VERSION 5.8 ;
BUSBITCHARS "[]" ;
DIVIDERCHAR "/" ;
UNITS
    DATABASE MICRONS 1000 ;
END UNITS

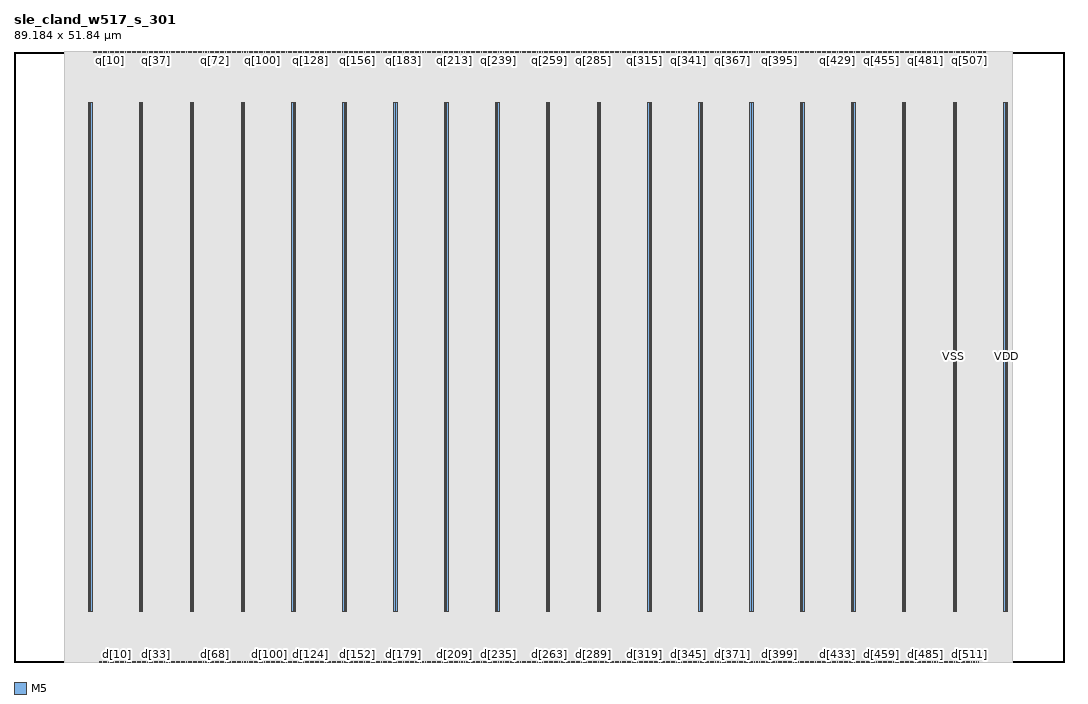
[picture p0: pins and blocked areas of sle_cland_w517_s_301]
MACRO sle_cland_w517_s_301
  FOREIGN sle_cland_w517_s_301 0 0 ;
  CLASS BLOCK ;
  SIZE 89.184 BY 51.84 ;
  PIN clk
    DIRECTION INPUT ;
    USE SIGNAL ;
    PORT
      LAYER M5 ;
        RECT  43.872 51.756 43.896 51.84 ;
    END
  END clk
  PIN d[0]
    DIRECTION INPUT ;
    USE SIGNAL ;
    PORT
      LAYER M5 ;
        RECT  7.296 0 7.32 0.084 ;
    END
  END d[0]
  PIN d[100]
    DIRECTION INPUT ;
    USE SIGNAL ;
    PORT
      LAYER M5 ;
        RECT  21.696 0 21.72 0.084 ;
    END
  END d[100]
  PIN d[101]
    DIRECTION INPUT ;
    USE SIGNAL ;
    PORT
      LAYER M5 ;
        RECT  21.84 0 21.864 0.084 ;
    END
  END d[101]
  PIN d[102]
    DIRECTION INPUT ;
    USE SIGNAL ;
    PORT
      LAYER M5 ;
        RECT  21.984 0 22.008 0.084 ;
    END
  END d[102]
  PIN d[103]
    DIRECTION INPUT ;
    USE SIGNAL ;
    PORT
      LAYER M5 ;
        RECT  22.128 0 22.152 0.084 ;
    END
  END d[103]
  PIN d[104]
    DIRECTION INPUT ;
    USE SIGNAL ;
    PORT
      LAYER M5 ;
        RECT  22.272 0 22.296 0.084 ;
    END
  END d[104]
  PIN d[105]
    DIRECTION INPUT ;
    USE SIGNAL ;
    PORT
      LAYER M5 ;
        RECT  22.416 0 22.44 0.084 ;
    END
  END d[105]
  PIN d[106]
    DIRECTION INPUT ;
    USE SIGNAL ;
    PORT
      LAYER M5 ;
        RECT  22.56 0 22.584 0.084 ;
    END
  END d[106]
  PIN d[107]
    DIRECTION INPUT ;
    USE SIGNAL ;
    PORT
      LAYER M5 ;
        RECT  22.704 0 22.728 0.084 ;
    END
  END d[107]
  PIN d[108]
    DIRECTION INPUT ;
    USE SIGNAL ;
    PORT
      LAYER M5 ;
        RECT  22.848 0 22.872 0.084 ;
    END
  END d[108]
  PIN d[109]
    DIRECTION INPUT ;
    USE SIGNAL ;
    PORT
      LAYER M5 ;
        RECT  22.992 0 23.016 0.084 ;
    END
  END d[109]
  PIN d[10]
    DIRECTION INPUT ;
    USE SIGNAL ;
    PORT
      LAYER M5 ;
        RECT  8.736 0 8.76 0.084 ;
    END
  END d[10]
  PIN d[110]
    DIRECTION INPUT ;
    USE SIGNAL ;
    PORT
      LAYER M5 ;
        RECT  23.136 0 23.16 0.084 ;
    END
  END d[110]
  PIN d[111]
    DIRECTION INPUT ;
    USE SIGNAL ;
    PORT
      LAYER M5 ;
        RECT  23.28 0 23.304 0.084 ;
    END
  END d[111]
  PIN d[112]
    DIRECTION INPUT ;
    USE SIGNAL ;
    PORT
      LAYER M5 ;
        RECT  23.424 0 23.448 0.084 ;
    END
  END d[112]
  PIN d[113]
    DIRECTION INPUT ;
    USE SIGNAL ;
    PORT
      LAYER M5 ;
        RECT  23.568 0 23.592 0.084 ;
    END
  END d[113]
  PIN d[114]
    DIRECTION INPUT ;
    USE SIGNAL ;
    PORT
      LAYER M5 ;
        RECT  23.712 0 23.736 0.084 ;
    END
  END d[114]
  PIN d[115]
    DIRECTION INPUT ;
    USE SIGNAL ;
    PORT
      LAYER M5 ;
        RECT  23.856 0 23.88 0.084 ;
    END
  END d[115]
  PIN d[116]
    DIRECTION INPUT ;
    USE SIGNAL ;
    PORT
      LAYER M5 ;
        RECT  24 0 24.024 0.084 ;
    END
  END d[116]
  PIN d[117]
    DIRECTION INPUT ;
    USE SIGNAL ;
    PORT
      LAYER M5 ;
        RECT  24.144 0 24.168 0.084 ;
    END
  END d[117]
  PIN d[118]
    DIRECTION INPUT ;
    USE SIGNAL ;
    PORT
      LAYER M5 ;
        RECT  24.288 0 24.312 0.084 ;
    END
  END d[118]
  PIN d[119]
    DIRECTION INPUT ;
    USE SIGNAL ;
    PORT
      LAYER M5 ;
        RECT  24.432 0 24.456 0.084 ;
    END
  END d[119]
  PIN d[11]
    DIRECTION INPUT ;
    USE SIGNAL ;
    PORT
      LAYER M5 ;
        RECT  8.88 0 8.904 0.084 ;
    END
  END d[11]
  PIN d[120]
    DIRECTION INPUT ;
    USE SIGNAL ;
    PORT
      LAYER M5 ;
        RECT  24.576 0 24.6 0.084 ;
    END
  END d[120]
  PIN d[121]
    DIRECTION INPUT ;
    USE SIGNAL ;
    PORT
      LAYER M5 ;
        RECT  24.72 0 24.744 0.084 ;
    END
  END d[121]
  PIN d[122]
    DIRECTION INPUT ;
    USE SIGNAL ;
    PORT
      LAYER M5 ;
        RECT  24.864 0 24.888 0.084 ;
    END
  END d[122]
  PIN d[123]
    DIRECTION INPUT ;
    USE SIGNAL ;
    PORT
      LAYER M5 ;
        RECT  25.008 0 25.032 0.084 ;
    END
  END d[123]
  PIN d[124]
    DIRECTION INPUT ;
    USE SIGNAL ;
    PORT
      LAYER M5 ;
        RECT  25.152 0 25.176 0.084 ;
    END
  END d[124]
  PIN d[125]
    DIRECTION INPUT ;
    USE SIGNAL ;
    PORT
      LAYER M5 ;
        RECT  25.296 0 25.32 0.084 ;
    END
  END d[125]
  PIN d[126]
    DIRECTION INPUT ;
    USE SIGNAL ;
    PORT
      LAYER M5 ;
        RECT  25.44 0 25.464 0.084 ;
    END
  END d[126]
  PIN d[127]
    DIRECTION INPUT ;
    USE SIGNAL ;
    PORT
      LAYER M5 ;
        RECT  25.584 0 25.608 0.084 ;
    END
  END d[127]
  PIN d[128]
    DIRECTION INPUT ;
    USE SIGNAL ;
    PORT
      LAYER M5 ;
        RECT  25.728 0 25.752 0.084 ;
    END
  END d[128]
  PIN d[129]
    DIRECTION INPUT ;
    USE SIGNAL ;
    PORT
      LAYER M5 ;
        RECT  25.872 0 25.896 0.084 ;
    END
  END d[129]
  PIN d[12]
    DIRECTION INPUT ;
    USE SIGNAL ;
    PORT
      LAYER M5 ;
        RECT  9.024 0 9.048 0.084 ;
    END
  END d[12]
  PIN d[130]
    DIRECTION INPUT ;
    USE SIGNAL ;
    PORT
      LAYER M5 ;
        RECT  26.016 0 26.04 0.084 ;
    END
  END d[130]
  PIN d[131]
    DIRECTION INPUT ;
    USE SIGNAL ;
    PORT
      LAYER M5 ;
        RECT  26.16 0 26.184 0.084 ;
    END
  END d[131]
  PIN d[132]
    DIRECTION INPUT ;
    USE SIGNAL ;
    PORT
      LAYER M5 ;
        RECT  26.304 0 26.328 0.084 ;
    END
  END d[132]
  PIN d[133]
    DIRECTION INPUT ;
    USE SIGNAL ;
    PORT
      LAYER M5 ;
        RECT  26.448 0 26.472 0.084 ;
    END
  END d[133]
  PIN d[134]
    DIRECTION INPUT ;
    USE SIGNAL ;
    PORT
      LAYER M5 ;
        RECT  26.592 0 26.616 0.084 ;
    END
  END d[134]
  PIN d[135]
    DIRECTION INPUT ;
    USE SIGNAL ;
    PORT
      LAYER M5 ;
        RECT  26.736 0 26.76 0.084 ;
    END
  END d[135]
  PIN d[136]
    DIRECTION INPUT ;
    USE SIGNAL ;
    PORT
      LAYER M5 ;
        RECT  26.88 0 26.904 0.084 ;
    END
  END d[136]
  PIN d[137]
    DIRECTION INPUT ;
    USE SIGNAL ;
    PORT
      LAYER M5 ;
        RECT  27.024 0 27.048 0.084 ;
    END
  END d[137]
  PIN d[138]
    DIRECTION INPUT ;
    USE SIGNAL ;
    PORT
      LAYER M5 ;
        RECT  27.168 0 27.192 0.084 ;
    END
  END d[138]
  PIN d[139]
    DIRECTION INPUT ;
    USE SIGNAL ;
    PORT
      LAYER M5 ;
        RECT  27.312 0 27.336 0.084 ;
    END
  END d[139]
  PIN d[13]
    DIRECTION INPUT ;
    USE SIGNAL ;
    PORT
      LAYER M5 ;
        RECT  9.168 0 9.192 0.084 ;
    END
  END d[13]
  PIN d[140]
    DIRECTION INPUT ;
    USE SIGNAL ;
    PORT
      LAYER M5 ;
        RECT  27.456 0 27.48 0.084 ;
    END
  END d[140]
  PIN d[141]
    DIRECTION INPUT ;
    USE SIGNAL ;
    PORT
      LAYER M5 ;
        RECT  27.6 0 27.624 0.084 ;
    END
  END d[141]
  PIN d[142]
    DIRECTION INPUT ;
    USE SIGNAL ;
    PORT
      LAYER M5 ;
        RECT  27.744 0 27.768 0.084 ;
    END
  END d[142]
  PIN d[143]
    DIRECTION INPUT ;
    USE SIGNAL ;
    PORT
      LAYER M5 ;
        RECT  27.888 0 27.912 0.084 ;
    END
  END d[143]
  PIN d[144]
    DIRECTION INPUT ;
    USE SIGNAL ;
    PORT
      LAYER M5 ;
        RECT  28.032 0 28.056 0.084 ;
    END
  END d[144]
  PIN d[145]
    DIRECTION INPUT ;
    USE SIGNAL ;
    PORT
      LAYER M5 ;
        RECT  28.176 0 28.2 0.084 ;
    END
  END d[145]
  PIN d[146]
    DIRECTION INPUT ;
    USE SIGNAL ;
    PORT
      LAYER M5 ;
        RECT  28.32 0 28.344 0.084 ;
    END
  END d[146]
  PIN d[147]
    DIRECTION INPUT ;
    USE SIGNAL ;
    PORT
      LAYER M5 ;
        RECT  28.464 0 28.488 0.084 ;
    END
  END d[147]
  PIN d[148]
    DIRECTION INPUT ;
    USE SIGNAL ;
    PORT
      LAYER M5 ;
        RECT  28.608 0 28.632 0.084 ;
    END
  END d[148]
  PIN d[149]
    DIRECTION INPUT ;
    USE SIGNAL ;
    PORT
      LAYER M5 ;
        RECT  28.752 0 28.776 0.084 ;
    END
  END d[149]
  PIN d[14]
    DIRECTION INPUT ;
    USE SIGNAL ;
    PORT
      LAYER M5 ;
        RECT  9.312 0 9.336 0.084 ;
    END
  END d[14]
  PIN d[150]
    DIRECTION INPUT ;
    USE SIGNAL ;
    PORT
      LAYER M5 ;
        RECT  28.896 0 28.92 0.084 ;
    END
  END d[150]
  PIN d[151]
    DIRECTION INPUT ;
    USE SIGNAL ;
    PORT
      LAYER M5 ;
        RECT  29.04 0 29.064 0.084 ;
    END
  END d[151]
  PIN d[152]
    DIRECTION INPUT ;
    USE SIGNAL ;
    PORT
      LAYER M5 ;
        RECT  29.184 0 29.208 0.084 ;
    END
  END d[152]
  PIN d[153]
    DIRECTION INPUT ;
    USE SIGNAL ;
    PORT
      LAYER M5 ;
        RECT  29.328 0 29.352 0.084 ;
    END
  END d[153]
  PIN d[154]
    DIRECTION INPUT ;
    USE SIGNAL ;
    PORT
      LAYER M5 ;
        RECT  29.472 0 29.496 0.084 ;
    END
  END d[154]
  PIN d[155]
    DIRECTION INPUT ;
    USE SIGNAL ;
    PORT
      LAYER M5 ;
        RECT  29.616 0 29.64 0.084 ;
    END
  END d[155]
  PIN d[156]
    DIRECTION INPUT ;
    USE SIGNAL ;
    PORT
      LAYER M5 ;
        RECT  29.76 0 29.784 0.084 ;
    END
  END d[156]
  PIN d[157]
    DIRECTION INPUT ;
    USE SIGNAL ;
    PORT
      LAYER M5 ;
        RECT  29.904 0 29.928 0.084 ;
    END
  END d[157]
  PIN d[158]
    DIRECTION INPUT ;
    USE SIGNAL ;
    PORT
      LAYER M5 ;
        RECT  30.048 0 30.072 0.084 ;
    END
  END d[158]
  PIN d[159]
    DIRECTION INPUT ;
    USE SIGNAL ;
    PORT
      LAYER M5 ;
        RECT  30.192 0 30.216 0.084 ;
    END
  END d[159]
  PIN d[15]
    DIRECTION INPUT ;
    USE SIGNAL ;
    PORT
      LAYER M5 ;
        RECT  9.456 0 9.48 0.084 ;
    END
  END d[15]
  PIN d[160]
    DIRECTION INPUT ;
    USE SIGNAL ;
    PORT
      LAYER M5 ;
        RECT  30.336 0 30.36 0.084 ;
    END
  END d[160]
  PIN d[161]
    DIRECTION INPUT ;
    USE SIGNAL ;
    PORT
      LAYER M5 ;
        RECT  30.48 0 30.504 0.084 ;
    END
  END d[161]
  PIN d[162]
    DIRECTION INPUT ;
    USE SIGNAL ;
    PORT
      LAYER M5 ;
        RECT  30.624 0 30.648 0.084 ;
    END
  END d[162]
  PIN d[163]
    DIRECTION INPUT ;
    USE SIGNAL ;
    PORT
      LAYER M5 ;
        RECT  30.768 0 30.792 0.084 ;
    END
  END d[163]
  PIN d[164]
    DIRECTION INPUT ;
    USE SIGNAL ;
    PORT
      LAYER M5 ;
        RECT  30.912 0 30.936 0.084 ;
    END
  END d[164]
  PIN d[165]
    DIRECTION INPUT ;
    USE SIGNAL ;
    PORT
      LAYER M5 ;
        RECT  31.056 0 31.08 0.084 ;
    END
  END d[165]
  PIN d[166]
    DIRECTION INPUT ;
    USE SIGNAL ;
    PORT
      LAYER M5 ;
        RECT  31.2 0 31.224 0.084 ;
    END
  END d[166]
  PIN d[167]
    DIRECTION INPUT ;
    USE SIGNAL ;
    PORT
      LAYER M5 ;
        RECT  31.344 0 31.368 0.084 ;
    END
  END d[167]
  PIN d[168]
    DIRECTION INPUT ;
    USE SIGNAL ;
    PORT
      LAYER M5 ;
        RECT  31.488 0 31.512 0.084 ;
    END
  END d[168]
  PIN d[169]
    DIRECTION INPUT ;
    USE SIGNAL ;
    PORT
      LAYER M5 ;
        RECT  31.632 0 31.656 0.084 ;
    END
  END d[169]
  PIN d[16]
    DIRECTION INPUT ;
    USE SIGNAL ;
    PORT
      LAYER M5 ;
        RECT  9.6 0 9.624 0.084 ;
    END
  END d[16]
  PIN d[170]
    DIRECTION INPUT ;
    USE SIGNAL ;
    PORT
      LAYER M5 ;
        RECT  31.776 0 31.8 0.084 ;
    END
  END d[170]
  PIN d[171]
    DIRECTION INPUT ;
    USE SIGNAL ;
    PORT
      LAYER M5 ;
        RECT  31.92 0 31.944 0.084 ;
    END
  END d[171]
  PIN d[172]
    DIRECTION INPUT ;
    USE SIGNAL ;
    PORT
      LAYER M5 ;
        RECT  32.064 0 32.088 0.084 ;
    END
  END d[172]
  PIN d[173]
    DIRECTION INPUT ;
    USE SIGNAL ;
    PORT
      LAYER M5 ;
        RECT  32.208 0 32.232 0.084 ;
    END
  END d[173]
  PIN d[174]
    DIRECTION INPUT ;
    USE SIGNAL ;
    PORT
      LAYER M5 ;
        RECT  32.352 0 32.376 0.084 ;
    END
  END d[174]
  PIN d[175]
    DIRECTION INPUT ;
    USE SIGNAL ;
    PORT
      LAYER M5 ;
        RECT  32.496 0 32.52 0.084 ;
    END
  END d[175]
  PIN d[176]
    DIRECTION INPUT ;
    USE SIGNAL ;
    PORT
      LAYER M5 ;
        RECT  32.64 0 32.664 0.084 ;
    END
  END d[176]
  PIN d[177]
    DIRECTION INPUT ;
    USE SIGNAL ;
    PORT
      LAYER M5 ;
        RECT  32.784 0 32.808 0.084 ;
    END
  END d[177]
  PIN d[178]
    DIRECTION INPUT ;
    USE SIGNAL ;
    PORT
      LAYER M5 ;
        RECT  32.928 0 32.952 0.084 ;
    END
  END d[178]
  PIN d[179]
    DIRECTION INPUT ;
    USE SIGNAL ;
    PORT
      LAYER M5 ;
        RECT  33.072 0 33.096 0.084 ;
    END
  END d[179]
  PIN d[17]
    DIRECTION INPUT ;
    USE SIGNAL ;
    PORT
      LAYER M5 ;
        RECT  9.744 0 9.768 0.084 ;
    END
  END d[17]
  PIN d[180]
    DIRECTION INPUT ;
    USE SIGNAL ;
    PORT
      LAYER M5 ;
        RECT  33.216 0 33.24 0.084 ;
    END
  END d[180]
  PIN d[181]
    DIRECTION INPUT ;
    USE SIGNAL ;
    PORT
      LAYER M5 ;
        RECT  33.36 0 33.384 0.084 ;
    END
  END d[181]
  PIN d[182]
    DIRECTION INPUT ;
    USE SIGNAL ;
    PORT
      LAYER M5 ;
        RECT  33.504 0 33.528 0.084 ;
    END
  END d[182]
  PIN d[183]
    DIRECTION INPUT ;
    USE SIGNAL ;
    PORT
      LAYER M5 ;
        RECT  33.648 0 33.672 0.084 ;
    END
  END d[183]
  PIN d[184]
    DIRECTION INPUT ;
    USE SIGNAL ;
    PORT
      LAYER M5 ;
        RECT  33.792 0 33.816 0.084 ;
    END
  END d[184]
  PIN d[185]
    DIRECTION INPUT ;
    USE SIGNAL ;
    PORT
      LAYER M5 ;
        RECT  33.936 0 33.96 0.084 ;
    END
  END d[185]
  PIN d[186]
    DIRECTION INPUT ;
    USE SIGNAL ;
    PORT
      LAYER M5 ;
        RECT  34.08 0 34.104 0.084 ;
    END
  END d[186]
  PIN d[187]
    DIRECTION INPUT ;
    USE SIGNAL ;
    PORT
      LAYER M5 ;
        RECT  34.224 0 34.248 0.084 ;
    END
  END d[187]
  PIN d[188]
    DIRECTION INPUT ;
    USE SIGNAL ;
    PORT
      LAYER M5 ;
        RECT  34.368 0 34.392 0.084 ;
    END
  END d[188]
  PIN d[189]
    DIRECTION INPUT ;
    USE SIGNAL ;
    PORT
      LAYER M5 ;
        RECT  34.512 0 34.536 0.084 ;
    END
  END d[189]
  PIN d[18]
    DIRECTION INPUT ;
    USE SIGNAL ;
    PORT
      LAYER M5 ;
        RECT  9.888 0 9.912 0.084 ;
    END
  END d[18]
  PIN d[190]
    DIRECTION INPUT ;
    USE SIGNAL ;
    PORT
      LAYER M5 ;
        RECT  34.656 0 34.68 0.084 ;
    END
  END d[190]
  PIN d[191]
    DIRECTION INPUT ;
    USE SIGNAL ;
    PORT
      LAYER M5 ;
        RECT  34.8 0 34.824 0.084 ;
    END
  END d[191]
  PIN d[192]
    DIRECTION INPUT ;
    USE SIGNAL ;
    PORT
      LAYER M5 ;
        RECT  34.944 0 34.968 0.084 ;
    END
  END d[192]
  PIN d[193]
    DIRECTION INPUT ;
    USE SIGNAL ;
    PORT
      LAYER M5 ;
        RECT  35.088 0 35.112 0.084 ;
    END
  END d[193]
  PIN d[194]
    DIRECTION INPUT ;
    USE SIGNAL ;
    PORT
      LAYER M5 ;
        RECT  35.232 0 35.256 0.084 ;
    END
  END d[194]
  PIN d[195]
    DIRECTION INPUT ;
    USE SIGNAL ;
    PORT
      LAYER M5 ;
        RECT  35.376 0 35.4 0.084 ;
    END
  END d[195]
  PIN d[196]
    DIRECTION INPUT ;
    USE SIGNAL ;
    PORT
      LAYER M5 ;
        RECT  35.52 0 35.544 0.084 ;
    END
  END d[196]
  PIN d[197]
    DIRECTION INPUT ;
    USE SIGNAL ;
    PORT
      LAYER M5 ;
        RECT  35.664 0 35.688 0.084 ;
    END
  END d[197]
  PIN d[198]
    DIRECTION INPUT ;
    USE SIGNAL ;
    PORT
      LAYER M5 ;
        RECT  35.808 0 35.832 0.084 ;
    END
  END d[198]
  PIN d[199]
    DIRECTION INPUT ;
    USE SIGNAL ;
    PORT
      LAYER M5 ;
        RECT  35.952 0 35.976 0.084 ;
    END
  END d[199]
  PIN d[19]
    DIRECTION INPUT ;
    USE SIGNAL ;
    PORT
      LAYER M5 ;
        RECT  10.032 0 10.056 0.084 ;
    END
  END d[19]
  PIN d[1]
    DIRECTION INPUT ;
    USE SIGNAL ;
    PORT
      LAYER M5 ;
        RECT  7.44 0 7.464 0.084 ;
    END
  END d[1]
  PIN d[200]
    DIRECTION INPUT ;
    USE SIGNAL ;
    PORT
      LAYER M5 ;
        RECT  36.096 0 36.12 0.084 ;
    END
  END d[200]
  PIN d[201]
    DIRECTION INPUT ;
    USE SIGNAL ;
    PORT
      LAYER M5 ;
        RECT  36.24 0 36.264 0.084 ;
    END
  END d[201]
  PIN d[202]
    DIRECTION INPUT ;
    USE SIGNAL ;
    PORT
      LAYER M5 ;
        RECT  36.384 0 36.408 0.084 ;
    END
  END d[202]
  PIN d[203]
    DIRECTION INPUT ;
    USE SIGNAL ;
    PORT
      LAYER M5 ;
        RECT  36.528 0 36.552 0.084 ;
    END
  END d[203]
  PIN d[204]
    DIRECTION INPUT ;
    USE SIGNAL ;
    PORT
      LAYER M5 ;
        RECT  36.672 0 36.696 0.084 ;
    END
  END d[204]
  PIN d[205]
    DIRECTION INPUT ;
    USE SIGNAL ;
    PORT
      LAYER M5 ;
        RECT  36.816 0 36.84 0.084 ;
    END
  END d[205]
  PIN d[206]
    DIRECTION INPUT ;
    USE SIGNAL ;
    PORT
      LAYER M5 ;
        RECT  36.96 0 36.984 0.084 ;
    END
  END d[206]
  PIN d[207]
    DIRECTION INPUT ;
    USE SIGNAL ;
    PORT
      LAYER M5 ;
        RECT  37.104 0 37.128 0.084 ;
    END
  END d[207]
  PIN d[208]
    DIRECTION INPUT ;
    USE SIGNAL ;
    PORT
      LAYER M5 ;
        RECT  37.248 0 37.272 0.084 ;
    END
  END d[208]
  PIN d[209]
    DIRECTION INPUT ;
    USE SIGNAL ;
    PORT
      LAYER M5 ;
        RECT  37.392 0 37.416 0.084 ;
    END
  END d[209]
  PIN d[20]
    DIRECTION INPUT ;
    USE SIGNAL ;
    PORT
      LAYER M5 ;
        RECT  10.176 0 10.2 0.084 ;
    END
  END d[20]
  PIN d[210]
    DIRECTION INPUT ;
    USE SIGNAL ;
    PORT
      LAYER M5 ;
        RECT  37.536 0 37.56 0.084 ;
    END
  END d[210]
  PIN d[211]
    DIRECTION INPUT ;
    USE SIGNAL ;
    PORT
      LAYER M5 ;
        RECT  37.68 0 37.704 0.084 ;
    END
  END d[211]
  PIN d[212]
    DIRECTION INPUT ;
    USE SIGNAL ;
    PORT
      LAYER M5 ;
        RECT  37.824 0 37.848 0.084 ;
    END
  END d[212]
  PIN d[213]
    DIRECTION INPUT ;
    USE SIGNAL ;
    PORT
      LAYER M5 ;
        RECT  37.968 0 37.992 0.084 ;
    END
  END d[213]
  PIN d[214]
    DIRECTION INPUT ;
    USE SIGNAL ;
    PORT
      LAYER M5 ;
        RECT  38.112 0 38.136 0.084 ;
    END
  END d[214]
  PIN d[215]
    DIRECTION INPUT ;
    USE SIGNAL ;
    PORT
      LAYER M5 ;
        RECT  38.256 0 38.28 0.084 ;
    END
  END d[215]
  PIN d[216]
    DIRECTION INPUT ;
    USE SIGNAL ;
    PORT
      LAYER M5 ;
        RECT  38.4 0 38.424 0.084 ;
    END
  END d[216]
  PIN d[217]
    DIRECTION INPUT ;
    USE SIGNAL ;
    PORT
      LAYER M5 ;
        RECT  38.544 0 38.568 0.084 ;
    END
  END d[217]
  PIN d[218]
    DIRECTION INPUT ;
    USE SIGNAL ;
    PORT
      LAYER M5 ;
        RECT  38.688 0 38.712 0.084 ;
    END
  END d[218]
  PIN d[219]
    DIRECTION INPUT ;
    USE SIGNAL ;
    PORT
      LAYER M5 ;
        RECT  38.832 0 38.856 0.084 ;
    END
  END d[219]
  PIN d[21]
    DIRECTION INPUT ;
    USE SIGNAL ;
    PORT
      LAYER M5 ;
        RECT  10.32 0 10.344 0.084 ;
    END
  END d[21]
  PIN d[220]
    DIRECTION INPUT ;
    USE SIGNAL ;
    PORT
      LAYER M5 ;
        RECT  38.976 0 39 0.084 ;
    END
  END d[220]
  PIN d[221]
    DIRECTION INPUT ;
    USE SIGNAL ;
    PORT
      LAYER M5 ;
        RECT  39.12 0 39.144 0.084 ;
    END
  END d[221]
  PIN d[222]
    DIRECTION INPUT ;
    USE SIGNAL ;
    PORT
      LAYER M5 ;
        RECT  39.264 0 39.288 0.084 ;
    END
  END d[222]
  PIN d[223]
    DIRECTION INPUT ;
    USE SIGNAL ;
    PORT
      LAYER M5 ;
        RECT  39.408 0 39.432 0.084 ;
    END
  END d[223]
  PIN d[224]
    DIRECTION INPUT ;
    USE SIGNAL ;
    PORT
      LAYER M5 ;
        RECT  39.552 0 39.576 0.084 ;
    END
  END d[224]
  PIN d[225]
    DIRECTION INPUT ;
    USE SIGNAL ;
    PORT
      LAYER M5 ;
        RECT  39.696 0 39.72 0.084 ;
    END
  END d[225]
  PIN d[226]
    DIRECTION INPUT ;
    USE SIGNAL ;
    PORT
      LAYER M5 ;
        RECT  39.84 0 39.864 0.084 ;
    END
  END d[226]
  PIN d[227]
    DIRECTION INPUT ;
    USE SIGNAL ;
    PORT
      LAYER M5 ;
        RECT  39.984 0 40.008 0.084 ;
    END
  END d[227]
  PIN d[228]
    DIRECTION INPUT ;
    USE SIGNAL ;
    PORT
      LAYER M5 ;
        RECT  40.128 0 40.152 0.084 ;
    END
  END d[228]
  PIN d[229]
    DIRECTION INPUT ;
    USE SIGNAL ;
    PORT
      LAYER M5 ;
        RECT  40.272 0 40.296 0.084 ;
    END
  END d[229]
  PIN d[22]
    DIRECTION INPUT ;
    USE SIGNAL ;
    PORT
      LAYER M5 ;
        RECT  10.464 0 10.488 0.084 ;
    END
  END d[22]
  PIN d[230]
    DIRECTION INPUT ;
    USE SIGNAL ;
    PORT
      LAYER M5 ;
        RECT  40.416 0 40.44 0.084 ;
    END
  END d[230]
  PIN d[231]
    DIRECTION INPUT ;
    USE SIGNAL ;
    PORT
      LAYER M5 ;
        RECT  40.56 0 40.584 0.084 ;
    END
  END d[231]
  PIN d[232]
    DIRECTION INPUT ;
    USE SIGNAL ;
    PORT
      LAYER M5 ;
        RECT  40.704 0 40.728 0.084 ;
    END
  END d[232]
  PIN d[233]
    DIRECTION INPUT ;
    USE SIGNAL ;
    PORT
      LAYER M5 ;
        RECT  40.848 0 40.872 0.084 ;
    END
  END d[233]
  PIN d[234]
    DIRECTION INPUT ;
    USE SIGNAL ;
    PORT
      LAYER M5 ;
        RECT  40.992 0 41.016 0.084 ;
    END
  END d[234]
  PIN d[235]
    DIRECTION INPUT ;
    USE SIGNAL ;
    PORT
      LAYER M5 ;
        RECT  41.136 0 41.16 0.084 ;
    END
  END d[235]
  PIN d[236]
    DIRECTION INPUT ;
    USE SIGNAL ;
    PORT
      LAYER M5 ;
        RECT  41.28 0 41.304 0.084 ;
    END
  END d[236]
  PIN d[237]
    DIRECTION INPUT ;
    USE SIGNAL ;
    PORT
      LAYER M5 ;
        RECT  41.424 0 41.448 0.084 ;
    END
  END d[237]
  PIN d[238]
    DIRECTION INPUT ;
    USE SIGNAL ;
    PORT
      LAYER M5 ;
        RECT  41.568 0 41.592 0.084 ;
    END
  END d[238]
  PIN d[239]
    DIRECTION INPUT ;
    USE SIGNAL ;
    PORT
      LAYER M5 ;
        RECT  41.712 0 41.736 0.084 ;
    END
  END d[239]
  PIN d[23]
    DIRECTION INPUT ;
    USE SIGNAL ;
    PORT
      LAYER M5 ;
        RECT  10.608 0 10.632 0.084 ;
    END
  END d[23]
  PIN d[240]
    DIRECTION INPUT ;
    USE SIGNAL ;
    PORT
      LAYER M5 ;
        RECT  41.856 0 41.88 0.084 ;
    END
  END d[240]
  PIN d[241]
    DIRECTION INPUT ;
    USE SIGNAL ;
    PORT
      LAYER M5 ;
        RECT  42 0 42.024 0.084 ;
    END
  END d[241]
  PIN d[242]
    DIRECTION INPUT ;
    USE SIGNAL ;
    PORT
      LAYER M5 ;
        RECT  42.144 0 42.168 0.084 ;
    END
  END d[242]
  PIN d[243]
    DIRECTION INPUT ;
    USE SIGNAL ;
    PORT
      LAYER M5 ;
        RECT  42.288 0 42.312 0.084 ;
    END
  END d[243]
  PIN d[244]
    DIRECTION INPUT ;
    USE SIGNAL ;
    PORT
      LAYER M5 ;
        RECT  42.432 0 42.456 0.084 ;
    END
  END d[244]
  PIN d[245]
    DIRECTION INPUT ;
    USE SIGNAL ;
    PORT
      LAYER M5 ;
        RECT  42.576 0 42.6 0.084 ;
    END
  END d[245]
  PIN d[246]
    DIRECTION INPUT ;
    USE SIGNAL ;
    PORT
      LAYER M5 ;
        RECT  42.72 0 42.744 0.084 ;
    END
  END d[246]
  PIN d[247]
    DIRECTION INPUT ;
    USE SIGNAL ;
    PORT
      LAYER M5 ;
        RECT  42.864 0 42.888 0.084 ;
    END
  END d[247]
  PIN d[248]
    DIRECTION INPUT ;
    USE SIGNAL ;
    PORT
      LAYER M5 ;
        RECT  43.008 0 43.032 0.084 ;
    END
  END d[248]
  PIN d[249]
    DIRECTION INPUT ;
    USE SIGNAL ;
    PORT
      LAYER M5 ;
        RECT  43.152 0 43.176 0.084 ;
    END
  END d[249]
  PIN d[24]
    DIRECTION INPUT ;
    USE SIGNAL ;
    PORT
      LAYER M5 ;
        RECT  10.752 0 10.776 0.084 ;
    END
  END d[24]
  PIN d[250]
    DIRECTION INPUT ;
    USE SIGNAL ;
    PORT
      LAYER M5 ;
        RECT  43.296 0 43.32 0.084 ;
    END
  END d[250]
  PIN d[251]
    DIRECTION INPUT ;
    USE SIGNAL ;
    PORT
      LAYER M5 ;
        RECT  43.44 0 43.464 0.084 ;
    END
  END d[251]
  PIN d[252]
    DIRECTION INPUT ;
    USE SIGNAL ;
    PORT
      LAYER M5 ;
        RECT  43.584 0 43.608 0.084 ;
    END
  END d[252]
  PIN d[253]
    DIRECTION INPUT ;
    USE SIGNAL ;
    PORT
      LAYER M5 ;
        RECT  43.728 0 43.752 0.084 ;
    END
  END d[253]
  PIN d[254]
    DIRECTION INPUT ;
    USE SIGNAL ;
    PORT
      LAYER M5 ;
        RECT  43.872 0 43.896 0.084 ;
    END
  END d[254]
  PIN d[255]
    DIRECTION INPUT ;
    USE SIGNAL ;
    PORT
      LAYER M5 ;
        RECT  44.016 0 44.04 0.084 ;
    END
  END d[255]
  PIN d[256]
    DIRECTION INPUT ;
    USE SIGNAL ;
    PORT
      LAYER M5 ;
        RECT  44.16 0 44.184 0.084 ;
    END
  END d[256]
  PIN d[257]
    DIRECTION INPUT ;
    USE SIGNAL ;
    PORT
      LAYER M5 ;
        RECT  44.304 0 44.328 0.084 ;
    END
  END d[257]
  PIN d[258]
    DIRECTION INPUT ;
    USE SIGNAL ;
    PORT
      LAYER M5 ;
        RECT  44.736 0 44.76 0.084 ;
    END
  END d[258]
  PIN d[259]
    DIRECTION INPUT ;
    USE SIGNAL ;
    PORT
      LAYER M5 ;
        RECT  44.88 0 44.904 0.084 ;
    END
  END d[259]
  PIN d[25]
    DIRECTION INPUT ;
    USE SIGNAL ;
    PORT
      LAYER M5 ;
        RECT  10.896 0 10.92 0.084 ;
    END
  END d[25]
  PIN d[260]
    DIRECTION INPUT ;
    USE SIGNAL ;
    PORT
      LAYER M5 ;
        RECT  45.024 0 45.048 0.084 ;
    END
  END d[260]
  PIN d[261]
    DIRECTION INPUT ;
    USE SIGNAL ;
    PORT
      LAYER M5 ;
        RECT  45.168 0 45.192 0.084 ;
    END
  END d[261]
  PIN d[262]
    DIRECTION INPUT ;
    USE SIGNAL ;
    PORT
      LAYER M5 ;
        RECT  45.312 0 45.336 0.084 ;
    END
  END d[262]
  PIN d[263]
    DIRECTION INPUT ;
    USE SIGNAL ;
    PORT
      LAYER M5 ;
        RECT  45.456 0 45.48 0.084 ;
    END
  END d[263]
  PIN d[264]
    DIRECTION INPUT ;
    USE SIGNAL ;
    PORT
      LAYER M5 ;
        RECT  45.6 0 45.624 0.084 ;
    END
  END d[264]
  PIN d[265]
    DIRECTION INPUT ;
    USE SIGNAL ;
    PORT
      LAYER M5 ;
        RECT  45.744 0 45.768 0.084 ;
    END
  END d[265]
  PIN d[266]
    DIRECTION INPUT ;
    USE SIGNAL ;
    PORT
      LAYER M5 ;
        RECT  45.888 0 45.912 0.084 ;
    END
  END d[266]
  PIN d[267]
    DIRECTION INPUT ;
    USE SIGNAL ;
    PORT
      LAYER M5 ;
        RECT  46.032 0 46.056 0.084 ;
    END
  END d[267]
  PIN d[268]
    DIRECTION INPUT ;
    USE SIGNAL ;
    PORT
      LAYER M5 ;
        RECT  46.176 0 46.2 0.084 ;
    END
  END d[268]
  PIN d[269]
    DIRECTION INPUT ;
    USE SIGNAL ;
    PORT
      LAYER M5 ;
        RECT  46.32 0 46.344 0.084 ;
    END
  END d[269]
  PIN d[26]
    DIRECTION INPUT ;
    USE SIGNAL ;
    PORT
      LAYER M5 ;
        RECT  11.04 0 11.064 0.084 ;
    END
  END d[26]
  PIN d[270]
    DIRECTION INPUT ;
    USE SIGNAL ;
    PORT
      LAYER M5 ;
        RECT  46.464 0 46.488 0.084 ;
    END
  END d[270]
  PIN d[271]
    DIRECTION INPUT ;
    USE SIGNAL ;
    PORT
      LAYER M5 ;
        RECT  46.608 0 46.632 0.084 ;
    END
  END d[271]
  PIN d[272]
    DIRECTION INPUT ;
    USE SIGNAL ;
    PORT
      LAYER M5 ;
        RECT  46.752 0 46.776 0.084 ;
    END
  END d[272]
  PIN d[273]
    DIRECTION INPUT ;
    USE SIGNAL ;
    PORT
      LAYER M5 ;
        RECT  46.896 0 46.92 0.084 ;
    END
  END d[273]
  PIN d[274]
    DIRECTION INPUT ;
    USE SIGNAL ;
    PORT
      LAYER M5 ;
        RECT  47.04 0 47.064 0.084 ;
    END
  END d[274]
  PIN d[275]
    DIRECTION INPUT ;
    USE SIGNAL ;
    PORT
      LAYER M5 ;
        RECT  47.184 0 47.208 0.084 ;
    END
  END d[275]
  PIN d[276]
    DIRECTION INPUT ;
    USE SIGNAL ;
    PORT
      LAYER M5 ;
        RECT  47.328 0 47.352 0.084 ;
    END
  END d[276]
  PIN d[277]
    DIRECTION INPUT ;
    USE SIGNAL ;
    PORT
      LAYER M5 ;
        RECT  47.472 0 47.496 0.084 ;
    END
  END d[277]
  PIN d[278]
    DIRECTION INPUT ;
    USE SIGNAL ;
    PORT
      LAYER M5 ;
        RECT  47.616 0 47.64 0.084 ;
    END
  END d[278]
  PIN d[279]
    DIRECTION INPUT ;
    USE SIGNAL ;
    PORT
      LAYER M5 ;
        RECT  47.76 0 47.784 0.084 ;
    END
  END d[279]
  PIN d[27]
    DIRECTION INPUT ;
    USE SIGNAL ;
    PORT
      LAYER M5 ;
        RECT  11.184 0 11.208 0.084 ;
    END
  END d[27]
  PIN d[280]
    DIRECTION INPUT ;
    USE SIGNAL ;
    PORT
      LAYER M5 ;
        RECT  47.904 0 47.928 0.084 ;
    END
  END d[280]
  PIN d[281]
    DIRECTION INPUT ;
    USE SIGNAL ;
    PORT
      LAYER M5 ;
        RECT  48.048 0 48.072 0.084 ;
    END
  END d[281]
  PIN d[282]
    DIRECTION INPUT ;
    USE SIGNAL ;
    PORT
      LAYER M5 ;
        RECT  48.192 0 48.216 0.084 ;
    END
  END d[282]
  PIN d[283]
    DIRECTION INPUT ;
    USE SIGNAL ;
    PORT
      LAYER M5 ;
        RECT  48.336 0 48.36 0.084 ;
    END
  END d[283]
  PIN d[284]
    DIRECTION INPUT ;
    USE SIGNAL ;
    PORT
      LAYER M5 ;
        RECT  48.48 0 48.504 0.084 ;
    END
  END d[284]
  PIN d[285]
    DIRECTION INPUT ;
    USE SIGNAL ;
    PORT
      LAYER M5 ;
        RECT  48.624 0 48.648 0.084 ;
    END
  END d[285]
  PIN d[286]
    DIRECTION INPUT ;
    USE SIGNAL ;
    PORT
      LAYER M5 ;
        RECT  48.768 0 48.792 0.084 ;
    END
  END d[286]
  PIN d[287]
    DIRECTION INPUT ;
    USE SIGNAL ;
    PORT
      LAYER M5 ;
        RECT  48.912 0 48.936 0.084 ;
    END
  END d[287]
  PIN d[288]
    DIRECTION INPUT ;
    USE SIGNAL ;
    PORT
      LAYER M5 ;
        RECT  49.056 0 49.08 0.084 ;
    END
  END d[288]
  PIN d[289]
    DIRECTION INPUT ;
    USE SIGNAL ;
    PORT
      LAYER M5 ;
        RECT  49.2 0 49.224 0.084 ;
    END
  END d[289]
  PIN d[28]
    DIRECTION INPUT ;
    USE SIGNAL ;
    PORT
      LAYER M5 ;
        RECT  11.328 0 11.352 0.084 ;
    END
  END d[28]
  PIN d[290]
    DIRECTION INPUT ;
    USE SIGNAL ;
    PORT
      LAYER M5 ;
        RECT  49.344 0 49.368 0.084 ;
    END
  END d[290]
  PIN d[291]
    DIRECTION INPUT ;
    USE SIGNAL ;
    PORT
      LAYER M5 ;
        RECT  49.488 0 49.512 0.084 ;
    END
  END d[291]
  PIN d[292]
    DIRECTION INPUT ;
    USE SIGNAL ;
    PORT
      LAYER M5 ;
        RECT  49.632 0 49.656 0.084 ;
    END
  END d[292]
  PIN d[293]
    DIRECTION INPUT ;
    USE SIGNAL ;
    PORT
      LAYER M5 ;
        RECT  49.776 0 49.8 0.084 ;
    END
  END d[293]
  PIN d[294]
    DIRECTION INPUT ;
    USE SIGNAL ;
    PORT
      LAYER M5 ;
        RECT  49.92 0 49.944 0.084 ;
    END
  END d[294]
  PIN d[295]
    DIRECTION INPUT ;
    USE SIGNAL ;
    PORT
      LAYER M5 ;
        RECT  50.064 0 50.088 0.084 ;
    END
  END d[295]
  PIN d[296]
    DIRECTION INPUT ;
    USE SIGNAL ;
    PORT
      LAYER M5 ;
        RECT  50.208 0 50.232 0.084 ;
    END
  END d[296]
  PIN d[297]
    DIRECTION INPUT ;
    USE SIGNAL ;
    PORT
      LAYER M5 ;
        RECT  50.352 0 50.376 0.084 ;
    END
  END d[297]
  PIN d[298]
    DIRECTION INPUT ;
    USE SIGNAL ;
    PORT
      LAYER M5 ;
        RECT  50.496 0 50.52 0.084 ;
    END
  END d[298]
  PIN d[299]
    DIRECTION INPUT ;
    USE SIGNAL ;
    PORT
      LAYER M5 ;
        RECT  50.64 0 50.664 0.084 ;
    END
  END d[299]
  PIN d[29]
    DIRECTION INPUT ;
    USE SIGNAL ;
    PORT
      LAYER M5 ;
        RECT  11.472 0 11.496 0.084 ;
    END
  END d[29]
  PIN d[2]
    DIRECTION INPUT ;
    USE SIGNAL ;
    PORT
      LAYER M5 ;
        RECT  7.584 0 7.608 0.084 ;
    END
  END d[2]
  PIN d[300]
    DIRECTION INPUT ;
    USE SIGNAL ;
    PORT
      LAYER M5 ;
        RECT  50.784 0 50.808 0.084 ;
    END
  END d[300]
  PIN d[301]
    DIRECTION INPUT ;
    USE SIGNAL ;
    PORT
      LAYER M5 ;
        RECT  50.928 0 50.952 0.084 ;
    END
  END d[301]
  PIN d[302]
    DIRECTION INPUT ;
    USE SIGNAL ;
    PORT
      LAYER M5 ;
        RECT  51.072 0 51.096 0.084 ;
    END
  END d[302]
  PIN d[303]
    DIRECTION INPUT ;
    USE SIGNAL ;
    PORT
      LAYER M5 ;
        RECT  51.216 0 51.24 0.084 ;
    END
  END d[303]
  PIN d[304]
    DIRECTION INPUT ;
    USE SIGNAL ;
    PORT
      LAYER M5 ;
        RECT  51.36 0 51.384 0.084 ;
    END
  END d[304]
  PIN d[305]
    DIRECTION INPUT ;
    USE SIGNAL ;
    PORT
      LAYER M5 ;
        RECT  51.504 0 51.528 0.084 ;
    END
  END d[305]
  PIN d[306]
    DIRECTION INPUT ;
    USE SIGNAL ;
    PORT
      LAYER M5 ;
        RECT  51.648 0 51.672 0.084 ;
    END
  END d[306]
  PIN d[307]
    DIRECTION INPUT ;
    USE SIGNAL ;
    PORT
      LAYER M5 ;
        RECT  51.792 0 51.816 0.084 ;
    END
  END d[307]
  PIN d[308]
    DIRECTION INPUT ;
    USE SIGNAL ;
    PORT
      LAYER M5 ;
        RECT  51.936 0 51.96 0.084 ;
    END
  END d[308]
  PIN d[309]
    DIRECTION INPUT ;
    USE SIGNAL ;
    PORT
      LAYER M5 ;
        RECT  52.08 0 52.104 0.084 ;
    END
  END d[309]
  PIN d[30]
    DIRECTION INPUT ;
    USE SIGNAL ;
    PORT
      LAYER M5 ;
        RECT  11.616 0 11.64 0.084 ;
    END
  END d[30]
  PIN d[310]
    DIRECTION INPUT ;
    USE SIGNAL ;
    PORT
      LAYER M5 ;
        RECT  52.224 0 52.248 0.084 ;
    END
  END d[310]
  PIN d[311]
    DIRECTION INPUT ;
    USE SIGNAL ;
    PORT
      LAYER M5 ;
        RECT  52.368 0 52.392 0.084 ;
    END
  END d[311]
  PIN d[312]
    DIRECTION INPUT ;
    USE SIGNAL ;
    PORT
      LAYER M5 ;
        RECT  52.512 0 52.536 0.084 ;
    END
  END d[312]
  PIN d[313]
    DIRECTION INPUT ;
    USE SIGNAL ;
    PORT
      LAYER M5 ;
        RECT  52.656 0 52.68 0.084 ;
    END
  END d[313]
  PIN d[314]
    DIRECTION INPUT ;
    USE SIGNAL ;
    PORT
      LAYER M5 ;
        RECT  52.8 0 52.824 0.084 ;
    END
  END d[314]
  PIN d[315]
    DIRECTION INPUT ;
    USE SIGNAL ;
    PORT
      LAYER M5 ;
        RECT  52.944 0 52.968 0.084 ;
    END
  END d[315]
  PIN d[316]
    DIRECTION INPUT ;
    USE SIGNAL ;
    PORT
      LAYER M5 ;
        RECT  53.088 0 53.112 0.084 ;
    END
  END d[316]
  PIN d[317]
    DIRECTION INPUT ;
    USE SIGNAL ;
    PORT
      LAYER M5 ;
        RECT  53.232 0 53.256 0.084 ;
    END
  END d[317]
  PIN d[318]
    DIRECTION INPUT ;
    USE SIGNAL ;
    PORT
      LAYER M5 ;
        RECT  53.376 0 53.4 0.084 ;
    END
  END d[318]
  PIN d[319]
    DIRECTION INPUT ;
    USE SIGNAL ;
    PORT
      LAYER M5 ;
        RECT  53.52 0 53.544 0.084 ;
    END
  END d[319]
  PIN d[31]
    DIRECTION INPUT ;
    USE SIGNAL ;
    PORT
      LAYER M5 ;
        RECT  11.76 0 11.784 0.084 ;
    END
  END d[31]
  PIN d[320]
    DIRECTION INPUT ;
    USE SIGNAL ;
    PORT
      LAYER M5 ;
        RECT  53.664 0 53.688 0.084 ;
    END
  END d[320]
  PIN d[321]
    DIRECTION INPUT ;
    USE SIGNAL ;
    PORT
      LAYER M5 ;
        RECT  53.808 0 53.832 0.084 ;
    END
  END d[321]
  PIN d[322]
    DIRECTION INPUT ;
    USE SIGNAL ;
    PORT
      LAYER M5 ;
        RECT  53.952 0 53.976 0.084 ;
    END
  END d[322]
  PIN d[323]
    DIRECTION INPUT ;
    USE SIGNAL ;
    PORT
      LAYER M5 ;
        RECT  54.096 0 54.12 0.084 ;
    END
  END d[323]
  PIN d[324]
    DIRECTION INPUT ;
    USE SIGNAL ;
    PORT
      LAYER M5 ;
        RECT  54.24 0 54.264 0.084 ;
    END
  END d[324]
  PIN d[325]
    DIRECTION INPUT ;
    USE SIGNAL ;
    PORT
      LAYER M5 ;
        RECT  54.384 0 54.408 0.084 ;
    END
  END d[325]
  PIN d[326]
    DIRECTION INPUT ;
    USE SIGNAL ;
    PORT
      LAYER M5 ;
        RECT  54.528 0 54.552 0.084 ;
    END
  END d[326]
  PIN d[327]
    DIRECTION INPUT ;
    USE SIGNAL ;
    PORT
      LAYER M5 ;
        RECT  54.672 0 54.696 0.084 ;
    END
  END d[327]
  PIN d[328]
    DIRECTION INPUT ;
    USE SIGNAL ;
    PORT
      LAYER M5 ;
        RECT  54.816 0 54.84 0.084 ;
    END
  END d[328]
  PIN d[329]
    DIRECTION INPUT ;
    USE SIGNAL ;
    PORT
      LAYER M5 ;
        RECT  54.96 0 54.984 0.084 ;
    END
  END d[329]
  PIN d[32]
    DIRECTION INPUT ;
    USE SIGNAL ;
    PORT
      LAYER M5 ;
        RECT  11.904 0 11.928 0.084 ;
    END
  END d[32]
  PIN d[330]
    DIRECTION INPUT ;
    USE SIGNAL ;
    PORT
      LAYER M5 ;
        RECT  55.104 0 55.128 0.084 ;
    END
  END d[330]
  PIN d[331]
    DIRECTION INPUT ;
    USE SIGNAL ;
    PORT
      LAYER M5 ;
        RECT  55.248 0 55.272 0.084 ;
    END
  END d[331]
  PIN d[332]
    DIRECTION INPUT ;
    USE SIGNAL ;
    PORT
      LAYER M5 ;
        RECT  55.392 0 55.416 0.084 ;
    END
  END d[332]
  PIN d[333]
    DIRECTION INPUT ;
    USE SIGNAL ;
    PORT
      LAYER M5 ;
        RECT  55.536 0 55.56 0.084 ;
    END
  END d[333]
  PIN d[334]
    DIRECTION INPUT ;
    USE SIGNAL ;
    PORT
      LAYER M5 ;
        RECT  55.68 0 55.704 0.084 ;
    END
  END d[334]
  PIN d[335]
    DIRECTION INPUT ;
    USE SIGNAL ;
    PORT
      LAYER M5 ;
        RECT  55.824 0 55.848 0.084 ;
    END
  END d[335]
  PIN d[336]
    DIRECTION INPUT ;
    USE SIGNAL ;
    PORT
      LAYER M5 ;
        RECT  55.968 0 55.992 0.084 ;
    END
  END d[336]
  PIN d[337]
    DIRECTION INPUT ;
    USE SIGNAL ;
    PORT
      LAYER M5 ;
        RECT  56.112 0 56.136 0.084 ;
    END
  END d[337]
  PIN d[338]
    DIRECTION INPUT ;
    USE SIGNAL ;
    PORT
      LAYER M5 ;
        RECT  56.256 0 56.28 0.084 ;
    END
  END d[338]
  PIN d[339]
    DIRECTION INPUT ;
    USE SIGNAL ;
    PORT
      LAYER M5 ;
        RECT  56.4 0 56.424 0.084 ;
    END
  END d[339]
  PIN d[33]
    DIRECTION INPUT ;
    USE SIGNAL ;
    PORT
      LAYER M5 ;
        RECT  12.048 0 12.072 0.084 ;
    END
  END d[33]
  PIN d[340]
    DIRECTION INPUT ;
    USE SIGNAL ;
    PORT
      LAYER M5 ;
        RECT  56.544 0 56.568 0.084 ;
    END
  END d[340]
  PIN d[341]
    DIRECTION INPUT ;
    USE SIGNAL ;
    PORT
      LAYER M5 ;
        RECT  56.688 0 56.712 0.084 ;
    END
  END d[341]
  PIN d[342]
    DIRECTION INPUT ;
    USE SIGNAL ;
    PORT
      LAYER M5 ;
        RECT  56.832 0 56.856 0.084 ;
    END
  END d[342]
  PIN d[343]
    DIRECTION INPUT ;
    USE SIGNAL ;
    PORT
      LAYER M5 ;
        RECT  56.976 0 57 0.084 ;
    END
  END d[343]
  PIN d[344]
    DIRECTION INPUT ;
    USE SIGNAL ;
    PORT
      LAYER M5 ;
        RECT  57.12 0 57.144 0.084 ;
    END
  END d[344]
  PIN d[345]
    DIRECTION INPUT ;
    USE SIGNAL ;
    PORT
      LAYER M5 ;
        RECT  57.264 0 57.288 0.084 ;
    END
  END d[345]
  PIN d[346]
    DIRECTION INPUT ;
    USE SIGNAL ;
    PORT
      LAYER M5 ;
        RECT  57.408 0 57.432 0.084 ;
    END
  END d[346]
  PIN d[347]
    DIRECTION INPUT ;
    USE SIGNAL ;
    PORT
      LAYER M5 ;
        RECT  57.552 0 57.576 0.084 ;
    END
  END d[347]
  PIN d[348]
    DIRECTION INPUT ;
    USE SIGNAL ;
    PORT
      LAYER M5 ;
        RECT  57.696 0 57.72 0.084 ;
    END
  END d[348]
  PIN d[349]
    DIRECTION INPUT ;
    USE SIGNAL ;
    PORT
      LAYER M5 ;
        RECT  57.84 0 57.864 0.084 ;
    END
  END d[349]
  PIN d[34]
    DIRECTION INPUT ;
    USE SIGNAL ;
    PORT
      LAYER M5 ;
        RECT  12.192 0 12.216 0.084 ;
    END
  END d[34]
  PIN d[350]
    DIRECTION INPUT ;
    USE SIGNAL ;
    PORT
      LAYER M5 ;
        RECT  57.984 0 58.008 0.084 ;
    END
  END d[350]
  PIN d[351]
    DIRECTION INPUT ;
    USE SIGNAL ;
    PORT
      LAYER M5 ;
        RECT  58.128 0 58.152 0.084 ;
    END
  END d[351]
  PIN d[352]
    DIRECTION INPUT ;
    USE SIGNAL ;
    PORT
      LAYER M5 ;
        RECT  58.272 0 58.296 0.084 ;
    END
  END d[352]
  PIN d[353]
    DIRECTION INPUT ;
    USE SIGNAL ;
    PORT
      LAYER M5 ;
        RECT  58.416 0 58.44 0.084 ;
    END
  END d[353]
  PIN d[354]
    DIRECTION INPUT ;
    USE SIGNAL ;
    PORT
      LAYER M5 ;
        RECT  58.56 0 58.584 0.084 ;
    END
  END d[354]
  PIN d[355]
    DIRECTION INPUT ;
    USE SIGNAL ;
    PORT
      LAYER M5 ;
        RECT  58.704 0 58.728 0.084 ;
    END
  END d[355]
  PIN d[356]
    DIRECTION INPUT ;
    USE SIGNAL ;
    PORT
      LAYER M5 ;
        RECT  58.848 0 58.872 0.084 ;
    END
  END d[356]
  PIN d[357]
    DIRECTION INPUT ;
    USE SIGNAL ;
    PORT
      LAYER M5 ;
        RECT  58.992 0 59.016 0.084 ;
    END
  END d[357]
  PIN d[358]
    DIRECTION INPUT ;
    USE SIGNAL ;
    PORT
      LAYER M5 ;
        RECT  59.136 0 59.16 0.084 ;
    END
  END d[358]
  PIN d[359]
    DIRECTION INPUT ;
    USE SIGNAL ;
    PORT
      LAYER M5 ;
        RECT  59.28 0 59.304 0.084 ;
    END
  END d[359]
  PIN d[35]
    DIRECTION INPUT ;
    USE SIGNAL ;
    PORT
      LAYER M5 ;
        RECT  12.336 0 12.36 0.084 ;
    END
  END d[35]
  PIN d[360]
    DIRECTION INPUT ;
    USE SIGNAL ;
    PORT
      LAYER M5 ;
        RECT  59.424 0 59.448 0.084 ;
    END
  END d[360]
  PIN d[361]
    DIRECTION INPUT ;
    USE SIGNAL ;
    PORT
      LAYER M5 ;
        RECT  59.568 0 59.592 0.084 ;
    END
  END d[361]
  PIN d[362]
    DIRECTION INPUT ;
    USE SIGNAL ;
    PORT
      LAYER M5 ;
        RECT  59.712 0 59.736 0.084 ;
    END
  END d[362]
  PIN d[363]
    DIRECTION INPUT ;
    USE SIGNAL ;
    PORT
      LAYER M5 ;
        RECT  59.856 0 59.88 0.084 ;
    END
  END d[363]
  PIN d[364]
    DIRECTION INPUT ;
    USE SIGNAL ;
    PORT
      LAYER M5 ;
        RECT  60 0 60.024 0.084 ;
    END
  END d[364]
  PIN d[365]
    DIRECTION INPUT ;
    USE SIGNAL ;
    PORT
      LAYER M5 ;
        RECT  60.144 0 60.168 0.084 ;
    END
  END d[365]
  PIN d[366]
    DIRECTION INPUT ;
    USE SIGNAL ;
    PORT
      LAYER M5 ;
        RECT  60.288 0 60.312 0.084 ;
    END
  END d[366]
  PIN d[367]
    DIRECTION INPUT ;
    USE SIGNAL ;
    PORT
      LAYER M5 ;
        RECT  60.432 0 60.456 0.084 ;
    END
  END d[367]
  PIN d[368]
    DIRECTION INPUT ;
    USE SIGNAL ;
    PORT
      LAYER M5 ;
        RECT  60.576 0 60.6 0.084 ;
    END
  END d[368]
  PIN d[369]
    DIRECTION INPUT ;
    USE SIGNAL ;
    PORT
      LAYER M5 ;
        RECT  60.72 0 60.744 0.084 ;
    END
  END d[369]
  PIN d[36]
    DIRECTION INPUT ;
    USE SIGNAL ;
    PORT
      LAYER M5 ;
        RECT  12.48 0 12.504 0.084 ;
    END
  END d[36]
  PIN d[370]
    DIRECTION INPUT ;
    USE SIGNAL ;
    PORT
      LAYER M5 ;
        RECT  60.864 0 60.888 0.084 ;
    END
  END d[370]
  PIN d[371]
    DIRECTION INPUT ;
    USE SIGNAL ;
    PORT
      LAYER M5 ;
        RECT  61.008 0 61.032 0.084 ;
    END
  END d[371]
  PIN d[372]
    DIRECTION INPUT ;
    USE SIGNAL ;
    PORT
      LAYER M5 ;
        RECT  61.152 0 61.176 0.084 ;
    END
  END d[372]
  PIN d[373]
    DIRECTION INPUT ;
    USE SIGNAL ;
    PORT
      LAYER M5 ;
        RECT  61.296 0 61.32 0.084 ;
    END
  END d[373]
  PIN d[374]
    DIRECTION INPUT ;
    USE SIGNAL ;
    PORT
      LAYER M5 ;
        RECT  61.44 0 61.464 0.084 ;
    END
  END d[374]
  PIN d[375]
    DIRECTION INPUT ;
    USE SIGNAL ;
    PORT
      LAYER M5 ;
        RECT  61.584 0 61.608 0.084 ;
    END
  END d[375]
  PIN d[376]
    DIRECTION INPUT ;
    USE SIGNAL ;
    PORT
      LAYER M5 ;
        RECT  61.728 0 61.752 0.084 ;
    END
  END d[376]
  PIN d[377]
    DIRECTION INPUT ;
    USE SIGNAL ;
    PORT
      LAYER M5 ;
        RECT  61.872 0 61.896 0.084 ;
    END
  END d[377]
  PIN d[378]
    DIRECTION INPUT ;
    USE SIGNAL ;
    PORT
      LAYER M5 ;
        RECT  62.016 0 62.04 0.084 ;
    END
  END d[378]
  PIN d[379]
    DIRECTION INPUT ;
    USE SIGNAL ;
    PORT
      LAYER M5 ;
        RECT  62.16 0 62.184 0.084 ;
    END
  END d[379]
  PIN d[37]
    DIRECTION INPUT ;
    USE SIGNAL ;
    PORT
      LAYER M5 ;
        RECT  12.624 0 12.648 0.084 ;
    END
  END d[37]
  PIN d[380]
    DIRECTION INPUT ;
    USE SIGNAL ;
    PORT
      LAYER M5 ;
        RECT  62.304 0 62.328 0.084 ;
    END
  END d[380]
  PIN d[381]
    DIRECTION INPUT ;
    USE SIGNAL ;
    PORT
      LAYER M5 ;
        RECT  62.448 0 62.472 0.084 ;
    END
  END d[381]
  PIN d[382]
    DIRECTION INPUT ;
    USE SIGNAL ;
    PORT
      LAYER M5 ;
        RECT  62.592 0 62.616 0.084 ;
    END
  END d[382]
  PIN d[383]
    DIRECTION INPUT ;
    USE SIGNAL ;
    PORT
      LAYER M5 ;
        RECT  62.736 0 62.76 0.084 ;
    END
  END d[383]
  PIN d[384]
    DIRECTION INPUT ;
    USE SIGNAL ;
    PORT
      LAYER M5 ;
        RECT  62.88 0 62.904 0.084 ;
    END
  END d[384]
  PIN d[385]
    DIRECTION INPUT ;
    USE SIGNAL ;
    PORT
      LAYER M5 ;
        RECT  63.024 0 63.048 0.084 ;
    END
  END d[385]
  PIN d[386]
    DIRECTION INPUT ;
    USE SIGNAL ;
    PORT
      LAYER M5 ;
        RECT  63.168 0 63.192 0.084 ;
    END
  END d[386]
  PIN d[387]
    DIRECTION INPUT ;
    USE SIGNAL ;
    PORT
      LAYER M5 ;
        RECT  63.312 0 63.336 0.084 ;
    END
  END d[387]
  PIN d[388]
    DIRECTION INPUT ;
    USE SIGNAL ;
    PORT
      LAYER M5 ;
        RECT  63.456 0 63.48 0.084 ;
    END
  END d[388]
  PIN d[389]
    DIRECTION INPUT ;
    USE SIGNAL ;
    PORT
      LAYER M5 ;
        RECT  63.6 0 63.624 0.084 ;
    END
  END d[389]
  PIN d[38]
    DIRECTION INPUT ;
    USE SIGNAL ;
    PORT
      LAYER M5 ;
        RECT  12.768 0 12.792 0.084 ;
    END
  END d[38]
  PIN d[390]
    DIRECTION INPUT ;
    USE SIGNAL ;
    PORT
      LAYER M5 ;
        RECT  63.744 0 63.768 0.084 ;
    END
  END d[390]
  PIN d[391]
    DIRECTION INPUT ;
    USE SIGNAL ;
    PORT
      LAYER M5 ;
        RECT  63.888 0 63.912 0.084 ;
    END
  END d[391]
  PIN d[392]
    DIRECTION INPUT ;
    USE SIGNAL ;
    PORT
      LAYER M5 ;
        RECT  64.032 0 64.056 0.084 ;
    END
  END d[392]
  PIN d[393]
    DIRECTION INPUT ;
    USE SIGNAL ;
    PORT
      LAYER M5 ;
        RECT  64.176 0 64.2 0.084 ;
    END
  END d[393]
  PIN d[394]
    DIRECTION INPUT ;
    USE SIGNAL ;
    PORT
      LAYER M5 ;
        RECT  64.32 0 64.344 0.084 ;
    END
  END d[394]
  PIN d[395]
    DIRECTION INPUT ;
    USE SIGNAL ;
    PORT
      LAYER M5 ;
        RECT  64.464 0 64.488 0.084 ;
    END
  END d[395]
  PIN d[396]
    DIRECTION INPUT ;
    USE SIGNAL ;
    PORT
      LAYER M5 ;
        RECT  64.608 0 64.632 0.084 ;
    END
  END d[396]
  PIN d[397]
    DIRECTION INPUT ;
    USE SIGNAL ;
    PORT
      LAYER M5 ;
        RECT  64.752 0 64.776 0.084 ;
    END
  END d[397]
  PIN d[398]
    DIRECTION INPUT ;
    USE SIGNAL ;
    PORT
      LAYER M5 ;
        RECT  64.896 0 64.92 0.084 ;
    END
  END d[398]
  PIN d[399]
    DIRECTION INPUT ;
    USE SIGNAL ;
    PORT
      LAYER M5 ;
        RECT  65.04 0 65.064 0.084 ;
    END
  END d[399]
  PIN d[39]
    DIRECTION INPUT ;
    USE SIGNAL ;
    PORT
      LAYER M5 ;
        RECT  12.912 0 12.936 0.084 ;
    END
  END d[39]
  PIN d[3]
    DIRECTION INPUT ;
    USE SIGNAL ;
    PORT
      LAYER M5 ;
        RECT  7.728 0 7.752 0.084 ;
    END
  END d[3]
  PIN d[400]
    DIRECTION INPUT ;
    USE SIGNAL ;
    PORT
      LAYER M5 ;
        RECT  65.184 0 65.208 0.084 ;
    END
  END d[400]
  PIN d[401]
    DIRECTION INPUT ;
    USE SIGNAL ;
    PORT
      LAYER M5 ;
        RECT  65.328 0 65.352 0.084 ;
    END
  END d[401]
  PIN d[402]
    DIRECTION INPUT ;
    USE SIGNAL ;
    PORT
      LAYER M5 ;
        RECT  65.472 0 65.496 0.084 ;
    END
  END d[402]
  PIN d[403]
    DIRECTION INPUT ;
    USE SIGNAL ;
    PORT
      LAYER M5 ;
        RECT  65.616 0 65.64 0.084 ;
    END
  END d[403]
  PIN d[404]
    DIRECTION INPUT ;
    USE SIGNAL ;
    PORT
      LAYER M5 ;
        RECT  65.76 0 65.784 0.084 ;
    END
  END d[404]
  PIN d[405]
    DIRECTION INPUT ;
    USE SIGNAL ;
    PORT
      LAYER M5 ;
        RECT  65.904 0 65.928 0.084 ;
    END
  END d[405]
  PIN d[406]
    DIRECTION INPUT ;
    USE SIGNAL ;
    PORT
      LAYER M5 ;
        RECT  66.048 0 66.072 0.084 ;
    END
  END d[406]
  PIN d[407]
    DIRECTION INPUT ;
    USE SIGNAL ;
    PORT
      LAYER M5 ;
        RECT  66.192 0 66.216 0.084 ;
    END
  END d[407]
  PIN d[408]
    DIRECTION INPUT ;
    USE SIGNAL ;
    PORT
      LAYER M5 ;
        RECT  66.336 0 66.36 0.084 ;
    END
  END d[408]
  PIN d[409]
    DIRECTION INPUT ;
    USE SIGNAL ;
    PORT
      LAYER M5 ;
        RECT  66.48 0 66.504 0.084 ;
    END
  END d[409]
  PIN d[40]
    DIRECTION INPUT ;
    USE SIGNAL ;
    PORT
      LAYER M5 ;
        RECT  13.056 0 13.08 0.084 ;
    END
  END d[40]
  PIN d[410]
    DIRECTION INPUT ;
    USE SIGNAL ;
    PORT
      LAYER M5 ;
        RECT  66.624 0 66.648 0.084 ;
    END
  END d[410]
  PIN d[411]
    DIRECTION INPUT ;
    USE SIGNAL ;
    PORT
      LAYER M5 ;
        RECT  66.768 0 66.792 0.084 ;
    END
  END d[411]
  PIN d[412]
    DIRECTION INPUT ;
    USE SIGNAL ;
    PORT
      LAYER M5 ;
        RECT  66.912 0 66.936 0.084 ;
    END
  END d[412]
  PIN d[413]
    DIRECTION INPUT ;
    USE SIGNAL ;
    PORT
      LAYER M5 ;
        RECT  67.056 0 67.08 0.084 ;
    END
  END d[413]
  PIN d[414]
    DIRECTION INPUT ;
    USE SIGNAL ;
    PORT
      LAYER M5 ;
        RECT  67.2 0 67.224 0.084 ;
    END
  END d[414]
  PIN d[415]
    DIRECTION INPUT ;
    USE SIGNAL ;
    PORT
      LAYER M5 ;
        RECT  67.344 0 67.368 0.084 ;
    END
  END d[415]
  PIN d[416]
    DIRECTION INPUT ;
    USE SIGNAL ;
    PORT
      LAYER M5 ;
        RECT  67.488 0 67.512 0.084 ;
    END
  END d[416]
  PIN d[417]
    DIRECTION INPUT ;
    USE SIGNAL ;
    PORT
      LAYER M5 ;
        RECT  67.632 0 67.656 0.084 ;
    END
  END d[417]
  PIN d[418]
    DIRECTION INPUT ;
    USE SIGNAL ;
    PORT
      LAYER M5 ;
        RECT  67.776 0 67.8 0.084 ;
    END
  END d[418]
  PIN d[419]
    DIRECTION INPUT ;
    USE SIGNAL ;
    PORT
      LAYER M5 ;
        RECT  67.92 0 67.944 0.084 ;
    END
  END d[419]
  PIN d[41]
    DIRECTION INPUT ;
    USE SIGNAL ;
    PORT
      LAYER M5 ;
        RECT  13.2 0 13.224 0.084 ;
    END
  END d[41]
  PIN d[420]
    DIRECTION INPUT ;
    USE SIGNAL ;
    PORT
      LAYER M5 ;
        RECT  68.064 0 68.088 0.084 ;
    END
  END d[420]
  PIN d[421]
    DIRECTION INPUT ;
    USE SIGNAL ;
    PORT
      LAYER M5 ;
        RECT  68.208 0 68.232 0.084 ;
    END
  END d[421]
  PIN d[422]
    DIRECTION INPUT ;
    USE SIGNAL ;
    PORT
      LAYER M5 ;
        RECT  68.352 0 68.376 0.084 ;
    END
  END d[422]
  PIN d[423]
    DIRECTION INPUT ;
    USE SIGNAL ;
    PORT
      LAYER M5 ;
        RECT  68.496 0 68.52 0.084 ;
    END
  END d[423]
  PIN d[424]
    DIRECTION INPUT ;
    USE SIGNAL ;
    PORT
      LAYER M5 ;
        RECT  68.64 0 68.664 0.084 ;
    END
  END d[424]
  PIN d[425]
    DIRECTION INPUT ;
    USE SIGNAL ;
    PORT
      LAYER M5 ;
        RECT  68.784 0 68.808 0.084 ;
    END
  END d[425]
  PIN d[426]
    DIRECTION INPUT ;
    USE SIGNAL ;
    PORT
      LAYER M5 ;
        RECT  68.928 0 68.952 0.084 ;
    END
  END d[426]
  PIN d[427]
    DIRECTION INPUT ;
    USE SIGNAL ;
    PORT
      LAYER M5 ;
        RECT  69.072 0 69.096 0.084 ;
    END
  END d[427]
  PIN d[428]
    DIRECTION INPUT ;
    USE SIGNAL ;
    PORT
      LAYER M5 ;
        RECT  69.216 0 69.24 0.084 ;
    END
  END d[428]
  PIN d[429]
    DIRECTION INPUT ;
    USE SIGNAL ;
    PORT
      LAYER M5 ;
        RECT  69.36 0 69.384 0.084 ;
    END
  END d[429]
  PIN d[42]
    DIRECTION INPUT ;
    USE SIGNAL ;
    PORT
      LAYER M5 ;
        RECT  13.344 0 13.368 0.084 ;
    END
  END d[42]
  PIN d[430]
    DIRECTION INPUT ;
    USE SIGNAL ;
    PORT
      LAYER M5 ;
        RECT  69.504 0 69.528 0.084 ;
    END
  END d[430]
  PIN d[431]
    DIRECTION INPUT ;
    USE SIGNAL ;
    PORT
      LAYER M5 ;
        RECT  69.648 0 69.672 0.084 ;
    END
  END d[431]
  PIN d[432]
    DIRECTION INPUT ;
    USE SIGNAL ;
    PORT
      LAYER M5 ;
        RECT  69.792 0 69.816 0.084 ;
    END
  END d[432]
  PIN d[433]
    DIRECTION INPUT ;
    USE SIGNAL ;
    PORT
      LAYER M5 ;
        RECT  69.936 0 69.96 0.084 ;
    END
  END d[433]
  PIN d[434]
    DIRECTION INPUT ;
    USE SIGNAL ;
    PORT
      LAYER M5 ;
        RECT  70.08 0 70.104 0.084 ;
    END
  END d[434]
  PIN d[435]
    DIRECTION INPUT ;
    USE SIGNAL ;
    PORT
      LAYER M5 ;
        RECT  70.224 0 70.248 0.084 ;
    END
  END d[435]
  PIN d[436]
    DIRECTION INPUT ;
    USE SIGNAL ;
    PORT
      LAYER M5 ;
        RECT  70.368 0 70.392 0.084 ;
    END
  END d[436]
  PIN d[437]
    DIRECTION INPUT ;
    USE SIGNAL ;
    PORT
      LAYER M5 ;
        RECT  70.512 0 70.536 0.084 ;
    END
  END d[437]
  PIN d[438]
    DIRECTION INPUT ;
    USE SIGNAL ;
    PORT
      LAYER M5 ;
        RECT  70.656 0 70.68 0.084 ;
    END
  END d[438]
  PIN d[439]
    DIRECTION INPUT ;
    USE SIGNAL ;
    PORT
      LAYER M5 ;
        RECT  70.8 0 70.824 0.084 ;
    END
  END d[439]
  PIN d[43]
    DIRECTION INPUT ;
    USE SIGNAL ;
    PORT
      LAYER M5 ;
        RECT  13.488 0 13.512 0.084 ;
    END
  END d[43]
  PIN d[440]
    DIRECTION INPUT ;
    USE SIGNAL ;
    PORT
      LAYER M5 ;
        RECT  70.944 0 70.968 0.084 ;
    END
  END d[440]
  PIN d[441]
    DIRECTION INPUT ;
    USE SIGNAL ;
    PORT
      LAYER M5 ;
        RECT  71.088 0 71.112 0.084 ;
    END
  END d[441]
  PIN d[442]
    DIRECTION INPUT ;
    USE SIGNAL ;
    PORT
      LAYER M5 ;
        RECT  71.232 0 71.256 0.084 ;
    END
  END d[442]
  PIN d[443]
    DIRECTION INPUT ;
    USE SIGNAL ;
    PORT
      LAYER M5 ;
        RECT  71.376 0 71.4 0.084 ;
    END
  END d[443]
  PIN d[444]
    DIRECTION INPUT ;
    USE SIGNAL ;
    PORT
      LAYER M5 ;
        RECT  71.52 0 71.544 0.084 ;
    END
  END d[444]
  PIN d[445]
    DIRECTION INPUT ;
    USE SIGNAL ;
    PORT
      LAYER M5 ;
        RECT  71.664 0 71.688 0.084 ;
    END
  END d[445]
  PIN d[446]
    DIRECTION INPUT ;
    USE SIGNAL ;
    PORT
      LAYER M5 ;
        RECT  71.808 0 71.832 0.084 ;
    END
  END d[446]
  PIN d[447]
    DIRECTION INPUT ;
    USE SIGNAL ;
    PORT
      LAYER M5 ;
        RECT  71.952 0 71.976 0.084 ;
    END
  END d[447]
  PIN d[448]
    DIRECTION INPUT ;
    USE SIGNAL ;
    PORT
      LAYER M5 ;
        RECT  72.096 0 72.12 0.084 ;
    END
  END d[448]
  PIN d[449]
    DIRECTION INPUT ;
    USE SIGNAL ;
    PORT
      LAYER M5 ;
        RECT  72.24 0 72.264 0.084 ;
    END
  END d[449]
  PIN d[44]
    DIRECTION INPUT ;
    USE SIGNAL ;
    PORT
      LAYER M5 ;
        RECT  13.632 0 13.656 0.084 ;
    END
  END d[44]
  PIN d[450]
    DIRECTION INPUT ;
    USE SIGNAL ;
    PORT
      LAYER M5 ;
        RECT  72.384 0 72.408 0.084 ;
    END
  END d[450]
  PIN d[451]
    DIRECTION INPUT ;
    USE SIGNAL ;
    PORT
      LAYER M5 ;
        RECT  72.528 0 72.552 0.084 ;
    END
  END d[451]
  PIN d[452]
    DIRECTION INPUT ;
    USE SIGNAL ;
    PORT
      LAYER M5 ;
        RECT  72.672 0 72.696 0.084 ;
    END
  END d[452]
  PIN d[453]
    DIRECTION INPUT ;
    USE SIGNAL ;
    PORT
      LAYER M5 ;
        RECT  72.816 0 72.84 0.084 ;
    END
  END d[453]
  PIN d[454]
    DIRECTION INPUT ;
    USE SIGNAL ;
    PORT
      LAYER M5 ;
        RECT  72.96 0 72.984 0.084 ;
    END
  END d[454]
  PIN d[455]
    DIRECTION INPUT ;
    USE SIGNAL ;
    PORT
      LAYER M5 ;
        RECT  73.104 0 73.128 0.084 ;
    END
  END d[455]
  PIN d[456]
    DIRECTION INPUT ;
    USE SIGNAL ;
    PORT
      LAYER M5 ;
        RECT  73.248 0 73.272 0.084 ;
    END
  END d[456]
  PIN d[457]
    DIRECTION INPUT ;
    USE SIGNAL ;
    PORT
      LAYER M5 ;
        RECT  73.392 0 73.416 0.084 ;
    END
  END d[457]
  PIN d[458]
    DIRECTION INPUT ;
    USE SIGNAL ;
    PORT
      LAYER M5 ;
        RECT  73.536 0 73.56 0.084 ;
    END
  END d[458]
  PIN d[459]
    DIRECTION INPUT ;
    USE SIGNAL ;
    PORT
      LAYER M5 ;
        RECT  73.68 0 73.704 0.084 ;
    END
  END d[459]
  PIN d[45]
    DIRECTION INPUT ;
    USE SIGNAL ;
    PORT
      LAYER M5 ;
        RECT  13.776 0 13.8 0.084 ;
    END
  END d[45]
  PIN d[460]
    DIRECTION INPUT ;
    USE SIGNAL ;
    PORT
      LAYER M5 ;
        RECT  73.824 0 73.848 0.084 ;
    END
  END d[460]
  PIN d[461]
    DIRECTION INPUT ;
    USE SIGNAL ;
    PORT
      LAYER M5 ;
        RECT  73.968 0 73.992 0.084 ;
    END
  END d[461]
  PIN d[462]
    DIRECTION INPUT ;
    USE SIGNAL ;
    PORT
      LAYER M5 ;
        RECT  74.112 0 74.136 0.084 ;
    END
  END d[462]
  PIN d[463]
    DIRECTION INPUT ;
    USE SIGNAL ;
    PORT
      LAYER M5 ;
        RECT  74.256 0 74.28 0.084 ;
    END
  END d[463]
  PIN d[464]
    DIRECTION INPUT ;
    USE SIGNAL ;
    PORT
      LAYER M5 ;
        RECT  74.4 0 74.424 0.084 ;
    END
  END d[464]
  PIN d[465]
    DIRECTION INPUT ;
    USE SIGNAL ;
    PORT
      LAYER M5 ;
        RECT  74.544 0 74.568 0.084 ;
    END
  END d[465]
  PIN d[466]
    DIRECTION INPUT ;
    USE SIGNAL ;
    PORT
      LAYER M5 ;
        RECT  74.688 0 74.712 0.084 ;
    END
  END d[466]
  PIN d[467]
    DIRECTION INPUT ;
    USE SIGNAL ;
    PORT
      LAYER M5 ;
        RECT  74.832 0 74.856 0.084 ;
    END
  END d[467]
  PIN d[468]
    DIRECTION INPUT ;
    USE SIGNAL ;
    PORT
      LAYER M5 ;
        RECT  74.976 0 75 0.084 ;
    END
  END d[468]
  PIN d[469]
    DIRECTION INPUT ;
    USE SIGNAL ;
    PORT
      LAYER M5 ;
        RECT  75.12 0 75.144 0.084 ;
    END
  END d[469]
  PIN d[46]
    DIRECTION INPUT ;
    USE SIGNAL ;
    PORT
      LAYER M5 ;
        RECT  13.92 0 13.944 0.084 ;
    END
  END d[46]
  PIN d[470]
    DIRECTION INPUT ;
    USE SIGNAL ;
    PORT
      LAYER M5 ;
        RECT  75.264 0 75.288 0.084 ;
    END
  END d[470]
  PIN d[471]
    DIRECTION INPUT ;
    USE SIGNAL ;
    PORT
      LAYER M5 ;
        RECT  75.408 0 75.432 0.084 ;
    END
  END d[471]
  PIN d[472]
    DIRECTION INPUT ;
    USE SIGNAL ;
    PORT
      LAYER M5 ;
        RECT  75.552 0 75.576 0.084 ;
    END
  END d[472]
  PIN d[473]
    DIRECTION INPUT ;
    USE SIGNAL ;
    PORT
      LAYER M5 ;
        RECT  75.696 0 75.72 0.084 ;
    END
  END d[473]
  PIN d[474]
    DIRECTION INPUT ;
    USE SIGNAL ;
    PORT
      LAYER M5 ;
        RECT  75.84 0 75.864 0.084 ;
    END
  END d[474]
  PIN d[475]
    DIRECTION INPUT ;
    USE SIGNAL ;
    PORT
      LAYER M5 ;
        RECT  75.984 0 76.008 0.084 ;
    END
  END d[475]
  PIN d[476]
    DIRECTION INPUT ;
    USE SIGNAL ;
    PORT
      LAYER M5 ;
        RECT  76.128 0 76.152 0.084 ;
    END
  END d[476]
  PIN d[477]
    DIRECTION INPUT ;
    USE SIGNAL ;
    PORT
      LAYER M5 ;
        RECT  76.272 0 76.296 0.084 ;
    END
  END d[477]
  PIN d[478]
    DIRECTION INPUT ;
    USE SIGNAL ;
    PORT
      LAYER M5 ;
        RECT  76.416 0 76.44 0.084 ;
    END
  END d[478]
  PIN d[479]
    DIRECTION INPUT ;
    USE SIGNAL ;
    PORT
      LAYER M5 ;
        RECT  76.56 0 76.584 0.084 ;
    END
  END d[479]
  PIN d[47]
    DIRECTION INPUT ;
    USE SIGNAL ;
    PORT
      LAYER M5 ;
        RECT  14.064 0 14.088 0.084 ;
    END
  END d[47]
  PIN d[480]
    DIRECTION INPUT ;
    USE SIGNAL ;
    PORT
      LAYER M5 ;
        RECT  76.704 0 76.728 0.084 ;
    END
  END d[480]
  PIN d[481]
    DIRECTION INPUT ;
    USE SIGNAL ;
    PORT
      LAYER M5 ;
        RECT  76.848 0 76.872 0.084 ;
    END
  END d[481]
  PIN d[482]
    DIRECTION INPUT ;
    USE SIGNAL ;
    PORT
      LAYER M5 ;
        RECT  76.992 0 77.016 0.084 ;
    END
  END d[482]
  PIN d[483]
    DIRECTION INPUT ;
    USE SIGNAL ;
    PORT
      LAYER M5 ;
        RECT  77.136 0 77.16 0.084 ;
    END
  END d[483]
  PIN d[484]
    DIRECTION INPUT ;
    USE SIGNAL ;
    PORT
      LAYER M5 ;
        RECT  77.28 0 77.304 0.084 ;
    END
  END d[484]
  PIN d[485]
    DIRECTION INPUT ;
    USE SIGNAL ;
    PORT
      LAYER M5 ;
        RECT  77.424 0 77.448 0.084 ;
    END
  END d[485]
  PIN d[486]
    DIRECTION INPUT ;
    USE SIGNAL ;
    PORT
      LAYER M5 ;
        RECT  77.568 0 77.592 0.084 ;
    END
  END d[486]
  PIN d[487]
    DIRECTION INPUT ;
    USE SIGNAL ;
    PORT
      LAYER M5 ;
        RECT  77.712 0 77.736 0.084 ;
    END
  END d[487]
  PIN d[488]
    DIRECTION INPUT ;
    USE SIGNAL ;
    PORT
      LAYER M5 ;
        RECT  77.856 0 77.88 0.084 ;
    END
  END d[488]
  PIN d[489]
    DIRECTION INPUT ;
    USE SIGNAL ;
    PORT
      LAYER M5 ;
        RECT  78 0 78.024 0.084 ;
    END
  END d[489]
  PIN d[48]
    DIRECTION INPUT ;
    USE SIGNAL ;
    PORT
      LAYER M5 ;
        RECT  14.208 0 14.232 0.084 ;
    END
  END d[48]
  PIN d[490]
    DIRECTION INPUT ;
    USE SIGNAL ;
    PORT
      LAYER M5 ;
        RECT  78.144 0 78.168 0.084 ;
    END
  END d[490]
  PIN d[491]
    DIRECTION INPUT ;
    USE SIGNAL ;
    PORT
      LAYER M5 ;
        RECT  78.288 0 78.312 0.084 ;
    END
  END d[491]
  PIN d[492]
    DIRECTION INPUT ;
    USE SIGNAL ;
    PORT
      LAYER M5 ;
        RECT  78.432 0 78.456 0.084 ;
    END
  END d[492]
  PIN d[493]
    DIRECTION INPUT ;
    USE SIGNAL ;
    PORT
      LAYER M5 ;
        RECT  78.576 0 78.6 0.084 ;
    END
  END d[493]
  PIN d[494]
    DIRECTION INPUT ;
    USE SIGNAL ;
    PORT
      LAYER M5 ;
        RECT  78.72 0 78.744 0.084 ;
    END
  END d[494]
  PIN d[495]
    DIRECTION INPUT ;
    USE SIGNAL ;
    PORT
      LAYER M5 ;
        RECT  78.864 0 78.888 0.084 ;
    END
  END d[495]
  PIN d[496]
    DIRECTION INPUT ;
    USE SIGNAL ;
    PORT
      LAYER M5 ;
        RECT  79.008 0 79.032 0.084 ;
    END
  END d[496]
  PIN d[497]
    DIRECTION INPUT ;
    USE SIGNAL ;
    PORT
      LAYER M5 ;
        RECT  79.152 0 79.176 0.084 ;
    END
  END d[497]
  PIN d[498]
    DIRECTION INPUT ;
    USE SIGNAL ;
    PORT
      LAYER M5 ;
        RECT  79.296 0 79.32 0.084 ;
    END
  END d[498]
  PIN d[499]
    DIRECTION INPUT ;
    USE SIGNAL ;
    PORT
      LAYER M5 ;
        RECT  79.44 0 79.464 0.084 ;
    END
  END d[499]
  PIN d[49]
    DIRECTION INPUT ;
    USE SIGNAL ;
    PORT
      LAYER M5 ;
        RECT  14.352 0 14.376 0.084 ;
    END
  END d[49]
  PIN d[4]
    DIRECTION INPUT ;
    USE SIGNAL ;
    PORT
      LAYER M5 ;
        RECT  7.872 0 7.896 0.084 ;
    END
  END d[4]
  PIN d[500]
    DIRECTION INPUT ;
    USE SIGNAL ;
    PORT
      LAYER M5 ;
        RECT  79.584 0 79.608 0.084 ;
    END
  END d[500]
  PIN d[501]
    DIRECTION INPUT ;
    USE SIGNAL ;
    PORT
      LAYER M5 ;
        RECT  79.728 0 79.752 0.084 ;
    END
  END d[501]
  PIN d[502]
    DIRECTION INPUT ;
    USE SIGNAL ;
    PORT
      LAYER M5 ;
        RECT  79.872 0 79.896 0.084 ;
    END
  END d[502]
  PIN d[503]
    DIRECTION INPUT ;
    USE SIGNAL ;
    PORT
      LAYER M5 ;
        RECT  80.016 0 80.04 0.084 ;
    END
  END d[503]
  PIN d[504]
    DIRECTION INPUT ;
    USE SIGNAL ;
    PORT
      LAYER M5 ;
        RECT  80.16 0 80.184 0.084 ;
    END
  END d[504]
  PIN d[505]
    DIRECTION INPUT ;
    USE SIGNAL ;
    PORT
      LAYER M5 ;
        RECT  80.304 0 80.328 0.084 ;
    END
  END d[505]
  PIN d[506]
    DIRECTION INPUT ;
    USE SIGNAL ;
    PORT
      LAYER M5 ;
        RECT  80.448 0 80.472 0.084 ;
    END
  END d[506]
  PIN d[507]
    DIRECTION INPUT ;
    USE SIGNAL ;
    PORT
      LAYER M5 ;
        RECT  80.592 0 80.616 0.084 ;
    END
  END d[507]
  PIN d[508]
    DIRECTION INPUT ;
    USE SIGNAL ;
    PORT
      LAYER M5 ;
        RECT  80.736 0 80.76 0.084 ;
    END
  END d[508]
  PIN d[509]
    DIRECTION INPUT ;
    USE SIGNAL ;
    PORT
      LAYER M5 ;
        RECT  80.88 0 80.904 0.084 ;
    END
  END d[509]
  PIN d[50]
    DIRECTION INPUT ;
    USE SIGNAL ;
    PORT
      LAYER M5 ;
        RECT  14.496 0 14.52 0.084 ;
    END
  END d[50]
  PIN d[510]
    DIRECTION INPUT ;
    USE SIGNAL ;
    PORT
      LAYER M5 ;
        RECT  81.024 0 81.048 0.084 ;
    END
  END d[510]
  PIN d[511]
    DIRECTION INPUT ;
    USE SIGNAL ;
    PORT
      LAYER M5 ;
        RECT  81.168 0 81.192 0.084 ;
    END
  END d[511]
  PIN d[512]
    DIRECTION INPUT ;
    USE SIGNAL ;
    PORT
      LAYER M5 ;
        RECT  81.312 0 81.336 0.084 ;
    END
  END d[512]
  PIN d[513]
    DIRECTION INPUT ;
    USE SIGNAL ;
    PORT
      LAYER M5 ;
        RECT  81.456 0 81.48 0.084 ;
    END
  END d[513]
  PIN d[514]
    DIRECTION INPUT ;
    USE SIGNAL ;
    PORT
      LAYER M5 ;
        RECT  81.6 0 81.624 0.084 ;
    END
  END d[514]
  PIN d[515]
    DIRECTION INPUT ;
    USE SIGNAL ;
    PORT
      LAYER M5 ;
        RECT  81.744 0 81.768 0.084 ;
    END
  END d[515]
  PIN d[516]
    DIRECTION INPUT ;
    USE SIGNAL ;
    PORT
      LAYER M5 ;
        RECT  81.888 0 81.912 0.084 ;
    END
  END d[516]
  PIN d[51]
    DIRECTION INPUT ;
    USE SIGNAL ;
    PORT
      LAYER M5 ;
        RECT  14.64 0 14.664 0.084 ;
    END
  END d[51]
  PIN d[52]
    DIRECTION INPUT ;
    USE SIGNAL ;
    PORT
      LAYER M5 ;
        RECT  14.784 0 14.808 0.084 ;
    END
  END d[52]
  PIN d[53]
    DIRECTION INPUT ;
    USE SIGNAL ;
    PORT
      LAYER M5 ;
        RECT  14.928 0 14.952 0.084 ;
    END
  END d[53]
  PIN d[54]
    DIRECTION INPUT ;
    USE SIGNAL ;
    PORT
      LAYER M5 ;
        RECT  15.072 0 15.096 0.084 ;
    END
  END d[54]
  PIN d[55]
    DIRECTION INPUT ;
    USE SIGNAL ;
    PORT
      LAYER M5 ;
        RECT  15.216 0 15.24 0.084 ;
    END
  END d[55]
  PIN d[56]
    DIRECTION INPUT ;
    USE SIGNAL ;
    PORT
      LAYER M5 ;
        RECT  15.36 0 15.384 0.084 ;
    END
  END d[56]
  PIN d[57]
    DIRECTION INPUT ;
    USE SIGNAL ;
    PORT
      LAYER M5 ;
        RECT  15.504 0 15.528 0.084 ;
    END
  END d[57]
  PIN d[58]
    DIRECTION INPUT ;
    USE SIGNAL ;
    PORT
      LAYER M5 ;
        RECT  15.648 0 15.672 0.084 ;
    END
  END d[58]
  PIN d[59]
    DIRECTION INPUT ;
    USE SIGNAL ;
    PORT
      LAYER M5 ;
        RECT  15.792 0 15.816 0.084 ;
    END
  END d[59]
  PIN d[5]
    DIRECTION INPUT ;
    USE SIGNAL ;
    PORT
      LAYER M5 ;
        RECT  8.016 0 8.04 0.084 ;
    END
  END d[5]
  PIN d[60]
    DIRECTION INPUT ;
    USE SIGNAL ;
    PORT
      LAYER M5 ;
        RECT  15.936 0 15.96 0.084 ;
    END
  END d[60]
  PIN d[61]
    DIRECTION INPUT ;
    USE SIGNAL ;
    PORT
      LAYER M5 ;
        RECT  16.08 0 16.104 0.084 ;
    END
  END d[61]
  PIN d[62]
    DIRECTION INPUT ;
    USE SIGNAL ;
    PORT
      LAYER M5 ;
        RECT  16.224 0 16.248 0.084 ;
    END
  END d[62]
  PIN d[63]
    DIRECTION INPUT ;
    USE SIGNAL ;
    PORT
      LAYER M5 ;
        RECT  16.368 0 16.392 0.084 ;
    END
  END d[63]
  PIN d[64]
    DIRECTION INPUT ;
    USE SIGNAL ;
    PORT
      LAYER M5 ;
        RECT  16.512 0 16.536 0.084 ;
    END
  END d[64]
  PIN d[65]
    DIRECTION INPUT ;
    USE SIGNAL ;
    PORT
      LAYER M5 ;
        RECT  16.656 0 16.68 0.084 ;
    END
  END d[65]
  PIN d[66]
    DIRECTION INPUT ;
    USE SIGNAL ;
    PORT
      LAYER M5 ;
        RECT  16.8 0 16.824 0.084 ;
    END
  END d[66]
  PIN d[67]
    DIRECTION INPUT ;
    USE SIGNAL ;
    PORT
      LAYER M5 ;
        RECT  16.944 0 16.968 0.084 ;
    END
  END d[67]
  PIN d[68]
    DIRECTION INPUT ;
    USE SIGNAL ;
    PORT
      LAYER M5 ;
        RECT  17.088 0 17.112 0.084 ;
    END
  END d[68]
  PIN d[69]
    DIRECTION INPUT ;
    USE SIGNAL ;
    PORT
      LAYER M5 ;
        RECT  17.232 0 17.256 0.084 ;
    END
  END d[69]
  PIN d[6]
    DIRECTION INPUT ;
    USE SIGNAL ;
    PORT
      LAYER M5 ;
        RECT  8.16 0 8.184 0.084 ;
    END
  END d[6]
  PIN d[70]
    DIRECTION INPUT ;
    USE SIGNAL ;
    PORT
      LAYER M5 ;
        RECT  17.376 0 17.4 0.084 ;
    END
  END d[70]
  PIN d[71]
    DIRECTION INPUT ;
    USE SIGNAL ;
    PORT
      LAYER M5 ;
        RECT  17.52 0 17.544 0.084 ;
    END
  END d[71]
  PIN d[72]
    DIRECTION INPUT ;
    USE SIGNAL ;
    PORT
      LAYER M5 ;
        RECT  17.664 0 17.688 0.084 ;
    END
  END d[72]
  PIN d[73]
    DIRECTION INPUT ;
    USE SIGNAL ;
    PORT
      LAYER M5 ;
        RECT  17.808 0 17.832 0.084 ;
    END
  END d[73]
  PIN d[74]
    DIRECTION INPUT ;
    USE SIGNAL ;
    PORT
      LAYER M5 ;
        RECT  17.952 0 17.976 0.084 ;
    END
  END d[74]
  PIN d[75]
    DIRECTION INPUT ;
    USE SIGNAL ;
    PORT
      LAYER M5 ;
        RECT  18.096 0 18.12 0.084 ;
    END
  END d[75]
  PIN d[76]
    DIRECTION INPUT ;
    USE SIGNAL ;
    PORT
      LAYER M5 ;
        RECT  18.24 0 18.264 0.084 ;
    END
  END d[76]
  PIN d[77]
    DIRECTION INPUT ;
    USE SIGNAL ;
    PORT
      LAYER M5 ;
        RECT  18.384 0 18.408 0.084 ;
    END
  END d[77]
  PIN d[78]
    DIRECTION INPUT ;
    USE SIGNAL ;
    PORT
      LAYER M5 ;
        RECT  18.528 0 18.552 0.084 ;
    END
  END d[78]
  PIN d[79]
    DIRECTION INPUT ;
    USE SIGNAL ;
    PORT
      LAYER M5 ;
        RECT  18.672 0 18.696 0.084 ;
    END
  END d[79]
  PIN d[7]
    DIRECTION INPUT ;
    USE SIGNAL ;
    PORT
      LAYER M5 ;
        RECT  8.304 0 8.328 0.084 ;
    END
  END d[7]
  PIN d[80]
    DIRECTION INPUT ;
    USE SIGNAL ;
    PORT
      LAYER M5 ;
        RECT  18.816 0 18.84 0.084 ;
    END
  END d[80]
  PIN d[81]
    DIRECTION INPUT ;
    USE SIGNAL ;
    PORT
      LAYER M5 ;
        RECT  18.96 0 18.984 0.084 ;
    END
  END d[81]
  PIN d[82]
    DIRECTION INPUT ;
    USE SIGNAL ;
    PORT
      LAYER M5 ;
        RECT  19.104 0 19.128 0.084 ;
    END
  END d[82]
  PIN d[83]
    DIRECTION INPUT ;
    USE SIGNAL ;
    PORT
      LAYER M5 ;
        RECT  19.248 0 19.272 0.084 ;
    END
  END d[83]
  PIN d[84]
    DIRECTION INPUT ;
    USE SIGNAL ;
    PORT
      LAYER M5 ;
        RECT  19.392 0 19.416 0.084 ;
    END
  END d[84]
  PIN d[85]
    DIRECTION INPUT ;
    USE SIGNAL ;
    PORT
      LAYER M5 ;
        RECT  19.536 0 19.56 0.084 ;
    END
  END d[85]
  PIN d[86]
    DIRECTION INPUT ;
    USE SIGNAL ;
    PORT
      LAYER M5 ;
        RECT  19.68 0 19.704 0.084 ;
    END
  END d[86]
  PIN d[87]
    DIRECTION INPUT ;
    USE SIGNAL ;
    PORT
      LAYER M5 ;
        RECT  19.824 0 19.848 0.084 ;
    END
  END d[87]
  PIN d[88]
    DIRECTION INPUT ;
    USE SIGNAL ;
    PORT
      LAYER M5 ;
        RECT  19.968 0 19.992 0.084 ;
    END
  END d[88]
  PIN d[89]
    DIRECTION INPUT ;
    USE SIGNAL ;
    PORT
      LAYER M5 ;
        RECT  20.112 0 20.136 0.084 ;
    END
  END d[89]
  PIN d[8]
    DIRECTION INPUT ;
    USE SIGNAL ;
    PORT
      LAYER M5 ;
        RECT  8.448 0 8.472 0.084 ;
    END
  END d[8]
  PIN d[90]
    DIRECTION INPUT ;
    USE SIGNAL ;
    PORT
      LAYER M5 ;
        RECT  20.256 0 20.28 0.084 ;
    END
  END d[90]
  PIN d[91]
    DIRECTION INPUT ;
    USE SIGNAL ;
    PORT
      LAYER M5 ;
        RECT  20.4 0 20.424 0.084 ;
    END
  END d[91]
  PIN d[92]
    DIRECTION INPUT ;
    USE SIGNAL ;
    PORT
      LAYER M5 ;
        RECT  20.544 0 20.568 0.084 ;
    END
  END d[92]
  PIN d[93]
    DIRECTION INPUT ;
    USE SIGNAL ;
    PORT
      LAYER M5 ;
        RECT  20.688 0 20.712 0.084 ;
    END
  END d[93]
  PIN d[94]
    DIRECTION INPUT ;
    USE SIGNAL ;
    PORT
      LAYER M5 ;
        RECT  20.832 0 20.856 0.084 ;
    END
  END d[94]
  PIN d[95]
    DIRECTION INPUT ;
    USE SIGNAL ;
    PORT
      LAYER M5 ;
        RECT  20.976 0 21 0.084 ;
    END
  END d[95]
  PIN d[96]
    DIRECTION INPUT ;
    USE SIGNAL ;
    PORT
      LAYER M5 ;
        RECT  21.12 0 21.144 0.084 ;
    END
  END d[96]
  PIN d[97]
    DIRECTION INPUT ;
    USE SIGNAL ;
    PORT
      LAYER M5 ;
        RECT  21.264 0 21.288 0.084 ;
    END
  END d[97]
  PIN d[98]
    DIRECTION INPUT ;
    USE SIGNAL ;
    PORT
      LAYER M5 ;
        RECT  21.408 0 21.432 0.084 ;
    END
  END d[98]
  PIN d[99]
    DIRECTION INPUT ;
    USE SIGNAL ;
    PORT
      LAYER M5 ;
        RECT  21.552 0 21.576 0.084 ;
    END
  END d[99]
  PIN d[9]
    DIRECTION INPUT ;
    USE SIGNAL ;
    PORT
      LAYER M5 ;
        RECT  8.592 0 8.616 0.084 ;
    END
  END d[9]
  PIN fault
    DIRECTION OUTPUT ;
    USE SIGNAL ;
    PORT
      LAYER M5 ;
        RECT  44.304 51.756 44.328 51.84 ;
    END
  END fault
  PIN fclk
    DIRECTION INPUT ;
    USE SIGNAL ;
    PORT
      LAYER M5 ;
        RECT  44.448 0 44.472 0.084 ;
    END
  END fclk
  PIN q[0]
    DIRECTION OUTPUT ;
    USE SIGNAL ;
    PORT
      LAYER M5 ;
        RECT  6.72 51.756 6.744 51.84 ;
    END
  END q[0]
  PIN q[100]
    DIRECTION OUTPUT ;
    USE SIGNAL ;
    PORT
      LAYER M5 ;
        RECT  21.12 51.756 21.144 51.84 ;
    END
  END q[100]
  PIN q[101]
    DIRECTION OUTPUT ;
    USE SIGNAL ;
    PORT
      LAYER M5 ;
        RECT  21.264 51.756 21.288 51.84 ;
    END
  END q[101]
  PIN q[102]
    DIRECTION OUTPUT ;
    USE SIGNAL ;
    PORT
      LAYER M5 ;
        RECT  21.408 51.756 21.432 51.84 ;
    END
  END q[102]
  PIN q[103]
    DIRECTION OUTPUT ;
    USE SIGNAL ;
    PORT
      LAYER M5 ;
        RECT  21.552 51.756 21.576 51.84 ;
    END
  END q[103]
  PIN q[104]
    DIRECTION OUTPUT ;
    USE SIGNAL ;
    PORT
      LAYER M5 ;
        RECT  21.696 51.756 21.72 51.84 ;
    END
  END q[104]
  PIN q[105]
    DIRECTION OUTPUT ;
    USE SIGNAL ;
    PORT
      LAYER M5 ;
        RECT  21.84 51.756 21.864 51.84 ;
    END
  END q[105]
  PIN q[106]
    DIRECTION OUTPUT ;
    USE SIGNAL ;
    PORT
      LAYER M5 ;
        RECT  21.984 51.756 22.008 51.84 ;
    END
  END q[106]
  PIN q[107]
    DIRECTION OUTPUT ;
    USE SIGNAL ;
    PORT
      LAYER M5 ;
        RECT  22.128 51.756 22.152 51.84 ;
    END
  END q[107]
  PIN q[108]
    DIRECTION OUTPUT ;
    USE SIGNAL ;
    PORT
      LAYER M5 ;
        RECT  22.272 51.756 22.296 51.84 ;
    END
  END q[108]
  PIN q[109]
    DIRECTION OUTPUT ;
    USE SIGNAL ;
    PORT
      LAYER M5 ;
        RECT  22.416 51.756 22.44 51.84 ;
    END
  END q[109]
  PIN q[10]
    DIRECTION OUTPUT ;
    USE SIGNAL ;
    PORT
      LAYER M5 ;
        RECT  8.16 51.756 8.184 51.84 ;
    END
  END q[10]
  PIN q[110]
    DIRECTION OUTPUT ;
    USE SIGNAL ;
    PORT
      LAYER M5 ;
        RECT  22.56 51.756 22.584 51.84 ;
    END
  END q[110]
  PIN q[111]
    DIRECTION OUTPUT ;
    USE SIGNAL ;
    PORT
      LAYER M5 ;
        RECT  22.704 51.756 22.728 51.84 ;
    END
  END q[111]
  PIN q[112]
    DIRECTION OUTPUT ;
    USE SIGNAL ;
    PORT
      LAYER M5 ;
        RECT  22.848 51.756 22.872 51.84 ;
    END
  END q[112]
  PIN q[113]
    DIRECTION OUTPUT ;
    USE SIGNAL ;
    PORT
      LAYER M5 ;
        RECT  22.992 51.756 23.016 51.84 ;
    END
  END q[113]
  PIN q[114]
    DIRECTION OUTPUT ;
    USE SIGNAL ;
    PORT
      LAYER M5 ;
        RECT  23.136 51.756 23.16 51.84 ;
    END
  END q[114]
  PIN q[115]
    DIRECTION OUTPUT ;
    USE SIGNAL ;
    PORT
      LAYER M5 ;
        RECT  23.28 51.756 23.304 51.84 ;
    END
  END q[115]
  PIN q[116]
    DIRECTION OUTPUT ;
    USE SIGNAL ;
    PORT
      LAYER M5 ;
        RECT  23.424 51.756 23.448 51.84 ;
    END
  END q[116]
  PIN q[117]
    DIRECTION OUTPUT ;
    USE SIGNAL ;
    PORT
      LAYER M5 ;
        RECT  23.568 51.756 23.592 51.84 ;
    END
  END q[117]
  PIN q[118]
    DIRECTION OUTPUT ;
    USE SIGNAL ;
    PORT
      LAYER M5 ;
        RECT  23.712 51.756 23.736 51.84 ;
    END
  END q[118]
  PIN q[119]
    DIRECTION OUTPUT ;
    USE SIGNAL ;
    PORT
      LAYER M5 ;
        RECT  23.856 51.756 23.88 51.84 ;
    END
  END q[119]
  PIN q[11]
    DIRECTION OUTPUT ;
    USE SIGNAL ;
    PORT
      LAYER M5 ;
        RECT  8.304 51.756 8.328 51.84 ;
    END
  END q[11]
  PIN q[120]
    DIRECTION OUTPUT ;
    USE SIGNAL ;
    PORT
      LAYER M5 ;
        RECT  24 51.756 24.024 51.84 ;
    END
  END q[120]
  PIN q[121]
    DIRECTION OUTPUT ;
    USE SIGNAL ;
    PORT
      LAYER M5 ;
        RECT  24.144 51.756 24.168 51.84 ;
    END
  END q[121]
  PIN q[122]
    DIRECTION OUTPUT ;
    USE SIGNAL ;
    PORT
      LAYER M5 ;
        RECT  24.288 51.756 24.312 51.84 ;
    END
  END q[122]
  PIN q[123]
    DIRECTION OUTPUT ;
    USE SIGNAL ;
    PORT
      LAYER M5 ;
        RECT  24.432 51.756 24.456 51.84 ;
    END
  END q[123]
  PIN q[124]
    DIRECTION OUTPUT ;
    USE SIGNAL ;
    PORT
      LAYER M5 ;
        RECT  24.576 51.756 24.6 51.84 ;
    END
  END q[124]
  PIN q[125]
    DIRECTION OUTPUT ;
    USE SIGNAL ;
    PORT
      LAYER M5 ;
        RECT  24.72 51.756 24.744 51.84 ;
    END
  END q[125]
  PIN q[126]
    DIRECTION OUTPUT ;
    USE SIGNAL ;
    PORT
      LAYER M5 ;
        RECT  24.864 51.756 24.888 51.84 ;
    END
  END q[126]
  PIN q[127]
    DIRECTION OUTPUT ;
    USE SIGNAL ;
    PORT
      LAYER M5 ;
        RECT  25.008 51.756 25.032 51.84 ;
    END
  END q[127]
  PIN q[128]
    DIRECTION OUTPUT ;
    USE SIGNAL ;
    PORT
      LAYER M5 ;
        RECT  25.152 51.756 25.176 51.84 ;
    END
  END q[128]
  PIN q[129]
    DIRECTION OUTPUT ;
    USE SIGNAL ;
    PORT
      LAYER M5 ;
        RECT  25.296 51.756 25.32 51.84 ;
    END
  END q[129]
  PIN q[12]
    DIRECTION OUTPUT ;
    USE SIGNAL ;
    PORT
      LAYER M5 ;
        RECT  8.448 51.756 8.472 51.84 ;
    END
  END q[12]
  PIN q[130]
    DIRECTION OUTPUT ;
    USE SIGNAL ;
    PORT
      LAYER M5 ;
        RECT  25.44 51.756 25.464 51.84 ;
    END
  END q[130]
  PIN q[131]
    DIRECTION OUTPUT ;
    USE SIGNAL ;
    PORT
      LAYER M5 ;
        RECT  25.584 51.756 25.608 51.84 ;
    END
  END q[131]
  PIN q[132]
    DIRECTION OUTPUT ;
    USE SIGNAL ;
    PORT
      LAYER M5 ;
        RECT  25.728 51.756 25.752 51.84 ;
    END
  END q[132]
  PIN q[133]
    DIRECTION OUTPUT ;
    USE SIGNAL ;
    PORT
      LAYER M5 ;
        RECT  25.872 51.756 25.896 51.84 ;
    END
  END q[133]
  PIN q[134]
    DIRECTION OUTPUT ;
    USE SIGNAL ;
    PORT
      LAYER M5 ;
        RECT  26.016 51.756 26.04 51.84 ;
    END
  END q[134]
  PIN q[135]
    DIRECTION OUTPUT ;
    USE SIGNAL ;
    PORT
      LAYER M5 ;
        RECT  26.16 51.756 26.184 51.84 ;
    END
  END q[135]
  PIN q[136]
    DIRECTION OUTPUT ;
    USE SIGNAL ;
    PORT
      LAYER M5 ;
        RECT  26.304 51.756 26.328 51.84 ;
    END
  END q[136]
  PIN q[137]
    DIRECTION OUTPUT ;
    USE SIGNAL ;
    PORT
      LAYER M5 ;
        RECT  26.448 51.756 26.472 51.84 ;
    END
  END q[137]
  PIN q[138]
    DIRECTION OUTPUT ;
    USE SIGNAL ;
    PORT
      LAYER M5 ;
        RECT  26.592 51.756 26.616 51.84 ;
    END
  END q[138]
  PIN q[139]
    DIRECTION OUTPUT ;
    USE SIGNAL ;
    PORT
      LAYER M5 ;
        RECT  26.736 51.756 26.76 51.84 ;
    END
  END q[139]
  PIN q[13]
    DIRECTION OUTPUT ;
    USE SIGNAL ;
    PORT
      LAYER M5 ;
        RECT  8.592 51.756 8.616 51.84 ;
    END
  END q[13]
  PIN q[140]
    DIRECTION OUTPUT ;
    USE SIGNAL ;
    PORT
      LAYER M5 ;
        RECT  26.88 51.756 26.904 51.84 ;
    END
  END q[140]
  PIN q[141]
    DIRECTION OUTPUT ;
    USE SIGNAL ;
    PORT
      LAYER M5 ;
        RECT  27.024 51.756 27.048 51.84 ;
    END
  END q[141]
  PIN q[142]
    DIRECTION OUTPUT ;
    USE SIGNAL ;
    PORT
      LAYER M5 ;
        RECT  27.168 51.756 27.192 51.84 ;
    END
  END q[142]
  PIN q[143]
    DIRECTION OUTPUT ;
    USE SIGNAL ;
    PORT
      LAYER M5 ;
        RECT  27.312 51.756 27.336 51.84 ;
    END
  END q[143]
  PIN q[144]
    DIRECTION OUTPUT ;
    USE SIGNAL ;
    PORT
      LAYER M5 ;
        RECT  27.456 51.756 27.48 51.84 ;
    END
  END q[144]
  PIN q[145]
    DIRECTION OUTPUT ;
    USE SIGNAL ;
    PORT
      LAYER M5 ;
        RECT  27.6 51.756 27.624 51.84 ;
    END
  END q[145]
  PIN q[146]
    DIRECTION OUTPUT ;
    USE SIGNAL ;
    PORT
      LAYER M5 ;
        RECT  27.744 51.756 27.768 51.84 ;
    END
  END q[146]
  PIN q[147]
    DIRECTION OUTPUT ;
    USE SIGNAL ;
    PORT
      LAYER M5 ;
        RECT  27.888 51.756 27.912 51.84 ;
    END
  END q[147]
  PIN q[148]
    DIRECTION OUTPUT ;
    USE SIGNAL ;
    PORT
      LAYER M5 ;
        RECT  28.032 51.756 28.056 51.84 ;
    END
  END q[148]
  PIN q[149]
    DIRECTION OUTPUT ;
    USE SIGNAL ;
    PORT
      LAYER M5 ;
        RECT  28.176 51.756 28.2 51.84 ;
    END
  END q[149]
  PIN q[14]
    DIRECTION OUTPUT ;
    USE SIGNAL ;
    PORT
      LAYER M5 ;
        RECT  8.736 51.756 8.76 51.84 ;
    END
  END q[14]
  PIN q[150]
    DIRECTION OUTPUT ;
    USE SIGNAL ;
    PORT
      LAYER M5 ;
        RECT  28.32 51.756 28.344 51.84 ;
    END
  END q[150]
  PIN q[151]
    DIRECTION OUTPUT ;
    USE SIGNAL ;
    PORT
      LAYER M5 ;
        RECT  28.464 51.756 28.488 51.84 ;
    END
  END q[151]
  PIN q[152]
    DIRECTION OUTPUT ;
    USE SIGNAL ;
    PORT
      LAYER M5 ;
        RECT  28.608 51.756 28.632 51.84 ;
    END
  END q[152]
  PIN q[153]
    DIRECTION OUTPUT ;
    USE SIGNAL ;
    PORT
      LAYER M5 ;
        RECT  28.752 51.756 28.776 51.84 ;
    END
  END q[153]
  PIN q[154]
    DIRECTION OUTPUT ;
    USE SIGNAL ;
    PORT
      LAYER M5 ;
        RECT  28.896 51.756 28.92 51.84 ;
    END
  END q[154]
  PIN q[155]
    DIRECTION OUTPUT ;
    USE SIGNAL ;
    PORT
      LAYER M5 ;
        RECT  29.04 51.756 29.064 51.84 ;
    END
  END q[155]
  PIN q[156]
    DIRECTION OUTPUT ;
    USE SIGNAL ;
    PORT
      LAYER M5 ;
        RECT  29.184 51.756 29.208 51.84 ;
    END
  END q[156]
  PIN q[157]
    DIRECTION OUTPUT ;
    USE SIGNAL ;
    PORT
      LAYER M5 ;
        RECT  29.328 51.756 29.352 51.84 ;
    END
  END q[157]
  PIN q[158]
    DIRECTION OUTPUT ;
    USE SIGNAL ;
    PORT
      LAYER M5 ;
        RECT  29.472 51.756 29.496 51.84 ;
    END
  END q[158]
  PIN q[159]
    DIRECTION OUTPUT ;
    USE SIGNAL ;
    PORT
      LAYER M5 ;
        RECT  29.616 51.756 29.64 51.84 ;
    END
  END q[159]
  PIN q[15]
    DIRECTION OUTPUT ;
    USE SIGNAL ;
    PORT
      LAYER M5 ;
        RECT  8.88 51.756 8.904 51.84 ;
    END
  END q[15]
  PIN q[160]
    DIRECTION OUTPUT ;
    USE SIGNAL ;
    PORT
      LAYER M5 ;
        RECT  29.76 51.756 29.784 51.84 ;
    END
  END q[160]
  PIN q[161]
    DIRECTION OUTPUT ;
    USE SIGNAL ;
    PORT
      LAYER M5 ;
        RECT  29.904 51.756 29.928 51.84 ;
    END
  END q[161]
  PIN q[162]
    DIRECTION OUTPUT ;
    USE SIGNAL ;
    PORT
      LAYER M5 ;
        RECT  30.048 51.756 30.072 51.84 ;
    END
  END q[162]
  PIN q[163]
    DIRECTION OUTPUT ;
    USE SIGNAL ;
    PORT
      LAYER M5 ;
        RECT  30.192 51.756 30.216 51.84 ;
    END
  END q[163]
  PIN q[164]
    DIRECTION OUTPUT ;
    USE SIGNAL ;
    PORT
      LAYER M5 ;
        RECT  30.336 51.756 30.36 51.84 ;
    END
  END q[164]
  PIN q[165]
    DIRECTION OUTPUT ;
    USE SIGNAL ;
    PORT
      LAYER M5 ;
        RECT  30.48 51.756 30.504 51.84 ;
    END
  END q[165]
  PIN q[166]
    DIRECTION OUTPUT ;
    USE SIGNAL ;
    PORT
      LAYER M5 ;
        RECT  30.624 51.756 30.648 51.84 ;
    END
  END q[166]
  PIN q[167]
    DIRECTION OUTPUT ;
    USE SIGNAL ;
    PORT
      LAYER M5 ;
        RECT  30.768 51.756 30.792 51.84 ;
    END
  END q[167]
  PIN q[168]
    DIRECTION OUTPUT ;
    USE SIGNAL ;
    PORT
      LAYER M5 ;
        RECT  30.912 51.756 30.936 51.84 ;
    END
  END q[168]
  PIN q[169]
    DIRECTION OUTPUT ;
    USE SIGNAL ;
    PORT
      LAYER M5 ;
        RECT  31.056 51.756 31.08 51.84 ;
    END
  END q[169]
  PIN q[16]
    DIRECTION OUTPUT ;
    USE SIGNAL ;
    PORT
      LAYER M5 ;
        RECT  9.024 51.756 9.048 51.84 ;
    END
  END q[16]
  PIN q[170]
    DIRECTION OUTPUT ;
    USE SIGNAL ;
    PORT
      LAYER M5 ;
        RECT  31.2 51.756 31.224 51.84 ;
    END
  END q[170]
  PIN q[171]
    DIRECTION OUTPUT ;
    USE SIGNAL ;
    PORT
      LAYER M5 ;
        RECT  31.344 51.756 31.368 51.84 ;
    END
  END q[171]
  PIN q[172]
    DIRECTION OUTPUT ;
    USE SIGNAL ;
    PORT
      LAYER M5 ;
        RECT  31.488 51.756 31.512 51.84 ;
    END
  END q[172]
  PIN q[173]
    DIRECTION OUTPUT ;
    USE SIGNAL ;
    PORT
      LAYER M5 ;
        RECT  31.632 51.756 31.656 51.84 ;
    END
  END q[173]
  PIN q[174]
    DIRECTION OUTPUT ;
    USE SIGNAL ;
    PORT
      LAYER M5 ;
        RECT  31.776 51.756 31.8 51.84 ;
    END
  END q[174]
  PIN q[175]
    DIRECTION OUTPUT ;
    USE SIGNAL ;
    PORT
      LAYER M5 ;
        RECT  31.92 51.756 31.944 51.84 ;
    END
  END q[175]
  PIN q[176]
    DIRECTION OUTPUT ;
    USE SIGNAL ;
    PORT
      LAYER M5 ;
        RECT  32.064 51.756 32.088 51.84 ;
    END
  END q[176]
  PIN q[177]
    DIRECTION OUTPUT ;
    USE SIGNAL ;
    PORT
      LAYER M5 ;
        RECT  32.208 51.756 32.232 51.84 ;
    END
  END q[177]
  PIN q[178]
    DIRECTION OUTPUT ;
    USE SIGNAL ;
    PORT
      LAYER M5 ;
        RECT  32.352 51.756 32.376 51.84 ;
    END
  END q[178]
  PIN q[179]
    DIRECTION OUTPUT ;
    USE SIGNAL ;
    PORT
      LAYER M5 ;
        RECT  32.496 51.756 32.52 51.84 ;
    END
  END q[179]
  PIN q[17]
    DIRECTION OUTPUT ;
    USE SIGNAL ;
    PORT
      LAYER M5 ;
        RECT  9.168 51.756 9.192 51.84 ;
    END
  END q[17]
  PIN q[180]
    DIRECTION OUTPUT ;
    USE SIGNAL ;
    PORT
      LAYER M5 ;
        RECT  32.64 51.756 32.664 51.84 ;
    END
  END q[180]
  PIN q[181]
    DIRECTION OUTPUT ;
    USE SIGNAL ;
    PORT
      LAYER M5 ;
        RECT  32.784 51.756 32.808 51.84 ;
    END
  END q[181]
  PIN q[182]
    DIRECTION OUTPUT ;
    USE SIGNAL ;
    PORT
      LAYER M5 ;
        RECT  32.928 51.756 32.952 51.84 ;
    END
  END q[182]
  PIN q[183]
    DIRECTION OUTPUT ;
    USE SIGNAL ;
    PORT
      LAYER M5 ;
        RECT  33.072 51.756 33.096 51.84 ;
    END
  END q[183]
  PIN q[184]
    DIRECTION OUTPUT ;
    USE SIGNAL ;
    PORT
      LAYER M5 ;
        RECT  33.216 51.756 33.24 51.84 ;
    END
  END q[184]
  PIN q[185]
    DIRECTION OUTPUT ;
    USE SIGNAL ;
    PORT
      LAYER M5 ;
        RECT  33.36 51.756 33.384 51.84 ;
    END
  END q[185]
  PIN q[186]
    DIRECTION OUTPUT ;
    USE SIGNAL ;
    PORT
      LAYER M5 ;
        RECT  33.504 51.756 33.528 51.84 ;
    END
  END q[186]
  PIN q[187]
    DIRECTION OUTPUT ;
    USE SIGNAL ;
    PORT
      LAYER M5 ;
        RECT  33.648 51.756 33.672 51.84 ;
    END
  END q[187]
  PIN q[188]
    DIRECTION OUTPUT ;
    USE SIGNAL ;
    PORT
      LAYER M5 ;
        RECT  33.792 51.756 33.816 51.84 ;
    END
  END q[188]
  PIN q[189]
    DIRECTION OUTPUT ;
    USE SIGNAL ;
    PORT
      LAYER M5 ;
        RECT  33.936 51.756 33.96 51.84 ;
    END
  END q[189]
  PIN q[18]
    DIRECTION OUTPUT ;
    USE SIGNAL ;
    PORT
      LAYER M5 ;
        RECT  9.312 51.756 9.336 51.84 ;
    END
  END q[18]
  PIN q[190]
    DIRECTION OUTPUT ;
    USE SIGNAL ;
    PORT
      LAYER M5 ;
        RECT  34.08 51.756 34.104 51.84 ;
    END
  END q[190]
  PIN q[191]
    DIRECTION OUTPUT ;
    USE SIGNAL ;
    PORT
      LAYER M5 ;
        RECT  34.224 51.756 34.248 51.84 ;
    END
  END q[191]
  PIN q[192]
    DIRECTION OUTPUT ;
    USE SIGNAL ;
    PORT
      LAYER M5 ;
        RECT  34.368 51.756 34.392 51.84 ;
    END
  END q[192]
  PIN q[193]
    DIRECTION OUTPUT ;
    USE SIGNAL ;
    PORT
      LAYER M5 ;
        RECT  34.512 51.756 34.536 51.84 ;
    END
  END q[193]
  PIN q[194]
    DIRECTION OUTPUT ;
    USE SIGNAL ;
    PORT
      LAYER M5 ;
        RECT  34.656 51.756 34.68 51.84 ;
    END
  END q[194]
  PIN q[195]
    DIRECTION OUTPUT ;
    USE SIGNAL ;
    PORT
      LAYER M5 ;
        RECT  34.8 51.756 34.824 51.84 ;
    END
  END q[195]
  PIN q[196]
    DIRECTION OUTPUT ;
    USE SIGNAL ;
    PORT
      LAYER M5 ;
        RECT  34.944 51.756 34.968 51.84 ;
    END
  END q[196]
  PIN q[197]
    DIRECTION OUTPUT ;
    USE SIGNAL ;
    PORT
      LAYER M5 ;
        RECT  35.088 51.756 35.112 51.84 ;
    END
  END q[197]
  PIN q[198]
    DIRECTION OUTPUT ;
    USE SIGNAL ;
    PORT
      LAYER M5 ;
        RECT  35.232 51.756 35.256 51.84 ;
    END
  END q[198]
  PIN q[199]
    DIRECTION OUTPUT ;
    USE SIGNAL ;
    PORT
      LAYER M5 ;
        RECT  35.376 51.756 35.4 51.84 ;
    END
  END q[199]
  PIN q[19]
    DIRECTION OUTPUT ;
    USE SIGNAL ;
    PORT
      LAYER M5 ;
        RECT  9.456 51.756 9.48 51.84 ;
    END
  END q[19]
  PIN q[1]
    DIRECTION OUTPUT ;
    USE SIGNAL ;
    PORT
      LAYER M5 ;
        RECT  6.864 51.756 6.888 51.84 ;
    END
  END q[1]
  PIN q[200]
    DIRECTION OUTPUT ;
    USE SIGNAL ;
    PORT
      LAYER M5 ;
        RECT  35.52 51.756 35.544 51.84 ;
    END
  END q[200]
  PIN q[201]
    DIRECTION OUTPUT ;
    USE SIGNAL ;
    PORT
      LAYER M5 ;
        RECT  35.664 51.756 35.688 51.84 ;
    END
  END q[201]
  PIN q[202]
    DIRECTION OUTPUT ;
    USE SIGNAL ;
    PORT
      LAYER M5 ;
        RECT  35.808 51.756 35.832 51.84 ;
    END
  END q[202]
  PIN q[203]
    DIRECTION OUTPUT ;
    USE SIGNAL ;
    PORT
      LAYER M5 ;
        RECT  35.952 51.756 35.976 51.84 ;
    END
  END q[203]
  PIN q[204]
    DIRECTION OUTPUT ;
    USE SIGNAL ;
    PORT
      LAYER M5 ;
        RECT  36.096 51.756 36.12 51.84 ;
    END
  END q[204]
  PIN q[205]
    DIRECTION OUTPUT ;
    USE SIGNAL ;
    PORT
      LAYER M5 ;
        RECT  36.24 51.756 36.264 51.84 ;
    END
  END q[205]
  PIN q[206]
    DIRECTION OUTPUT ;
    USE SIGNAL ;
    PORT
      LAYER M5 ;
        RECT  36.384 51.756 36.408 51.84 ;
    END
  END q[206]
  PIN q[207]
    DIRECTION OUTPUT ;
    USE SIGNAL ;
    PORT
      LAYER M5 ;
        RECT  36.528 51.756 36.552 51.84 ;
    END
  END q[207]
  PIN q[208]
    DIRECTION OUTPUT ;
    USE SIGNAL ;
    PORT
      LAYER M5 ;
        RECT  36.672 51.756 36.696 51.84 ;
    END
  END q[208]
  PIN q[209]
    DIRECTION OUTPUT ;
    USE SIGNAL ;
    PORT
      LAYER M5 ;
        RECT  36.816 51.756 36.84 51.84 ;
    END
  END q[209]
  PIN q[20]
    DIRECTION OUTPUT ;
    USE SIGNAL ;
    PORT
      LAYER M5 ;
        RECT  9.6 51.756 9.624 51.84 ;
    END
  END q[20]
  PIN q[210]
    DIRECTION OUTPUT ;
    USE SIGNAL ;
    PORT
      LAYER M5 ;
        RECT  36.96 51.756 36.984 51.84 ;
    END
  END q[210]
  PIN q[211]
    DIRECTION OUTPUT ;
    USE SIGNAL ;
    PORT
      LAYER M5 ;
        RECT  37.104 51.756 37.128 51.84 ;
    END
  END q[211]
  PIN q[212]
    DIRECTION OUTPUT ;
    USE SIGNAL ;
    PORT
      LAYER M5 ;
        RECT  37.248 51.756 37.272 51.84 ;
    END
  END q[212]
  PIN q[213]
    DIRECTION OUTPUT ;
    USE SIGNAL ;
    PORT
      LAYER M5 ;
        RECT  37.392 51.756 37.416 51.84 ;
    END
  END q[213]
  PIN q[214]
    DIRECTION OUTPUT ;
    USE SIGNAL ;
    PORT
      LAYER M5 ;
        RECT  37.536 51.756 37.56 51.84 ;
    END
  END q[214]
  PIN q[215]
    DIRECTION OUTPUT ;
    USE SIGNAL ;
    PORT
      LAYER M5 ;
        RECT  37.68 51.756 37.704 51.84 ;
    END
  END q[215]
  PIN q[216]
    DIRECTION OUTPUT ;
    USE SIGNAL ;
    PORT
      LAYER M5 ;
        RECT  37.824 51.756 37.848 51.84 ;
    END
  END q[216]
  PIN q[217]
    DIRECTION OUTPUT ;
    USE SIGNAL ;
    PORT
      LAYER M5 ;
        RECT  37.968 51.756 37.992 51.84 ;
    END
  END q[217]
  PIN q[218]
    DIRECTION OUTPUT ;
    USE SIGNAL ;
    PORT
      LAYER M5 ;
        RECT  38.112 51.756 38.136 51.84 ;
    END
  END q[218]
  PIN q[219]
    DIRECTION OUTPUT ;
    USE SIGNAL ;
    PORT
      LAYER M5 ;
        RECT  38.256 51.756 38.28 51.84 ;
    END
  END q[219]
  PIN q[21]
    DIRECTION OUTPUT ;
    USE SIGNAL ;
    PORT
      LAYER M5 ;
        RECT  9.744 51.756 9.768 51.84 ;
    END
  END q[21]
  PIN q[220]
    DIRECTION OUTPUT ;
    USE SIGNAL ;
    PORT
      LAYER M5 ;
        RECT  38.4 51.756 38.424 51.84 ;
    END
  END q[220]
  PIN q[221]
    DIRECTION OUTPUT ;
    USE SIGNAL ;
    PORT
      LAYER M5 ;
        RECT  38.544 51.756 38.568 51.84 ;
    END
  END q[221]
  PIN q[222]
    DIRECTION OUTPUT ;
    USE SIGNAL ;
    PORT
      LAYER M5 ;
        RECT  38.688 51.756 38.712 51.84 ;
    END
  END q[222]
  PIN q[223]
    DIRECTION OUTPUT ;
    USE SIGNAL ;
    PORT
      LAYER M5 ;
        RECT  38.832 51.756 38.856 51.84 ;
    END
  END q[223]
  PIN q[224]
    DIRECTION OUTPUT ;
    USE SIGNAL ;
    PORT
      LAYER M5 ;
        RECT  38.976 51.756 39 51.84 ;
    END
  END q[224]
  PIN q[225]
    DIRECTION OUTPUT ;
    USE SIGNAL ;
    PORT
      LAYER M5 ;
        RECT  39.12 51.756 39.144 51.84 ;
    END
  END q[225]
  PIN q[226]
    DIRECTION OUTPUT ;
    USE SIGNAL ;
    PORT
      LAYER M5 ;
        RECT  39.264 51.756 39.288 51.84 ;
    END
  END q[226]
  PIN q[227]
    DIRECTION OUTPUT ;
    USE SIGNAL ;
    PORT
      LAYER M5 ;
        RECT  39.408 51.756 39.432 51.84 ;
    END
  END q[227]
  PIN q[228]
    DIRECTION OUTPUT ;
    USE SIGNAL ;
    PORT
      LAYER M5 ;
        RECT  39.552 51.756 39.576 51.84 ;
    END
  END q[228]
  PIN q[229]
    DIRECTION OUTPUT ;
    USE SIGNAL ;
    PORT
      LAYER M5 ;
        RECT  39.696 51.756 39.72 51.84 ;
    END
  END q[229]
  PIN q[22]
    DIRECTION OUTPUT ;
    USE SIGNAL ;
    PORT
      LAYER M5 ;
        RECT  9.888 51.756 9.912 51.84 ;
    END
  END q[22]
  PIN q[230]
    DIRECTION OUTPUT ;
    USE SIGNAL ;
    PORT
      LAYER M5 ;
        RECT  39.84 51.756 39.864 51.84 ;
    END
  END q[230]
  PIN q[231]
    DIRECTION OUTPUT ;
    USE SIGNAL ;
    PORT
      LAYER M5 ;
        RECT  39.984 51.756 40.008 51.84 ;
    END
  END q[231]
  PIN q[232]
    DIRECTION OUTPUT ;
    USE SIGNAL ;
    PORT
      LAYER M5 ;
        RECT  40.128 51.756 40.152 51.84 ;
    END
  END q[232]
  PIN q[233]
    DIRECTION OUTPUT ;
    USE SIGNAL ;
    PORT
      LAYER M5 ;
        RECT  40.272 51.756 40.296 51.84 ;
    END
  END q[233]
  PIN q[234]
    DIRECTION OUTPUT ;
    USE SIGNAL ;
    PORT
      LAYER M5 ;
        RECT  40.416 51.756 40.44 51.84 ;
    END
  END q[234]
  PIN q[235]
    DIRECTION OUTPUT ;
    USE SIGNAL ;
    PORT
      LAYER M5 ;
        RECT  40.56 51.756 40.584 51.84 ;
    END
  END q[235]
  PIN q[236]
    DIRECTION OUTPUT ;
    USE SIGNAL ;
    PORT
      LAYER M5 ;
        RECT  40.704 51.756 40.728 51.84 ;
    END
  END q[236]
  PIN q[237]
    DIRECTION OUTPUT ;
    USE SIGNAL ;
    PORT
      LAYER M5 ;
        RECT  40.848 51.756 40.872 51.84 ;
    END
  END q[237]
  PIN q[238]
    DIRECTION OUTPUT ;
    USE SIGNAL ;
    PORT
      LAYER M5 ;
        RECT  40.992 51.756 41.016 51.84 ;
    END
  END q[238]
  PIN q[239]
    DIRECTION OUTPUT ;
    USE SIGNAL ;
    PORT
      LAYER M5 ;
        RECT  41.136 51.756 41.16 51.84 ;
    END
  END q[239]
  PIN q[23]
    DIRECTION OUTPUT ;
    USE SIGNAL ;
    PORT
      LAYER M5 ;
        RECT  10.032 51.756 10.056 51.84 ;
    END
  END q[23]
  PIN q[240]
    DIRECTION OUTPUT ;
    USE SIGNAL ;
    PORT
      LAYER M5 ;
        RECT  41.28 51.756 41.304 51.84 ;
    END
  END q[240]
  PIN q[241]
    DIRECTION OUTPUT ;
    USE SIGNAL ;
    PORT
      LAYER M5 ;
        RECT  41.424 51.756 41.448 51.84 ;
    END
  END q[241]
  PIN q[242]
    DIRECTION OUTPUT ;
    USE SIGNAL ;
    PORT
      LAYER M5 ;
        RECT  41.568 51.756 41.592 51.84 ;
    END
  END q[242]
  PIN q[243]
    DIRECTION OUTPUT ;
    USE SIGNAL ;
    PORT
      LAYER M5 ;
        RECT  41.712 51.756 41.736 51.84 ;
    END
  END q[243]
  PIN q[244]
    DIRECTION OUTPUT ;
    USE SIGNAL ;
    PORT
      LAYER M5 ;
        RECT  41.856 51.756 41.88 51.84 ;
    END
  END q[244]
  PIN q[245]
    DIRECTION OUTPUT ;
    USE SIGNAL ;
    PORT
      LAYER M5 ;
        RECT  42 51.756 42.024 51.84 ;
    END
  END q[245]
  PIN q[246]
    DIRECTION OUTPUT ;
    USE SIGNAL ;
    PORT
      LAYER M5 ;
        RECT  42.144 51.756 42.168 51.84 ;
    END
  END q[246]
  PIN q[247]
    DIRECTION OUTPUT ;
    USE SIGNAL ;
    PORT
      LAYER M5 ;
        RECT  42.288 51.756 42.312 51.84 ;
    END
  END q[247]
  PIN q[248]
    DIRECTION OUTPUT ;
    USE SIGNAL ;
    PORT
      LAYER M5 ;
        RECT  42.432 51.756 42.456 51.84 ;
    END
  END q[248]
  PIN q[249]
    DIRECTION OUTPUT ;
    USE SIGNAL ;
    PORT
      LAYER M5 ;
        RECT  42.576 51.756 42.6 51.84 ;
    END
  END q[249]
  PIN q[24]
    DIRECTION OUTPUT ;
    USE SIGNAL ;
    PORT
      LAYER M5 ;
        RECT  10.176 51.756 10.2 51.84 ;
    END
  END q[24]
  PIN q[250]
    DIRECTION OUTPUT ;
    USE SIGNAL ;
    PORT
      LAYER M5 ;
        RECT  42.72 51.756 42.744 51.84 ;
    END
  END q[250]
  PIN q[251]
    DIRECTION OUTPUT ;
    USE SIGNAL ;
    PORT
      LAYER M5 ;
        RECT  42.864 51.756 42.888 51.84 ;
    END
  END q[251]
  PIN q[252]
    DIRECTION OUTPUT ;
    USE SIGNAL ;
    PORT
      LAYER M5 ;
        RECT  43.008 51.756 43.032 51.84 ;
    END
  END q[252]
  PIN q[253]
    DIRECTION OUTPUT ;
    USE SIGNAL ;
    PORT
      LAYER M5 ;
        RECT  43.152 51.756 43.176 51.84 ;
    END
  END q[253]
  PIN q[254]
    DIRECTION OUTPUT ;
    USE SIGNAL ;
    PORT
      LAYER M5 ;
        RECT  43.296 51.756 43.32 51.84 ;
    END
  END q[254]
  PIN q[255]
    DIRECTION OUTPUT ;
    USE SIGNAL ;
    PORT
      LAYER M5 ;
        RECT  43.44 51.756 43.464 51.84 ;
    END
  END q[255]
  PIN q[256]
    DIRECTION OUTPUT ;
    USE SIGNAL ;
    PORT
      LAYER M5 ;
        RECT  43.584 51.756 43.608 51.84 ;
    END
  END q[256]
  PIN q[257]
    DIRECTION OUTPUT ;
    USE SIGNAL ;
    PORT
      LAYER M5 ;
        RECT  43.728 51.756 43.752 51.84 ;
    END
  END q[257]
  PIN q[258]
    DIRECTION OUTPUT ;
    USE SIGNAL ;
    PORT
      LAYER M5 ;
        RECT  45.312 51.756 45.336 51.84 ;
    END
  END q[258]
  PIN q[259]
    DIRECTION OUTPUT ;
    USE SIGNAL ;
    PORT
      LAYER M5 ;
        RECT  45.456 51.756 45.48 51.84 ;
    END
  END q[259]
  PIN q[25]
    DIRECTION OUTPUT ;
    USE SIGNAL ;
    PORT
      LAYER M5 ;
        RECT  10.32 51.756 10.344 51.84 ;
    END
  END q[25]
  PIN q[260]
    DIRECTION OUTPUT ;
    USE SIGNAL ;
    PORT
      LAYER M5 ;
        RECT  45.6 51.756 45.624 51.84 ;
    END
  END q[260]
  PIN q[261]
    DIRECTION OUTPUT ;
    USE SIGNAL ;
    PORT
      LAYER M5 ;
        RECT  45.744 51.756 45.768 51.84 ;
    END
  END q[261]
  PIN q[262]
    DIRECTION OUTPUT ;
    USE SIGNAL ;
    PORT
      LAYER M5 ;
        RECT  45.888 51.756 45.912 51.84 ;
    END
  END q[262]
  PIN q[263]
    DIRECTION OUTPUT ;
    USE SIGNAL ;
    PORT
      LAYER M5 ;
        RECT  46.032 51.756 46.056 51.84 ;
    END
  END q[263]
  PIN q[264]
    DIRECTION OUTPUT ;
    USE SIGNAL ;
    PORT
      LAYER M5 ;
        RECT  46.176 51.756 46.2 51.84 ;
    END
  END q[264]
  PIN q[265]
    DIRECTION OUTPUT ;
    USE SIGNAL ;
    PORT
      LAYER M5 ;
        RECT  46.32 51.756 46.344 51.84 ;
    END
  END q[265]
  PIN q[266]
    DIRECTION OUTPUT ;
    USE SIGNAL ;
    PORT
      LAYER M5 ;
        RECT  46.464 51.756 46.488 51.84 ;
    END
  END q[266]
  PIN q[267]
    DIRECTION OUTPUT ;
    USE SIGNAL ;
    PORT
      LAYER M5 ;
        RECT  46.608 51.756 46.632 51.84 ;
    END
  END q[267]
  PIN q[268]
    DIRECTION OUTPUT ;
    USE SIGNAL ;
    PORT
      LAYER M5 ;
        RECT  46.752 51.756 46.776 51.84 ;
    END
  END q[268]
  PIN q[269]
    DIRECTION OUTPUT ;
    USE SIGNAL ;
    PORT
      LAYER M5 ;
        RECT  46.896 51.756 46.92 51.84 ;
    END
  END q[269]
  PIN q[26]
    DIRECTION OUTPUT ;
    USE SIGNAL ;
    PORT
      LAYER M5 ;
        RECT  10.464 51.756 10.488 51.84 ;
    END
  END q[26]
  PIN q[270]
    DIRECTION OUTPUT ;
    USE SIGNAL ;
    PORT
      LAYER M5 ;
        RECT  47.04 51.756 47.064 51.84 ;
    END
  END q[270]
  PIN q[271]
    DIRECTION OUTPUT ;
    USE SIGNAL ;
    PORT
      LAYER M5 ;
        RECT  47.184 51.756 47.208 51.84 ;
    END
  END q[271]
  PIN q[272]
    DIRECTION OUTPUT ;
    USE SIGNAL ;
    PORT
      LAYER M5 ;
        RECT  47.328 51.756 47.352 51.84 ;
    END
  END q[272]
  PIN q[273]
    DIRECTION OUTPUT ;
    USE SIGNAL ;
    PORT
      LAYER M5 ;
        RECT  47.472 51.756 47.496 51.84 ;
    END
  END q[273]
  PIN q[274]
    DIRECTION OUTPUT ;
    USE SIGNAL ;
    PORT
      LAYER M5 ;
        RECT  47.616 51.756 47.64 51.84 ;
    END
  END q[274]
  PIN q[275]
    DIRECTION OUTPUT ;
    USE SIGNAL ;
    PORT
      LAYER M5 ;
        RECT  47.76 51.756 47.784 51.84 ;
    END
  END q[275]
  PIN q[276]
    DIRECTION OUTPUT ;
    USE SIGNAL ;
    PORT
      LAYER M5 ;
        RECT  47.904 51.756 47.928 51.84 ;
    END
  END q[276]
  PIN q[277]
    DIRECTION OUTPUT ;
    USE SIGNAL ;
    PORT
      LAYER M5 ;
        RECT  48.048 51.756 48.072 51.84 ;
    END
  END q[277]
  PIN q[278]
    DIRECTION OUTPUT ;
    USE SIGNAL ;
    PORT
      LAYER M5 ;
        RECT  48.192 51.756 48.216 51.84 ;
    END
  END q[278]
  PIN q[279]
    DIRECTION OUTPUT ;
    USE SIGNAL ;
    PORT
      LAYER M5 ;
        RECT  48.336 51.756 48.36 51.84 ;
    END
  END q[279]
  PIN q[27]
    DIRECTION OUTPUT ;
    USE SIGNAL ;
    PORT
      LAYER M5 ;
        RECT  10.608 51.756 10.632 51.84 ;
    END
  END q[27]
  PIN q[280]
    DIRECTION OUTPUT ;
    USE SIGNAL ;
    PORT
      LAYER M5 ;
        RECT  48.48 51.756 48.504 51.84 ;
    END
  END q[280]
  PIN q[281]
    DIRECTION OUTPUT ;
    USE SIGNAL ;
    PORT
      LAYER M5 ;
        RECT  48.624 51.756 48.648 51.84 ;
    END
  END q[281]
  PIN q[282]
    DIRECTION OUTPUT ;
    USE SIGNAL ;
    PORT
      LAYER M5 ;
        RECT  48.768 51.756 48.792 51.84 ;
    END
  END q[282]
  PIN q[283]
    DIRECTION OUTPUT ;
    USE SIGNAL ;
    PORT
      LAYER M5 ;
        RECT  48.912 51.756 48.936 51.84 ;
    END
  END q[283]
  PIN q[284]
    DIRECTION OUTPUT ;
    USE SIGNAL ;
    PORT
      LAYER M5 ;
        RECT  49.056 51.756 49.08 51.84 ;
    END
  END q[284]
  PIN q[285]
    DIRECTION OUTPUT ;
    USE SIGNAL ;
    PORT
      LAYER M5 ;
        RECT  49.2 51.756 49.224 51.84 ;
    END
  END q[285]
  PIN q[286]
    DIRECTION OUTPUT ;
    USE SIGNAL ;
    PORT
      LAYER M5 ;
        RECT  49.344 51.756 49.368 51.84 ;
    END
  END q[286]
  PIN q[287]
    DIRECTION OUTPUT ;
    USE SIGNAL ;
    PORT
      LAYER M5 ;
        RECT  49.488 51.756 49.512 51.84 ;
    END
  END q[287]
  PIN q[288]
    DIRECTION OUTPUT ;
    USE SIGNAL ;
    PORT
      LAYER M5 ;
        RECT  49.632 51.756 49.656 51.84 ;
    END
  END q[288]
  PIN q[289]
    DIRECTION OUTPUT ;
    USE SIGNAL ;
    PORT
      LAYER M5 ;
        RECT  49.776 51.756 49.8 51.84 ;
    END
  END q[289]
  PIN q[28]
    DIRECTION OUTPUT ;
    USE SIGNAL ;
    PORT
      LAYER M5 ;
        RECT  10.752 51.756 10.776 51.84 ;
    END
  END q[28]
  PIN q[290]
    DIRECTION OUTPUT ;
    USE SIGNAL ;
    PORT
      LAYER M5 ;
        RECT  49.92 51.756 49.944 51.84 ;
    END
  END q[290]
  PIN q[291]
    DIRECTION OUTPUT ;
    USE SIGNAL ;
    PORT
      LAYER M5 ;
        RECT  50.064 51.756 50.088 51.84 ;
    END
  END q[291]
  PIN q[292]
    DIRECTION OUTPUT ;
    USE SIGNAL ;
    PORT
      LAYER M5 ;
        RECT  50.208 51.756 50.232 51.84 ;
    END
  END q[292]
  PIN q[293]
    DIRECTION OUTPUT ;
    USE SIGNAL ;
    PORT
      LAYER M5 ;
        RECT  50.352 51.756 50.376 51.84 ;
    END
  END q[293]
  PIN q[294]
    DIRECTION OUTPUT ;
    USE SIGNAL ;
    PORT
      LAYER M5 ;
        RECT  50.496 51.756 50.52 51.84 ;
    END
  END q[294]
  PIN q[295]
    DIRECTION OUTPUT ;
    USE SIGNAL ;
    PORT
      LAYER M5 ;
        RECT  50.64 51.756 50.664 51.84 ;
    END
  END q[295]
  PIN q[296]
    DIRECTION OUTPUT ;
    USE SIGNAL ;
    PORT
      LAYER M5 ;
        RECT  50.784 51.756 50.808 51.84 ;
    END
  END q[296]
  PIN q[297]
    DIRECTION OUTPUT ;
    USE SIGNAL ;
    PORT
      LAYER M5 ;
        RECT  50.928 51.756 50.952 51.84 ;
    END
  END q[297]
  PIN q[298]
    DIRECTION OUTPUT ;
    USE SIGNAL ;
    PORT
      LAYER M5 ;
        RECT  51.072 51.756 51.096 51.84 ;
    END
  END q[298]
  PIN q[299]
    DIRECTION OUTPUT ;
    USE SIGNAL ;
    PORT
      LAYER M5 ;
        RECT  51.216 51.756 51.24 51.84 ;
    END
  END q[299]
  PIN q[29]
    DIRECTION OUTPUT ;
    USE SIGNAL ;
    PORT
      LAYER M5 ;
        RECT  10.896 51.756 10.92 51.84 ;
    END
  END q[29]
  PIN q[2]
    DIRECTION OUTPUT ;
    USE SIGNAL ;
    PORT
      LAYER M5 ;
        RECT  7.008 51.756 7.032 51.84 ;
    END
  END q[2]
  PIN q[300]
    DIRECTION OUTPUT ;
    USE SIGNAL ;
    PORT
      LAYER M5 ;
        RECT  51.36 51.756 51.384 51.84 ;
    END
  END q[300]
  PIN q[301]
    DIRECTION OUTPUT ;
    USE SIGNAL ;
    PORT
      LAYER M5 ;
        RECT  51.504 51.756 51.528 51.84 ;
    END
  END q[301]
  PIN q[302]
    DIRECTION OUTPUT ;
    USE SIGNAL ;
    PORT
      LAYER M5 ;
        RECT  51.648 51.756 51.672 51.84 ;
    END
  END q[302]
  PIN q[303]
    DIRECTION OUTPUT ;
    USE SIGNAL ;
    PORT
      LAYER M5 ;
        RECT  51.792 51.756 51.816 51.84 ;
    END
  END q[303]
  PIN q[304]
    DIRECTION OUTPUT ;
    USE SIGNAL ;
    PORT
      LAYER M5 ;
        RECT  51.936 51.756 51.96 51.84 ;
    END
  END q[304]
  PIN q[305]
    DIRECTION OUTPUT ;
    USE SIGNAL ;
    PORT
      LAYER M5 ;
        RECT  52.08 51.756 52.104 51.84 ;
    END
  END q[305]
  PIN q[306]
    DIRECTION OUTPUT ;
    USE SIGNAL ;
    PORT
      LAYER M5 ;
        RECT  52.224 51.756 52.248 51.84 ;
    END
  END q[306]
  PIN q[307]
    DIRECTION OUTPUT ;
    USE SIGNAL ;
    PORT
      LAYER M5 ;
        RECT  52.368 51.756 52.392 51.84 ;
    END
  END q[307]
  PIN q[308]
    DIRECTION OUTPUT ;
    USE SIGNAL ;
    PORT
      LAYER M5 ;
        RECT  52.512 51.756 52.536 51.84 ;
    END
  END q[308]
  PIN q[309]
    DIRECTION OUTPUT ;
    USE SIGNAL ;
    PORT
      LAYER M5 ;
        RECT  52.656 51.756 52.68 51.84 ;
    END
  END q[309]
  PIN q[30]
    DIRECTION OUTPUT ;
    USE SIGNAL ;
    PORT
      LAYER M5 ;
        RECT  11.04 51.756 11.064 51.84 ;
    END
  END q[30]
  PIN q[310]
    DIRECTION OUTPUT ;
    USE SIGNAL ;
    PORT
      LAYER M5 ;
        RECT  52.8 51.756 52.824 51.84 ;
    END
  END q[310]
  PIN q[311]
    DIRECTION OUTPUT ;
    USE SIGNAL ;
    PORT
      LAYER M5 ;
        RECT  52.944 51.756 52.968 51.84 ;
    END
  END q[311]
  PIN q[312]
    DIRECTION OUTPUT ;
    USE SIGNAL ;
    PORT
      LAYER M5 ;
        RECT  53.088 51.756 53.112 51.84 ;
    END
  END q[312]
  PIN q[313]
    DIRECTION OUTPUT ;
    USE SIGNAL ;
    PORT
      LAYER M5 ;
        RECT  53.232 51.756 53.256 51.84 ;
    END
  END q[313]
  PIN q[314]
    DIRECTION OUTPUT ;
    USE SIGNAL ;
    PORT
      LAYER M5 ;
        RECT  53.376 51.756 53.4 51.84 ;
    END
  END q[314]
  PIN q[315]
    DIRECTION OUTPUT ;
    USE SIGNAL ;
    PORT
      LAYER M5 ;
        RECT  53.52 51.756 53.544 51.84 ;
    END
  END q[315]
  PIN q[316]
    DIRECTION OUTPUT ;
    USE SIGNAL ;
    PORT
      LAYER M5 ;
        RECT  53.664 51.756 53.688 51.84 ;
    END
  END q[316]
  PIN q[317]
    DIRECTION OUTPUT ;
    USE SIGNAL ;
    PORT
      LAYER M5 ;
        RECT  53.808 51.756 53.832 51.84 ;
    END
  END q[317]
  PIN q[318]
    DIRECTION OUTPUT ;
    USE SIGNAL ;
    PORT
      LAYER M5 ;
        RECT  53.952 51.756 53.976 51.84 ;
    END
  END q[318]
  PIN q[319]
    DIRECTION OUTPUT ;
    USE SIGNAL ;
    PORT
      LAYER M5 ;
        RECT  54.096 51.756 54.12 51.84 ;
    END
  END q[319]
  PIN q[31]
    DIRECTION OUTPUT ;
    USE SIGNAL ;
    PORT
      LAYER M5 ;
        RECT  11.184 51.756 11.208 51.84 ;
    END
  END q[31]
  PIN q[320]
    DIRECTION OUTPUT ;
    USE SIGNAL ;
    PORT
      LAYER M5 ;
        RECT  54.24 51.756 54.264 51.84 ;
    END
  END q[320]
  PIN q[321]
    DIRECTION OUTPUT ;
    USE SIGNAL ;
    PORT
      LAYER M5 ;
        RECT  54.384 51.756 54.408 51.84 ;
    END
  END q[321]
  PIN q[322]
    DIRECTION OUTPUT ;
    USE SIGNAL ;
    PORT
      LAYER M5 ;
        RECT  54.528 51.756 54.552 51.84 ;
    END
  END q[322]
  PIN q[323]
    DIRECTION OUTPUT ;
    USE SIGNAL ;
    PORT
      LAYER M5 ;
        RECT  54.672 51.756 54.696 51.84 ;
    END
  END q[323]
  PIN q[324]
    DIRECTION OUTPUT ;
    USE SIGNAL ;
    PORT
      LAYER M5 ;
        RECT  54.816 51.756 54.84 51.84 ;
    END
  END q[324]
  PIN q[325]
    DIRECTION OUTPUT ;
    USE SIGNAL ;
    PORT
      LAYER M5 ;
        RECT  54.96 51.756 54.984 51.84 ;
    END
  END q[325]
  PIN q[326]
    DIRECTION OUTPUT ;
    USE SIGNAL ;
    PORT
      LAYER M5 ;
        RECT  55.104 51.756 55.128 51.84 ;
    END
  END q[326]
  PIN q[327]
    DIRECTION OUTPUT ;
    USE SIGNAL ;
    PORT
      LAYER M5 ;
        RECT  55.248 51.756 55.272 51.84 ;
    END
  END q[327]
  PIN q[328]
    DIRECTION OUTPUT ;
    USE SIGNAL ;
    PORT
      LAYER M5 ;
        RECT  55.392 51.756 55.416 51.84 ;
    END
  END q[328]
  PIN q[329]
    DIRECTION OUTPUT ;
    USE SIGNAL ;
    PORT
      LAYER M5 ;
        RECT  55.536 51.756 55.56 51.84 ;
    END
  END q[329]
  PIN q[32]
    DIRECTION OUTPUT ;
    USE SIGNAL ;
    PORT
      LAYER M5 ;
        RECT  11.328 51.756 11.352 51.84 ;
    END
  END q[32]
  PIN q[330]
    DIRECTION OUTPUT ;
    USE SIGNAL ;
    PORT
      LAYER M5 ;
        RECT  55.68 51.756 55.704 51.84 ;
    END
  END q[330]
  PIN q[331]
    DIRECTION OUTPUT ;
    USE SIGNAL ;
    PORT
      LAYER M5 ;
        RECT  55.824 51.756 55.848 51.84 ;
    END
  END q[331]
  PIN q[332]
    DIRECTION OUTPUT ;
    USE SIGNAL ;
    PORT
      LAYER M5 ;
        RECT  55.968 51.756 55.992 51.84 ;
    END
  END q[332]
  PIN q[333]
    DIRECTION OUTPUT ;
    USE SIGNAL ;
    PORT
      LAYER M5 ;
        RECT  56.112 51.756 56.136 51.84 ;
    END
  END q[333]
  PIN q[334]
    DIRECTION OUTPUT ;
    USE SIGNAL ;
    PORT
      LAYER M5 ;
        RECT  56.256 51.756 56.28 51.84 ;
    END
  END q[334]
  PIN q[335]
    DIRECTION OUTPUT ;
    USE SIGNAL ;
    PORT
      LAYER M5 ;
        RECT  56.4 51.756 56.424 51.84 ;
    END
  END q[335]
  PIN q[336]
    DIRECTION OUTPUT ;
    USE SIGNAL ;
    PORT
      LAYER M5 ;
        RECT  56.544 51.756 56.568 51.84 ;
    END
  END q[336]
  PIN q[337]
    DIRECTION OUTPUT ;
    USE SIGNAL ;
    PORT
      LAYER M5 ;
        RECT  56.688 51.756 56.712 51.84 ;
    END
  END q[337]
  PIN q[338]
    DIRECTION OUTPUT ;
    USE SIGNAL ;
    PORT
      LAYER M5 ;
        RECT  56.832 51.756 56.856 51.84 ;
    END
  END q[338]
  PIN q[339]
    DIRECTION OUTPUT ;
    USE SIGNAL ;
    PORT
      LAYER M5 ;
        RECT  56.976 51.756 57 51.84 ;
    END
  END q[339]
  PIN q[33]
    DIRECTION OUTPUT ;
    USE SIGNAL ;
    PORT
      LAYER M5 ;
        RECT  11.472 51.756 11.496 51.84 ;
    END
  END q[33]
  PIN q[340]
    DIRECTION OUTPUT ;
    USE SIGNAL ;
    PORT
      LAYER M5 ;
        RECT  57.12 51.756 57.144 51.84 ;
    END
  END q[340]
  PIN q[341]
    DIRECTION OUTPUT ;
    USE SIGNAL ;
    PORT
      LAYER M5 ;
        RECT  57.264 51.756 57.288 51.84 ;
    END
  END q[341]
  PIN q[342]
    DIRECTION OUTPUT ;
    USE SIGNAL ;
    PORT
      LAYER M5 ;
        RECT  57.408 51.756 57.432 51.84 ;
    END
  END q[342]
  PIN q[343]
    DIRECTION OUTPUT ;
    USE SIGNAL ;
    PORT
      LAYER M5 ;
        RECT  57.552 51.756 57.576 51.84 ;
    END
  END q[343]
  PIN q[344]
    DIRECTION OUTPUT ;
    USE SIGNAL ;
    PORT
      LAYER M5 ;
        RECT  57.696 51.756 57.72 51.84 ;
    END
  END q[344]
  PIN q[345]
    DIRECTION OUTPUT ;
    USE SIGNAL ;
    PORT
      LAYER M5 ;
        RECT  57.84 51.756 57.864 51.84 ;
    END
  END q[345]
  PIN q[346]
    DIRECTION OUTPUT ;
    USE SIGNAL ;
    PORT
      LAYER M5 ;
        RECT  57.984 51.756 58.008 51.84 ;
    END
  END q[346]
  PIN q[347]
    DIRECTION OUTPUT ;
    USE SIGNAL ;
    PORT
      LAYER M5 ;
        RECT  58.128 51.756 58.152 51.84 ;
    END
  END q[347]
  PIN q[348]
    DIRECTION OUTPUT ;
    USE SIGNAL ;
    PORT
      LAYER M5 ;
        RECT  58.272 51.756 58.296 51.84 ;
    END
  END q[348]
  PIN q[349]
    DIRECTION OUTPUT ;
    USE SIGNAL ;
    PORT
      LAYER M5 ;
        RECT  58.416 51.756 58.44 51.84 ;
    END
  END q[349]
  PIN q[34]
    DIRECTION OUTPUT ;
    USE SIGNAL ;
    PORT
      LAYER M5 ;
        RECT  11.616 51.756 11.64 51.84 ;
    END
  END q[34]
  PIN q[350]
    DIRECTION OUTPUT ;
    USE SIGNAL ;
    PORT
      LAYER M5 ;
        RECT  58.56 51.756 58.584 51.84 ;
    END
  END q[350]
  PIN q[351]
    DIRECTION OUTPUT ;
    USE SIGNAL ;
    PORT
      LAYER M5 ;
        RECT  58.704 51.756 58.728 51.84 ;
    END
  END q[351]
  PIN q[352]
    DIRECTION OUTPUT ;
    USE SIGNAL ;
    PORT
      LAYER M5 ;
        RECT  58.848 51.756 58.872 51.84 ;
    END
  END q[352]
  PIN q[353]
    DIRECTION OUTPUT ;
    USE SIGNAL ;
    PORT
      LAYER M5 ;
        RECT  58.992 51.756 59.016 51.84 ;
    END
  END q[353]
  PIN q[354]
    DIRECTION OUTPUT ;
    USE SIGNAL ;
    PORT
      LAYER M5 ;
        RECT  59.136 51.756 59.16 51.84 ;
    END
  END q[354]
  PIN q[355]
    DIRECTION OUTPUT ;
    USE SIGNAL ;
    PORT
      LAYER M5 ;
        RECT  59.28 51.756 59.304 51.84 ;
    END
  END q[355]
  PIN q[356]
    DIRECTION OUTPUT ;
    USE SIGNAL ;
    PORT
      LAYER M5 ;
        RECT  59.424 51.756 59.448 51.84 ;
    END
  END q[356]
  PIN q[357]
    DIRECTION OUTPUT ;
    USE SIGNAL ;
    PORT
      LAYER M5 ;
        RECT  59.568 51.756 59.592 51.84 ;
    END
  END q[357]
  PIN q[358]
    DIRECTION OUTPUT ;
    USE SIGNAL ;
    PORT
      LAYER M5 ;
        RECT  59.712 51.756 59.736 51.84 ;
    END
  END q[358]
  PIN q[359]
    DIRECTION OUTPUT ;
    USE SIGNAL ;
    PORT
      LAYER M5 ;
        RECT  59.856 51.756 59.88 51.84 ;
    END
  END q[359]
  PIN q[35]
    DIRECTION OUTPUT ;
    USE SIGNAL ;
    PORT
      LAYER M5 ;
        RECT  11.76 51.756 11.784 51.84 ;
    END
  END q[35]
  PIN q[360]
    DIRECTION OUTPUT ;
    USE SIGNAL ;
    PORT
      LAYER M5 ;
        RECT  60 51.756 60.024 51.84 ;
    END
  END q[360]
  PIN q[361]
    DIRECTION OUTPUT ;
    USE SIGNAL ;
    PORT
      LAYER M5 ;
        RECT  60.144 51.756 60.168 51.84 ;
    END
  END q[361]
  PIN q[362]
    DIRECTION OUTPUT ;
    USE SIGNAL ;
    PORT
      LAYER M5 ;
        RECT  60.288 51.756 60.312 51.84 ;
    END
  END q[362]
  PIN q[363]
    DIRECTION OUTPUT ;
    USE SIGNAL ;
    PORT
      LAYER M5 ;
        RECT  60.432 51.756 60.456 51.84 ;
    END
  END q[363]
  PIN q[364]
    DIRECTION OUTPUT ;
    USE SIGNAL ;
    PORT
      LAYER M5 ;
        RECT  60.576 51.756 60.6 51.84 ;
    END
  END q[364]
  PIN q[365]
    DIRECTION OUTPUT ;
    USE SIGNAL ;
    PORT
      LAYER M5 ;
        RECT  60.72 51.756 60.744 51.84 ;
    END
  END q[365]
  PIN q[366]
    DIRECTION OUTPUT ;
    USE SIGNAL ;
    PORT
      LAYER M5 ;
        RECT  60.864 51.756 60.888 51.84 ;
    END
  END q[366]
  PIN q[367]
    DIRECTION OUTPUT ;
    USE SIGNAL ;
    PORT
      LAYER M5 ;
        RECT  61.008 51.756 61.032 51.84 ;
    END
  END q[367]
  PIN q[368]
    DIRECTION OUTPUT ;
    USE SIGNAL ;
    PORT
      LAYER M5 ;
        RECT  61.152 51.756 61.176 51.84 ;
    END
  END q[368]
  PIN q[369]
    DIRECTION OUTPUT ;
    USE SIGNAL ;
    PORT
      LAYER M5 ;
        RECT  61.296 51.756 61.32 51.84 ;
    END
  END q[369]
  PIN q[36]
    DIRECTION OUTPUT ;
    USE SIGNAL ;
    PORT
      LAYER M5 ;
        RECT  11.904 51.756 11.928 51.84 ;
    END
  END q[36]
  PIN q[370]
    DIRECTION OUTPUT ;
    USE SIGNAL ;
    PORT
      LAYER M5 ;
        RECT  61.44 51.756 61.464 51.84 ;
    END
  END q[370]
  PIN q[371]
    DIRECTION OUTPUT ;
    USE SIGNAL ;
    PORT
      LAYER M5 ;
        RECT  61.584 51.756 61.608 51.84 ;
    END
  END q[371]
  PIN q[372]
    DIRECTION OUTPUT ;
    USE SIGNAL ;
    PORT
      LAYER M5 ;
        RECT  61.728 51.756 61.752 51.84 ;
    END
  END q[372]
  PIN q[373]
    DIRECTION OUTPUT ;
    USE SIGNAL ;
    PORT
      LAYER M5 ;
        RECT  61.872 51.756 61.896 51.84 ;
    END
  END q[373]
  PIN q[374]
    DIRECTION OUTPUT ;
    USE SIGNAL ;
    PORT
      LAYER M5 ;
        RECT  62.016 51.756 62.04 51.84 ;
    END
  END q[374]
  PIN q[375]
    DIRECTION OUTPUT ;
    USE SIGNAL ;
    PORT
      LAYER M5 ;
        RECT  62.16 51.756 62.184 51.84 ;
    END
  END q[375]
  PIN q[376]
    DIRECTION OUTPUT ;
    USE SIGNAL ;
    PORT
      LAYER M5 ;
        RECT  62.304 51.756 62.328 51.84 ;
    END
  END q[376]
  PIN q[377]
    DIRECTION OUTPUT ;
    USE SIGNAL ;
    PORT
      LAYER M5 ;
        RECT  62.448 51.756 62.472 51.84 ;
    END
  END q[377]
  PIN q[378]
    DIRECTION OUTPUT ;
    USE SIGNAL ;
    PORT
      LAYER M5 ;
        RECT  62.592 51.756 62.616 51.84 ;
    END
  END q[378]
  PIN q[379]
    DIRECTION OUTPUT ;
    USE SIGNAL ;
    PORT
      LAYER M5 ;
        RECT  62.736 51.756 62.76 51.84 ;
    END
  END q[379]
  PIN q[37]
    DIRECTION OUTPUT ;
    USE SIGNAL ;
    PORT
      LAYER M5 ;
        RECT  12.048 51.756 12.072 51.84 ;
    END
  END q[37]
  PIN q[380]
    DIRECTION OUTPUT ;
    USE SIGNAL ;
    PORT
      LAYER M5 ;
        RECT  62.88 51.756 62.904 51.84 ;
    END
  END q[380]
  PIN q[381]
    DIRECTION OUTPUT ;
    USE SIGNAL ;
    PORT
      LAYER M5 ;
        RECT  63.024 51.756 63.048 51.84 ;
    END
  END q[381]
  PIN q[382]
    DIRECTION OUTPUT ;
    USE SIGNAL ;
    PORT
      LAYER M5 ;
        RECT  63.168 51.756 63.192 51.84 ;
    END
  END q[382]
  PIN q[383]
    DIRECTION OUTPUT ;
    USE SIGNAL ;
    PORT
      LAYER M5 ;
        RECT  63.312 51.756 63.336 51.84 ;
    END
  END q[383]
  PIN q[384]
    DIRECTION OUTPUT ;
    USE SIGNAL ;
    PORT
      LAYER M5 ;
        RECT  63.456 51.756 63.48 51.84 ;
    END
  END q[384]
  PIN q[385]
    DIRECTION OUTPUT ;
    USE SIGNAL ;
    PORT
      LAYER M5 ;
        RECT  63.6 51.756 63.624 51.84 ;
    END
  END q[385]
  PIN q[386]
    DIRECTION OUTPUT ;
    USE SIGNAL ;
    PORT
      LAYER M5 ;
        RECT  63.744 51.756 63.768 51.84 ;
    END
  END q[386]
  PIN q[387]
    DIRECTION OUTPUT ;
    USE SIGNAL ;
    PORT
      LAYER M5 ;
        RECT  63.888 51.756 63.912 51.84 ;
    END
  END q[387]
  PIN q[388]
    DIRECTION OUTPUT ;
    USE SIGNAL ;
    PORT
      LAYER M5 ;
        RECT  64.032 51.756 64.056 51.84 ;
    END
  END q[388]
  PIN q[389]
    DIRECTION OUTPUT ;
    USE SIGNAL ;
    PORT
      LAYER M5 ;
        RECT  64.176 51.756 64.2 51.84 ;
    END
  END q[389]
  PIN q[38]
    DIRECTION OUTPUT ;
    USE SIGNAL ;
    PORT
      LAYER M5 ;
        RECT  12.192 51.756 12.216 51.84 ;
    END
  END q[38]
  PIN q[390]
    DIRECTION OUTPUT ;
    USE SIGNAL ;
    PORT
      LAYER M5 ;
        RECT  64.32 51.756 64.344 51.84 ;
    END
  END q[390]
  PIN q[391]
    DIRECTION OUTPUT ;
    USE SIGNAL ;
    PORT
      LAYER M5 ;
        RECT  64.464 51.756 64.488 51.84 ;
    END
  END q[391]
  PIN q[392]
    DIRECTION OUTPUT ;
    USE SIGNAL ;
    PORT
      LAYER M5 ;
        RECT  64.608 51.756 64.632 51.84 ;
    END
  END q[392]
  PIN q[393]
    DIRECTION OUTPUT ;
    USE SIGNAL ;
    PORT
      LAYER M5 ;
        RECT  64.752 51.756 64.776 51.84 ;
    END
  END q[393]
  PIN q[394]
    DIRECTION OUTPUT ;
    USE SIGNAL ;
    PORT
      LAYER M5 ;
        RECT  64.896 51.756 64.92 51.84 ;
    END
  END q[394]
  PIN q[395]
    DIRECTION OUTPUT ;
    USE SIGNAL ;
    PORT
      LAYER M5 ;
        RECT  65.04 51.756 65.064 51.84 ;
    END
  END q[395]
  PIN q[396]
    DIRECTION OUTPUT ;
    USE SIGNAL ;
    PORT
      LAYER M5 ;
        RECT  65.184 51.756 65.208 51.84 ;
    END
  END q[396]
  PIN q[397]
    DIRECTION OUTPUT ;
    USE SIGNAL ;
    PORT
      LAYER M5 ;
        RECT  65.328 51.756 65.352 51.84 ;
    END
  END q[397]
  PIN q[398]
    DIRECTION OUTPUT ;
    USE SIGNAL ;
    PORT
      LAYER M5 ;
        RECT  65.472 51.756 65.496 51.84 ;
    END
  END q[398]
  PIN q[399]
    DIRECTION OUTPUT ;
    USE SIGNAL ;
    PORT
      LAYER M5 ;
        RECT  65.616 51.756 65.64 51.84 ;
    END
  END q[399]
  PIN q[39]
    DIRECTION OUTPUT ;
    USE SIGNAL ;
    PORT
      LAYER M5 ;
        RECT  12.336 51.756 12.36 51.84 ;
    END
  END q[39]
  PIN q[3]
    DIRECTION OUTPUT ;
    USE SIGNAL ;
    PORT
      LAYER M5 ;
        RECT  7.152 51.756 7.176 51.84 ;
    END
  END q[3]
  PIN q[400]
    DIRECTION OUTPUT ;
    USE SIGNAL ;
    PORT
      LAYER M5 ;
        RECT  65.76 51.756 65.784 51.84 ;
    END
  END q[400]
  PIN q[401]
    DIRECTION OUTPUT ;
    USE SIGNAL ;
    PORT
      LAYER M5 ;
        RECT  65.904 51.756 65.928 51.84 ;
    END
  END q[401]
  PIN q[402]
    DIRECTION OUTPUT ;
    USE SIGNAL ;
    PORT
      LAYER M5 ;
        RECT  66.048 51.756 66.072 51.84 ;
    END
  END q[402]
  PIN q[403]
    DIRECTION OUTPUT ;
    USE SIGNAL ;
    PORT
      LAYER M5 ;
        RECT  66.192 51.756 66.216 51.84 ;
    END
  END q[403]
  PIN q[404]
    DIRECTION OUTPUT ;
    USE SIGNAL ;
    PORT
      LAYER M5 ;
        RECT  66.336 51.756 66.36 51.84 ;
    END
  END q[404]
  PIN q[405]
    DIRECTION OUTPUT ;
    USE SIGNAL ;
    PORT
      LAYER M5 ;
        RECT  66.48 51.756 66.504 51.84 ;
    END
  END q[405]
  PIN q[406]
    DIRECTION OUTPUT ;
    USE SIGNAL ;
    PORT
      LAYER M5 ;
        RECT  66.624 51.756 66.648 51.84 ;
    END
  END q[406]
  PIN q[407]
    DIRECTION OUTPUT ;
    USE SIGNAL ;
    PORT
      LAYER M5 ;
        RECT  66.768 51.756 66.792 51.84 ;
    END
  END q[407]
  PIN q[408]
    DIRECTION OUTPUT ;
    USE SIGNAL ;
    PORT
      LAYER M5 ;
        RECT  66.912 51.756 66.936 51.84 ;
    END
  END q[408]
  PIN q[409]
    DIRECTION OUTPUT ;
    USE SIGNAL ;
    PORT
      LAYER M5 ;
        RECT  67.056 51.756 67.08 51.84 ;
    END
  END q[409]
  PIN q[40]
    DIRECTION OUTPUT ;
    USE SIGNAL ;
    PORT
      LAYER M5 ;
        RECT  12.48 51.756 12.504 51.84 ;
    END
  END q[40]
  PIN q[410]
    DIRECTION OUTPUT ;
    USE SIGNAL ;
    PORT
      LAYER M5 ;
        RECT  67.2 51.756 67.224 51.84 ;
    END
  END q[410]
  PIN q[411]
    DIRECTION OUTPUT ;
    USE SIGNAL ;
    PORT
      LAYER M5 ;
        RECT  67.344 51.756 67.368 51.84 ;
    END
  END q[411]
  PIN q[412]
    DIRECTION OUTPUT ;
    USE SIGNAL ;
    PORT
      LAYER M5 ;
        RECT  67.488 51.756 67.512 51.84 ;
    END
  END q[412]
  PIN q[413]
    DIRECTION OUTPUT ;
    USE SIGNAL ;
    PORT
      LAYER M5 ;
        RECT  67.632 51.756 67.656 51.84 ;
    END
  END q[413]
  PIN q[414]
    DIRECTION OUTPUT ;
    USE SIGNAL ;
    PORT
      LAYER M5 ;
        RECT  67.776 51.756 67.8 51.84 ;
    END
  END q[414]
  PIN q[415]
    DIRECTION OUTPUT ;
    USE SIGNAL ;
    PORT
      LAYER M5 ;
        RECT  67.92 51.756 67.944 51.84 ;
    END
  END q[415]
  PIN q[416]
    DIRECTION OUTPUT ;
    USE SIGNAL ;
    PORT
      LAYER M5 ;
        RECT  68.064 51.756 68.088 51.84 ;
    END
  END q[416]
  PIN q[417]
    DIRECTION OUTPUT ;
    USE SIGNAL ;
    PORT
      LAYER M5 ;
        RECT  68.208 51.756 68.232 51.84 ;
    END
  END q[417]
  PIN q[418]
    DIRECTION OUTPUT ;
    USE SIGNAL ;
    PORT
      LAYER M5 ;
        RECT  68.352 51.756 68.376 51.84 ;
    END
  END q[418]
  PIN q[419]
    DIRECTION OUTPUT ;
    USE SIGNAL ;
    PORT
      LAYER M5 ;
        RECT  68.496 51.756 68.52 51.84 ;
    END
  END q[419]
  PIN q[41]
    DIRECTION OUTPUT ;
    USE SIGNAL ;
    PORT
      LAYER M5 ;
        RECT  12.624 51.756 12.648 51.84 ;
    END
  END q[41]
  PIN q[420]
    DIRECTION OUTPUT ;
    USE SIGNAL ;
    PORT
      LAYER M5 ;
        RECT  68.64 51.756 68.664 51.84 ;
    END
  END q[420]
  PIN q[421]
    DIRECTION OUTPUT ;
    USE SIGNAL ;
    PORT
      LAYER M5 ;
        RECT  68.784 51.756 68.808 51.84 ;
    END
  END q[421]
  PIN q[422]
    DIRECTION OUTPUT ;
    USE SIGNAL ;
    PORT
      LAYER M5 ;
        RECT  68.928 51.756 68.952 51.84 ;
    END
  END q[422]
  PIN q[423]
    DIRECTION OUTPUT ;
    USE SIGNAL ;
    PORT
      LAYER M5 ;
        RECT  69.072 51.756 69.096 51.84 ;
    END
  END q[423]
  PIN q[424]
    DIRECTION OUTPUT ;
    USE SIGNAL ;
    PORT
      LAYER M5 ;
        RECT  69.216 51.756 69.24 51.84 ;
    END
  END q[424]
  PIN q[425]
    DIRECTION OUTPUT ;
    USE SIGNAL ;
    PORT
      LAYER M5 ;
        RECT  69.36 51.756 69.384 51.84 ;
    END
  END q[425]
  PIN q[426]
    DIRECTION OUTPUT ;
    USE SIGNAL ;
    PORT
      LAYER M5 ;
        RECT  69.504 51.756 69.528 51.84 ;
    END
  END q[426]
  PIN q[427]
    DIRECTION OUTPUT ;
    USE SIGNAL ;
    PORT
      LAYER M5 ;
        RECT  69.648 51.756 69.672 51.84 ;
    END
  END q[427]
  PIN q[428]
    DIRECTION OUTPUT ;
    USE SIGNAL ;
    PORT
      LAYER M5 ;
        RECT  69.792 51.756 69.816 51.84 ;
    END
  END q[428]
  PIN q[429]
    DIRECTION OUTPUT ;
    USE SIGNAL ;
    PORT
      LAYER M5 ;
        RECT  69.936 51.756 69.96 51.84 ;
    END
  END q[429]
  PIN q[42]
    DIRECTION OUTPUT ;
    USE SIGNAL ;
    PORT
      LAYER M5 ;
        RECT  12.768 51.756 12.792 51.84 ;
    END
  END q[42]
  PIN q[430]
    DIRECTION OUTPUT ;
    USE SIGNAL ;
    PORT
      LAYER M5 ;
        RECT  70.08 51.756 70.104 51.84 ;
    END
  END q[430]
  PIN q[431]
    DIRECTION OUTPUT ;
    USE SIGNAL ;
    PORT
      LAYER M5 ;
        RECT  70.224 51.756 70.248 51.84 ;
    END
  END q[431]
  PIN q[432]
    DIRECTION OUTPUT ;
    USE SIGNAL ;
    PORT
      LAYER M5 ;
        RECT  70.368 51.756 70.392 51.84 ;
    END
  END q[432]
  PIN q[433]
    DIRECTION OUTPUT ;
    USE SIGNAL ;
    PORT
      LAYER M5 ;
        RECT  70.512 51.756 70.536 51.84 ;
    END
  END q[433]
  PIN q[434]
    DIRECTION OUTPUT ;
    USE SIGNAL ;
    PORT
      LAYER M5 ;
        RECT  70.656 51.756 70.68 51.84 ;
    END
  END q[434]
  PIN q[435]
    DIRECTION OUTPUT ;
    USE SIGNAL ;
    PORT
      LAYER M5 ;
        RECT  70.8 51.756 70.824 51.84 ;
    END
  END q[435]
  PIN q[436]
    DIRECTION OUTPUT ;
    USE SIGNAL ;
    PORT
      LAYER M5 ;
        RECT  70.944 51.756 70.968 51.84 ;
    END
  END q[436]
  PIN q[437]
    DIRECTION OUTPUT ;
    USE SIGNAL ;
    PORT
      LAYER M5 ;
        RECT  71.088 51.756 71.112 51.84 ;
    END
  END q[437]
  PIN q[438]
    DIRECTION OUTPUT ;
    USE SIGNAL ;
    PORT
      LAYER M5 ;
        RECT  71.232 51.756 71.256 51.84 ;
    END
  END q[438]
  PIN q[439]
    DIRECTION OUTPUT ;
    USE SIGNAL ;
    PORT
      LAYER M5 ;
        RECT  71.376 51.756 71.4 51.84 ;
    END
  END q[439]
  PIN q[43]
    DIRECTION OUTPUT ;
    USE SIGNAL ;
    PORT
      LAYER M5 ;
        RECT  12.912 51.756 12.936 51.84 ;
    END
  END q[43]
  PIN q[440]
    DIRECTION OUTPUT ;
    USE SIGNAL ;
    PORT
      LAYER M5 ;
        RECT  71.52 51.756 71.544 51.84 ;
    END
  END q[440]
  PIN q[441]
    DIRECTION OUTPUT ;
    USE SIGNAL ;
    PORT
      LAYER M5 ;
        RECT  71.664 51.756 71.688 51.84 ;
    END
  END q[441]
  PIN q[442]
    DIRECTION OUTPUT ;
    USE SIGNAL ;
    PORT
      LAYER M5 ;
        RECT  71.808 51.756 71.832 51.84 ;
    END
  END q[442]
  PIN q[443]
    DIRECTION OUTPUT ;
    USE SIGNAL ;
    PORT
      LAYER M5 ;
        RECT  71.952 51.756 71.976 51.84 ;
    END
  END q[443]
  PIN q[444]
    DIRECTION OUTPUT ;
    USE SIGNAL ;
    PORT
      LAYER M5 ;
        RECT  72.096 51.756 72.12 51.84 ;
    END
  END q[444]
  PIN q[445]
    DIRECTION OUTPUT ;
    USE SIGNAL ;
    PORT
      LAYER M5 ;
        RECT  72.24 51.756 72.264 51.84 ;
    END
  END q[445]
  PIN q[446]
    DIRECTION OUTPUT ;
    USE SIGNAL ;
    PORT
      LAYER M5 ;
        RECT  72.384 51.756 72.408 51.84 ;
    END
  END q[446]
  PIN q[447]
    DIRECTION OUTPUT ;
    USE SIGNAL ;
    PORT
      LAYER M5 ;
        RECT  72.528 51.756 72.552 51.84 ;
    END
  END q[447]
  PIN q[448]
    DIRECTION OUTPUT ;
    USE SIGNAL ;
    PORT
      LAYER M5 ;
        RECT  72.672 51.756 72.696 51.84 ;
    END
  END q[448]
  PIN q[449]
    DIRECTION OUTPUT ;
    USE SIGNAL ;
    PORT
      LAYER M5 ;
        RECT  72.816 51.756 72.84 51.84 ;
    END
  END q[449]
  PIN q[44]
    DIRECTION OUTPUT ;
    USE SIGNAL ;
    PORT
      LAYER M5 ;
        RECT  13.056 51.756 13.08 51.84 ;
    END
  END q[44]
  PIN q[450]
    DIRECTION OUTPUT ;
    USE SIGNAL ;
    PORT
      LAYER M5 ;
        RECT  72.96 51.756 72.984 51.84 ;
    END
  END q[450]
  PIN q[451]
    DIRECTION OUTPUT ;
    USE SIGNAL ;
    PORT
      LAYER M5 ;
        RECT  73.104 51.756 73.128 51.84 ;
    END
  END q[451]
  PIN q[452]
    DIRECTION OUTPUT ;
    USE SIGNAL ;
    PORT
      LAYER M5 ;
        RECT  73.248 51.756 73.272 51.84 ;
    END
  END q[452]
  PIN q[453]
    DIRECTION OUTPUT ;
    USE SIGNAL ;
    PORT
      LAYER M5 ;
        RECT  73.392 51.756 73.416 51.84 ;
    END
  END q[453]
  PIN q[454]
    DIRECTION OUTPUT ;
    USE SIGNAL ;
    PORT
      LAYER M5 ;
        RECT  73.536 51.756 73.56 51.84 ;
    END
  END q[454]
  PIN q[455]
    DIRECTION OUTPUT ;
    USE SIGNAL ;
    PORT
      LAYER M5 ;
        RECT  73.68 51.756 73.704 51.84 ;
    END
  END q[455]
  PIN q[456]
    DIRECTION OUTPUT ;
    USE SIGNAL ;
    PORT
      LAYER M5 ;
        RECT  73.824 51.756 73.848 51.84 ;
    END
  END q[456]
  PIN q[457]
    DIRECTION OUTPUT ;
    USE SIGNAL ;
    PORT
      LAYER M5 ;
        RECT  73.968 51.756 73.992 51.84 ;
    END
  END q[457]
  PIN q[458]
    DIRECTION OUTPUT ;
    USE SIGNAL ;
    PORT
      LAYER M5 ;
        RECT  74.112 51.756 74.136 51.84 ;
    END
  END q[458]
  PIN q[459]
    DIRECTION OUTPUT ;
    USE SIGNAL ;
    PORT
      LAYER M5 ;
        RECT  74.256 51.756 74.28 51.84 ;
    END
  END q[459]
  PIN q[45]
    DIRECTION OUTPUT ;
    USE SIGNAL ;
    PORT
      LAYER M5 ;
        RECT  13.2 51.756 13.224 51.84 ;
    END
  END q[45]
  PIN q[460]
    DIRECTION OUTPUT ;
    USE SIGNAL ;
    PORT
      LAYER M5 ;
        RECT  74.4 51.756 74.424 51.84 ;
    END
  END q[460]
  PIN q[461]
    DIRECTION OUTPUT ;
    USE SIGNAL ;
    PORT
      LAYER M5 ;
        RECT  74.544 51.756 74.568 51.84 ;
    END
  END q[461]
  PIN q[462]
    DIRECTION OUTPUT ;
    USE SIGNAL ;
    PORT
      LAYER M5 ;
        RECT  74.688 51.756 74.712 51.84 ;
    END
  END q[462]
  PIN q[463]
    DIRECTION OUTPUT ;
    USE SIGNAL ;
    PORT
      LAYER M5 ;
        RECT  74.832 51.756 74.856 51.84 ;
    END
  END q[463]
  PIN q[464]
    DIRECTION OUTPUT ;
    USE SIGNAL ;
    PORT
      LAYER M5 ;
        RECT  74.976 51.756 75 51.84 ;
    END
  END q[464]
  PIN q[465]
    DIRECTION OUTPUT ;
    USE SIGNAL ;
    PORT
      LAYER M5 ;
        RECT  75.12 51.756 75.144 51.84 ;
    END
  END q[465]
  PIN q[466]
    DIRECTION OUTPUT ;
    USE SIGNAL ;
    PORT
      LAYER M5 ;
        RECT  75.264 51.756 75.288 51.84 ;
    END
  END q[466]
  PIN q[467]
    DIRECTION OUTPUT ;
    USE SIGNAL ;
    PORT
      LAYER M5 ;
        RECT  75.408 51.756 75.432 51.84 ;
    END
  END q[467]
  PIN q[468]
    DIRECTION OUTPUT ;
    USE SIGNAL ;
    PORT
      LAYER M5 ;
        RECT  75.552 51.756 75.576 51.84 ;
    END
  END q[468]
  PIN q[469]
    DIRECTION OUTPUT ;
    USE SIGNAL ;
    PORT
      LAYER M5 ;
        RECT  75.696 51.756 75.72 51.84 ;
    END
  END q[469]
  PIN q[46]
    DIRECTION OUTPUT ;
    USE SIGNAL ;
    PORT
      LAYER M5 ;
        RECT  13.344 51.756 13.368 51.84 ;
    END
  END q[46]
  PIN q[470]
    DIRECTION OUTPUT ;
    USE SIGNAL ;
    PORT
      LAYER M5 ;
        RECT  75.84 51.756 75.864 51.84 ;
    END
  END q[470]
  PIN q[471]
    DIRECTION OUTPUT ;
    USE SIGNAL ;
    PORT
      LAYER M5 ;
        RECT  75.984 51.756 76.008 51.84 ;
    END
  END q[471]
  PIN q[472]
    DIRECTION OUTPUT ;
    USE SIGNAL ;
    PORT
      LAYER M5 ;
        RECT  76.128 51.756 76.152 51.84 ;
    END
  END q[472]
  PIN q[473]
    DIRECTION OUTPUT ;
    USE SIGNAL ;
    PORT
      LAYER M5 ;
        RECT  76.272 51.756 76.296 51.84 ;
    END
  END q[473]
  PIN q[474]
    DIRECTION OUTPUT ;
    USE SIGNAL ;
    PORT
      LAYER M5 ;
        RECT  76.416 51.756 76.44 51.84 ;
    END
  END q[474]
  PIN q[475]
    DIRECTION OUTPUT ;
    USE SIGNAL ;
    PORT
      LAYER M5 ;
        RECT  76.56 51.756 76.584 51.84 ;
    END
  END q[475]
  PIN q[476]
    DIRECTION OUTPUT ;
    USE SIGNAL ;
    PORT
      LAYER M5 ;
        RECT  76.704 51.756 76.728 51.84 ;
    END
  END q[476]
  PIN q[477]
    DIRECTION OUTPUT ;
    USE SIGNAL ;
    PORT
      LAYER M5 ;
        RECT  76.848 51.756 76.872 51.84 ;
    END
  END q[477]
  PIN q[478]
    DIRECTION OUTPUT ;
    USE SIGNAL ;
    PORT
      LAYER M5 ;
        RECT  76.992 51.756 77.016 51.84 ;
    END
  END q[478]
  PIN q[479]
    DIRECTION OUTPUT ;
    USE SIGNAL ;
    PORT
      LAYER M5 ;
        RECT  77.136 51.756 77.16 51.84 ;
    END
  END q[479]
  PIN q[47]
    DIRECTION OUTPUT ;
    USE SIGNAL ;
    PORT
      LAYER M5 ;
        RECT  13.488 51.756 13.512 51.84 ;
    END
  END q[47]
  PIN q[480]
    DIRECTION OUTPUT ;
    USE SIGNAL ;
    PORT
      LAYER M5 ;
        RECT  77.28 51.756 77.304 51.84 ;
    END
  END q[480]
  PIN q[481]
    DIRECTION OUTPUT ;
    USE SIGNAL ;
    PORT
      LAYER M5 ;
        RECT  77.424 51.756 77.448 51.84 ;
    END
  END q[481]
  PIN q[482]
    DIRECTION OUTPUT ;
    USE SIGNAL ;
    PORT
      LAYER M5 ;
        RECT  77.568 51.756 77.592 51.84 ;
    END
  END q[482]
  PIN q[483]
    DIRECTION OUTPUT ;
    USE SIGNAL ;
    PORT
      LAYER M5 ;
        RECT  77.712 51.756 77.736 51.84 ;
    END
  END q[483]
  PIN q[484]
    DIRECTION OUTPUT ;
    USE SIGNAL ;
    PORT
      LAYER M5 ;
        RECT  77.856 51.756 77.88 51.84 ;
    END
  END q[484]
  PIN q[485]
    DIRECTION OUTPUT ;
    USE SIGNAL ;
    PORT
      LAYER M5 ;
        RECT  78 51.756 78.024 51.84 ;
    END
  END q[485]
  PIN q[486]
    DIRECTION OUTPUT ;
    USE SIGNAL ;
    PORT
      LAYER M5 ;
        RECT  78.144 51.756 78.168 51.84 ;
    END
  END q[486]
  PIN q[487]
    DIRECTION OUTPUT ;
    USE SIGNAL ;
    PORT
      LAYER M5 ;
        RECT  78.288 51.756 78.312 51.84 ;
    END
  END q[487]
  PIN q[488]
    DIRECTION OUTPUT ;
    USE SIGNAL ;
    PORT
      LAYER M5 ;
        RECT  78.432 51.756 78.456 51.84 ;
    END
  END q[488]
  PIN q[489]
    DIRECTION OUTPUT ;
    USE SIGNAL ;
    PORT
      LAYER M5 ;
        RECT  78.576 51.756 78.6 51.84 ;
    END
  END q[489]
  PIN q[48]
    DIRECTION OUTPUT ;
    USE SIGNAL ;
    PORT
      LAYER M5 ;
        RECT  13.632 51.756 13.656 51.84 ;
    END
  END q[48]
  PIN q[490]
    DIRECTION OUTPUT ;
    USE SIGNAL ;
    PORT
      LAYER M5 ;
        RECT  78.72 51.756 78.744 51.84 ;
    END
  END q[490]
  PIN q[491]
    DIRECTION OUTPUT ;
    USE SIGNAL ;
    PORT
      LAYER M5 ;
        RECT  78.864 51.756 78.888 51.84 ;
    END
  END q[491]
  PIN q[492]
    DIRECTION OUTPUT ;
    USE SIGNAL ;
    PORT
      LAYER M5 ;
        RECT  79.008 51.756 79.032 51.84 ;
    END
  END q[492]
  PIN q[493]
    DIRECTION OUTPUT ;
    USE SIGNAL ;
    PORT
      LAYER M5 ;
        RECT  79.152 51.756 79.176 51.84 ;
    END
  END q[493]
  PIN q[494]
    DIRECTION OUTPUT ;
    USE SIGNAL ;
    PORT
      LAYER M5 ;
        RECT  79.296 51.756 79.32 51.84 ;
    END
  END q[494]
  PIN q[495]
    DIRECTION OUTPUT ;
    USE SIGNAL ;
    PORT
      LAYER M5 ;
        RECT  79.44 51.756 79.464 51.84 ;
    END
  END q[495]
  PIN q[496]
    DIRECTION OUTPUT ;
    USE SIGNAL ;
    PORT
      LAYER M5 ;
        RECT  79.584 51.756 79.608 51.84 ;
    END
  END q[496]
  PIN q[497]
    DIRECTION OUTPUT ;
    USE SIGNAL ;
    PORT
      LAYER M5 ;
        RECT  79.728 51.756 79.752 51.84 ;
    END
  END q[497]
  PIN q[498]
    DIRECTION OUTPUT ;
    USE SIGNAL ;
    PORT
      LAYER M5 ;
        RECT  79.872 51.756 79.896 51.84 ;
    END
  END q[498]
  PIN q[499]
    DIRECTION OUTPUT ;
    USE SIGNAL ;
    PORT
      LAYER M5 ;
        RECT  80.016 51.756 80.04 51.84 ;
    END
  END q[499]
  PIN q[49]
    DIRECTION OUTPUT ;
    USE SIGNAL ;
    PORT
      LAYER M5 ;
        RECT  13.776 51.756 13.8 51.84 ;
    END
  END q[49]
  PIN q[4]
    DIRECTION OUTPUT ;
    USE SIGNAL ;
    PORT
      LAYER M5 ;
        RECT  7.296 51.756 7.32 51.84 ;
    END
  END q[4]
  PIN q[500]
    DIRECTION OUTPUT ;
    USE SIGNAL ;
    PORT
      LAYER M5 ;
        RECT  80.16 51.756 80.184 51.84 ;
    END
  END q[500]
  PIN q[501]
    DIRECTION OUTPUT ;
    USE SIGNAL ;
    PORT
      LAYER M5 ;
        RECT  80.304 51.756 80.328 51.84 ;
    END
  END q[501]
  PIN q[502]
    DIRECTION OUTPUT ;
    USE SIGNAL ;
    PORT
      LAYER M5 ;
        RECT  80.448 51.756 80.472 51.84 ;
    END
  END q[502]
  PIN q[503]
    DIRECTION OUTPUT ;
    USE SIGNAL ;
    PORT
      LAYER M5 ;
        RECT  80.592 51.756 80.616 51.84 ;
    END
  END q[503]
  PIN q[504]
    DIRECTION OUTPUT ;
    USE SIGNAL ;
    PORT
      LAYER M5 ;
        RECT  80.736 51.756 80.76 51.84 ;
    END
  END q[504]
  PIN q[505]
    DIRECTION OUTPUT ;
    USE SIGNAL ;
    PORT
      LAYER M5 ;
        RECT  80.88 51.756 80.904 51.84 ;
    END
  END q[505]
  PIN q[506]
    DIRECTION OUTPUT ;
    USE SIGNAL ;
    PORT
      LAYER M5 ;
        RECT  81.024 51.756 81.048 51.84 ;
    END
  END q[506]
  PIN q[507]
    DIRECTION OUTPUT ;
    USE SIGNAL ;
    PORT
      LAYER M5 ;
        RECT  81.168 51.756 81.192 51.84 ;
    END
  END q[507]
  PIN q[508]
    DIRECTION OUTPUT ;
    USE SIGNAL ;
    PORT
      LAYER M5 ;
        RECT  81.312 51.756 81.336 51.84 ;
    END
  END q[508]
  PIN q[509]
    DIRECTION OUTPUT ;
    USE SIGNAL ;
    PORT
      LAYER M5 ;
        RECT  81.456 51.756 81.48 51.84 ;
    END
  END q[509]
  PIN q[50]
    DIRECTION OUTPUT ;
    USE SIGNAL ;
    PORT
      LAYER M5 ;
        RECT  13.92 51.756 13.944 51.84 ;
    END
  END q[50]
  PIN q[510]
    DIRECTION OUTPUT ;
    USE SIGNAL ;
    PORT
      LAYER M5 ;
        RECT  81.6 51.756 81.624 51.84 ;
    END
  END q[510]
  PIN q[511]
    DIRECTION OUTPUT ;
    USE SIGNAL ;
    PORT
      LAYER M5 ;
        RECT  81.744 51.756 81.768 51.84 ;
    END
  END q[511]
  PIN q[512]
    DIRECTION OUTPUT ;
    USE SIGNAL ;
    PORT
      LAYER M5 ;
        RECT  81.888 51.756 81.912 51.84 ;
    END
  END q[512]
  PIN q[513]
    DIRECTION OUTPUT ;
    USE SIGNAL ;
    PORT
      LAYER M5 ;
        RECT  82.032 51.756 82.056 51.84 ;
    END
  END q[513]
  PIN q[514]
    DIRECTION OUTPUT ;
    USE SIGNAL ;
    PORT
      LAYER M5 ;
        RECT  82.176 51.756 82.2 51.84 ;
    END
  END q[514]
  PIN q[515]
    DIRECTION OUTPUT ;
    USE SIGNAL ;
    PORT
      LAYER M5 ;
        RECT  82.32 51.756 82.344 51.84 ;
    END
  END q[515]
  PIN q[516]
    DIRECTION OUTPUT ;
    USE SIGNAL ;
    PORT
      LAYER M5 ;
        RECT  82.464 51.756 82.488 51.84 ;
    END
  END q[516]
  PIN q[51]
    DIRECTION OUTPUT ;
    USE SIGNAL ;
    PORT
      LAYER M5 ;
        RECT  14.064 51.756 14.088 51.84 ;
    END
  END q[51]
  PIN q[52]
    DIRECTION OUTPUT ;
    USE SIGNAL ;
    PORT
      LAYER M5 ;
        RECT  14.208 51.756 14.232 51.84 ;
    END
  END q[52]
  PIN q[53]
    DIRECTION OUTPUT ;
    USE SIGNAL ;
    PORT
      LAYER M5 ;
        RECT  14.352 51.756 14.376 51.84 ;
    END
  END q[53]
  PIN q[54]
    DIRECTION OUTPUT ;
    USE SIGNAL ;
    PORT
      LAYER M5 ;
        RECT  14.496 51.756 14.52 51.84 ;
    END
  END q[54]
  PIN q[55]
    DIRECTION OUTPUT ;
    USE SIGNAL ;
    PORT
      LAYER M5 ;
        RECT  14.64 51.756 14.664 51.84 ;
    END
  END q[55]
  PIN q[56]
    DIRECTION OUTPUT ;
    USE SIGNAL ;
    PORT
      LAYER M5 ;
        RECT  14.784 51.756 14.808 51.84 ;
    END
  END q[56]
  PIN q[57]
    DIRECTION OUTPUT ;
    USE SIGNAL ;
    PORT
      LAYER M5 ;
        RECT  14.928 51.756 14.952 51.84 ;
    END
  END q[57]
  PIN q[58]
    DIRECTION OUTPUT ;
    USE SIGNAL ;
    PORT
      LAYER M5 ;
        RECT  15.072 51.756 15.096 51.84 ;
    END
  END q[58]
  PIN q[59]
    DIRECTION OUTPUT ;
    USE SIGNAL ;
    PORT
      LAYER M5 ;
        RECT  15.216 51.756 15.24 51.84 ;
    END
  END q[59]
  PIN q[5]
    DIRECTION OUTPUT ;
    USE SIGNAL ;
    PORT
      LAYER M5 ;
        RECT  7.44 51.756 7.464 51.84 ;
    END
  END q[5]
  PIN q[60]
    DIRECTION OUTPUT ;
    USE SIGNAL ;
    PORT
      LAYER M5 ;
        RECT  15.36 51.756 15.384 51.84 ;
    END
  END q[60]
  PIN q[61]
    DIRECTION OUTPUT ;
    USE SIGNAL ;
    PORT
      LAYER M5 ;
        RECT  15.504 51.756 15.528 51.84 ;
    END
  END q[61]
  PIN q[62]
    DIRECTION OUTPUT ;
    USE SIGNAL ;
    PORT
      LAYER M5 ;
        RECT  15.648 51.756 15.672 51.84 ;
    END
  END q[62]
  PIN q[63]
    DIRECTION OUTPUT ;
    USE SIGNAL ;
    PORT
      LAYER M5 ;
        RECT  15.792 51.756 15.816 51.84 ;
    END
  END q[63]
  PIN q[64]
    DIRECTION OUTPUT ;
    USE SIGNAL ;
    PORT
      LAYER M5 ;
        RECT  15.936 51.756 15.96 51.84 ;
    END
  END q[64]
  PIN q[65]
    DIRECTION OUTPUT ;
    USE SIGNAL ;
    PORT
      LAYER M5 ;
        RECT  16.08 51.756 16.104 51.84 ;
    END
  END q[65]
  PIN q[66]
    DIRECTION OUTPUT ;
    USE SIGNAL ;
    PORT
      LAYER M5 ;
        RECT  16.224 51.756 16.248 51.84 ;
    END
  END q[66]
  PIN q[67]
    DIRECTION OUTPUT ;
    USE SIGNAL ;
    PORT
      LAYER M5 ;
        RECT  16.368 51.756 16.392 51.84 ;
    END
  END q[67]
  PIN q[68]
    DIRECTION OUTPUT ;
    USE SIGNAL ;
    PORT
      LAYER M5 ;
        RECT  16.512 51.756 16.536 51.84 ;
    END
  END q[68]
  PIN q[69]
    DIRECTION OUTPUT ;
    USE SIGNAL ;
    PORT
      LAYER M5 ;
        RECT  16.656 51.756 16.68 51.84 ;
    END
  END q[69]
  PIN q[6]
    DIRECTION OUTPUT ;
    USE SIGNAL ;
    PORT
      LAYER M5 ;
        RECT  7.584 51.756 7.608 51.84 ;
    END
  END q[6]
  PIN q[70]
    DIRECTION OUTPUT ;
    USE SIGNAL ;
    PORT
      LAYER M5 ;
        RECT  16.8 51.756 16.824 51.84 ;
    END
  END q[70]
  PIN q[71]
    DIRECTION OUTPUT ;
    USE SIGNAL ;
    PORT
      LAYER M5 ;
        RECT  16.944 51.756 16.968 51.84 ;
    END
  END q[71]
  PIN q[72]
    DIRECTION OUTPUT ;
    USE SIGNAL ;
    PORT
      LAYER M5 ;
        RECT  17.088 51.756 17.112 51.84 ;
    END
  END q[72]
  PIN q[73]
    DIRECTION OUTPUT ;
    USE SIGNAL ;
    PORT
      LAYER M5 ;
        RECT  17.232 51.756 17.256 51.84 ;
    END
  END q[73]
  PIN q[74]
    DIRECTION OUTPUT ;
    USE SIGNAL ;
    PORT
      LAYER M5 ;
        RECT  17.376 51.756 17.4 51.84 ;
    END
  END q[74]
  PIN q[75]
    DIRECTION OUTPUT ;
    USE SIGNAL ;
    PORT
      LAYER M5 ;
        RECT  17.52 51.756 17.544 51.84 ;
    END
  END q[75]
  PIN q[76]
    DIRECTION OUTPUT ;
    USE SIGNAL ;
    PORT
      LAYER M5 ;
        RECT  17.664 51.756 17.688 51.84 ;
    END
  END q[76]
  PIN q[77]
    DIRECTION OUTPUT ;
    USE SIGNAL ;
    PORT
      LAYER M5 ;
        RECT  17.808 51.756 17.832 51.84 ;
    END
  END q[77]
  PIN q[78]
    DIRECTION OUTPUT ;
    USE SIGNAL ;
    PORT
      LAYER M5 ;
        RECT  17.952 51.756 17.976 51.84 ;
    END
  END q[78]
  PIN q[79]
    DIRECTION OUTPUT ;
    USE SIGNAL ;
    PORT
      LAYER M5 ;
        RECT  18.096 51.756 18.12 51.84 ;
    END
  END q[79]
  PIN q[7]
    DIRECTION OUTPUT ;
    USE SIGNAL ;
    PORT
      LAYER M5 ;
        RECT  7.728 51.756 7.752 51.84 ;
    END
  END q[7]
  PIN q[80]
    DIRECTION OUTPUT ;
    USE SIGNAL ;
    PORT
      LAYER M5 ;
        RECT  18.24 51.756 18.264 51.84 ;
    END
  END q[80]
  PIN q[81]
    DIRECTION OUTPUT ;
    USE SIGNAL ;
    PORT
      LAYER M5 ;
        RECT  18.384 51.756 18.408 51.84 ;
    END
  END q[81]
  PIN q[82]
    DIRECTION OUTPUT ;
    USE SIGNAL ;
    PORT
      LAYER M5 ;
        RECT  18.528 51.756 18.552 51.84 ;
    END
  END q[82]
  PIN q[83]
    DIRECTION OUTPUT ;
    USE SIGNAL ;
    PORT
      LAYER M5 ;
        RECT  18.672 51.756 18.696 51.84 ;
    END
  END q[83]
  PIN q[84]
    DIRECTION OUTPUT ;
    USE SIGNAL ;
    PORT
      LAYER M5 ;
        RECT  18.816 51.756 18.84 51.84 ;
    END
  END q[84]
  PIN q[85]
    DIRECTION OUTPUT ;
    USE SIGNAL ;
    PORT
      LAYER M5 ;
        RECT  18.96 51.756 18.984 51.84 ;
    END
  END q[85]
  PIN q[86]
    DIRECTION OUTPUT ;
    USE SIGNAL ;
    PORT
      LAYER M5 ;
        RECT  19.104 51.756 19.128 51.84 ;
    END
  END q[86]
  PIN q[87]
    DIRECTION OUTPUT ;
    USE SIGNAL ;
    PORT
      LAYER M5 ;
        RECT  19.248 51.756 19.272 51.84 ;
    END
  END q[87]
  PIN q[88]
    DIRECTION OUTPUT ;
    USE SIGNAL ;
    PORT
      LAYER M5 ;
        RECT  19.392 51.756 19.416 51.84 ;
    END
  END q[88]
  PIN q[89]
    DIRECTION OUTPUT ;
    USE SIGNAL ;
    PORT
      LAYER M5 ;
        RECT  19.536 51.756 19.56 51.84 ;
    END
  END q[89]
  PIN q[8]
    DIRECTION OUTPUT ;
    USE SIGNAL ;
    PORT
      LAYER M5 ;
        RECT  7.872 51.756 7.896 51.84 ;
    END
  END q[8]
  PIN q[90]
    DIRECTION OUTPUT ;
    USE SIGNAL ;
    PORT
      LAYER M5 ;
        RECT  19.68 51.756 19.704 51.84 ;
    END
  END q[90]
  PIN q[91]
    DIRECTION OUTPUT ;
    USE SIGNAL ;
    PORT
      LAYER M5 ;
        RECT  19.824 51.756 19.848 51.84 ;
    END
  END q[91]
  PIN q[92]
    DIRECTION OUTPUT ;
    USE SIGNAL ;
    PORT
      LAYER M5 ;
        RECT  19.968 51.756 19.992 51.84 ;
    END
  END q[92]
  PIN q[93]
    DIRECTION OUTPUT ;
    USE SIGNAL ;
    PORT
      LAYER M5 ;
        RECT  20.112 51.756 20.136 51.84 ;
    END
  END q[93]
  PIN q[94]
    DIRECTION OUTPUT ;
    USE SIGNAL ;
    PORT
      LAYER M5 ;
        RECT  20.256 51.756 20.28 51.84 ;
    END
  END q[94]
  PIN q[95]
    DIRECTION OUTPUT ;
    USE SIGNAL ;
    PORT
      LAYER M5 ;
        RECT  20.4 51.756 20.424 51.84 ;
    END
  END q[95]
  PIN q[96]
    DIRECTION OUTPUT ;
    USE SIGNAL ;
    PORT
      LAYER M5 ;
        RECT  20.544 51.756 20.568 51.84 ;
    END
  END q[96]
  PIN q[97]
    DIRECTION OUTPUT ;
    USE SIGNAL ;
    PORT
      LAYER M5 ;
        RECT  20.688 51.756 20.712 51.84 ;
    END
  END q[97]
  PIN q[98]
    DIRECTION OUTPUT ;
    USE SIGNAL ;
    PORT
      LAYER M5 ;
        RECT  20.832 51.756 20.856 51.84 ;
    END
  END q[98]
  PIN q[99]
    DIRECTION OUTPUT ;
    USE SIGNAL ;
    PORT
      LAYER M5 ;
        RECT  20.976 51.756 21 51.84 ;
    END
  END q[99]
  PIN q[9]
    DIRECTION OUTPUT ;
    USE SIGNAL ;
    PORT
      LAYER M5 ;
        RECT  8.016 51.756 8.04 51.84 ;
    END
  END q[9]
  PIN ready
    DIRECTION OUTPUT ;
    USE SIGNAL ;
    PORT
      LAYER M5 ;
        RECT  44.16 51.756 44.184 51.84 ;
    END
  END ready
  PIN rst_n
    DIRECTION INPUT ;
    USE SIGNAL ;
    PORT
      LAYER M5 ;
        RECT  44.016 51.756 44.04 51.84 ;
    END
  END rst_n
  PIN strap_k[0]
    DIRECTION INPUT ;
    USE SIGNAL ;
    PORT
      LAYER M5 ;
        RECT  44.448 51.756 44.472 51.84 ;
    END
  END strap_k[0]
  PIN strap_k[1]
    DIRECTION INPUT ;
    USE SIGNAL ;
    PORT
      LAYER M5 ;
        RECT  44.592 51.756 44.616 51.84 ;
    END
  END strap_k[1]
  PIN strap_k[2]
    DIRECTION INPUT ;
    USE SIGNAL ;
    PORT
      LAYER M5 ;
        RECT  44.736 51.756 44.76 51.84 ;
    END
  END strap_k[2]
  PIN strap_k[3]
    DIRECTION INPUT ;
    USE SIGNAL ;
    PORT
      LAYER M5 ;
        RECT  44.88 51.756 44.904 51.84 ;
    END
  END strap_k[3]
  PIN strap_k[4]
    DIRECTION INPUT ;
    USE SIGNAL ;
    PORT
      LAYER M5 ;
        RECT  45.024 51.756 45.048 51.84 ;
    END
  END strap_k[4]
  PIN strap_k[5]
    DIRECTION INPUT ;
    USE SIGNAL ;
    PORT
      LAYER M5 ;
        RECT  45.168 51.756 45.192 51.84 ;
    END
  END strap_k[5]
  PIN t_rst_n
    DIRECTION INPUT ;
    USE SIGNAL ;
    PORT
      LAYER M5 ;
        RECT  44.592 0 44.616 0.084 ;
    END
  END t_rst_n
  PIN VDD
    DIRECTION INOUT ;
    USE POWER ;
    PORT
      LAYER M5 ;
        RECT  84.276 4.311 84.396 47.529 ;
        RECT  79.956 4.311 80.076 47.529 ;
        RECT  75.636 4.311 75.756 47.529 ;
        RECT  71.316 4.311 71.436 47.529 ;
        RECT  66.996 4.311 67.116 47.529 ;
        RECT  62.676 4.311 62.796 47.529 ;
        RECT  58.356 4.311 58.476 47.529 ;
        RECT  54.036 4.311 54.156 47.529 ;
        RECT  49.716 4.311 49.836 47.529 ;
        RECT  45.396 4.311 45.516 47.529 ;
        RECT  41.076 4.311 41.196 47.529 ;
        RECT  36.756 4.311 36.876 47.529 ;
        RECT  32.436 4.311 32.556 47.529 ;
        RECT  28.116 4.311 28.236 47.529 ;
        RECT  23.796 4.311 23.916 47.529 ;
        RECT  19.476 4.311 19.596 47.529 ;
        RECT  15.156 4.311 15.276 47.529 ;
        RECT  10.836 4.311 10.956 47.529 ;
        RECT  6.516 4.311 6.636 47.529 ;
    END
  END VDD
  PIN VSS
    DIRECTION INOUT ;
    USE GROUND ;
    PORT
      LAYER M5 ;
        RECT  84.084 4.297 84.204 47.543 ;
        RECT  79.764 4.297 79.884 47.543 ;
        RECT  75.444 4.297 75.564 47.543 ;
        RECT  71.124 4.297 71.244 47.543 ;
        RECT  66.804 4.297 66.924 47.543 ;
        RECT  62.484 4.297 62.604 47.543 ;
        RECT  58.164 4.297 58.284 47.543 ;
        RECT  53.844 4.297 53.964 47.543 ;
        RECT  49.524 4.297 49.644 47.543 ;
        RECT  45.204 4.297 45.324 47.543 ;
        RECT  40.884 4.297 41.004 47.543 ;
        RECT  36.564 4.297 36.684 47.543 ;
        RECT  32.244 4.297 32.364 47.543 ;
        RECT  27.924 4.297 28.044 47.543 ;
        RECT  23.604 4.297 23.724 47.543 ;
        RECT  19.284 4.297 19.404 47.543 ;
        RECT  14.964 4.297 15.084 47.543 ;
        RECT  10.644 4.297 10.764 47.543 ;
        RECT  6.324 4.297 6.444 47.543 ;
    END
  END VSS
  OBS
    LAYER RVTN ;
     RECT  4.32 0 84.834 51.84 ;
    LAYER RVTP ;
     RECT  4.32 0 84.834 51.84 ;
    LAYER M1 ;
     RECT  4.32 0 84.834 51.84 ;
    LAYER M2 ;
     RECT  4.32 0 84.834 51.84 ;
    LAYER M3 ;
     RECT  4.32 0 84.834 51.84 ;
    LAYER M4 ;
     RECT  4.32 0 84.834 51.84 ;
    LAYER M5 ;
     RECT  4.32 0 84.834 51.84 ;
  END
END sle_cland_w517_s_301
END LIBRARY
